VERSION 5.7 ;
  NOWIREEXTENSIONATPIN ON ;
  DIVIDERCHAR "/" ;
  BUSBITCHARS "[]" ;
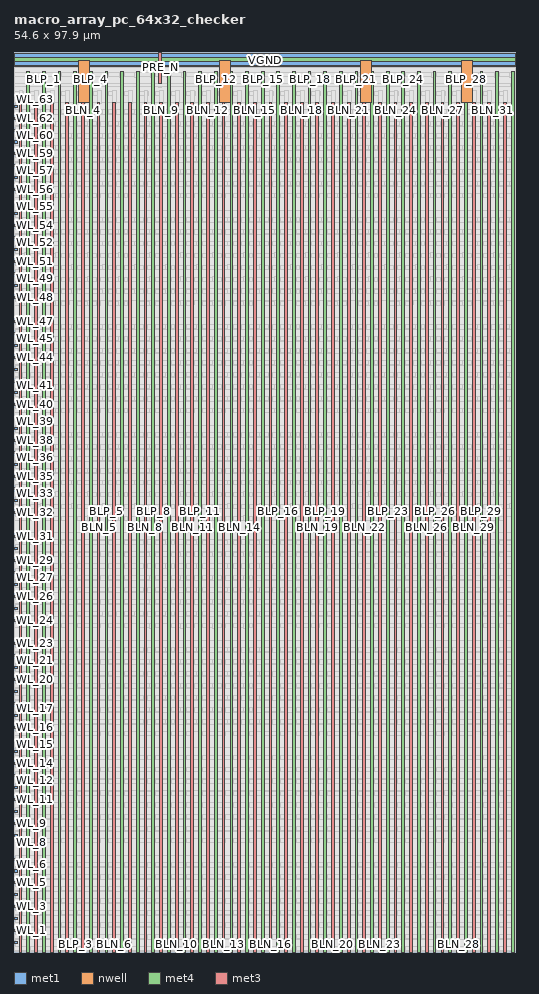
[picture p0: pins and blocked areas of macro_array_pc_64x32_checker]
MACRO macro_array_pc_64x32_checker
  CLASS BLOCK ;
  FOREIGN macro_array_pc_64x32_checker ;
  ORIGIN 0.000 0.000 ;
  SIZE 54.600 BY 97.900 ;
  PIN VPWR
    USE POWER ;
    PORT
      LAYER met1 ;
        RECT 0.000 96.450 54.500 96.850 ;
    END
    PORT
      LAYER nwell ;
        RECT 7.050 92.400 8.250 96.980 ;
    END
    PORT
      LAYER nwell ;
        RECT 22.350 92.400 23.550 96.980 ;
    END
    PORT
      LAYER nwell ;
        RECT 37.650 92.400 38.850 96.980 ;
    END
    PORT
      LAYER nwell ;
        RECT 48.700 92.400 49.900 96.980 ;
    END
    PORT
      LAYER met4 ;
        RECT 0.000 96.350 54.500 97.650 ;
    END
  END VPWR
  PIN VGND
    USE GROUND ;
    PORT
      LAYER met1 ;
        RECT 0.000 97.300 54.500 97.700 ;
    END
  END VGND
  PIN PRE_N
    ANTENNAGATEAREA 9.599999 ;
    PORT
      LAYER met3 ;
        RECT 15.685 94.435 16.095 97.900 ;
    END
  END PRE_N
  PIN BLP_0
    ANTENNADIFFAREA 4.187600 ;
    PORT
      LAYER met4 ;
        RECT 1.400 0.000 1.700 95.800 ;
    END
  END BLP_0
  PIN BLN_0
    ANTENNADIFFAREA 4.187600 ;
    PORT
      LAYER met3 ;
        RECT 0.550 0.000 0.850 92.400 ;
    END
  END BLN_0
  PIN BLP_1
    ANTENNADIFFAREA 4.187600 ;
    PORT
      LAYER met4 ;
        RECT 3.100 0.000 3.400 95.800 ;
    END
  END BLP_1
  PIN BLN_1
    ANTENNADIFFAREA 4.187600 ;
    PORT
      LAYER met3 ;
        RECT 2.250 0.000 2.550 92.400 ;
    END
  END BLN_1
  PIN BLP_2
    ANTENNADIFFAREA 4.187600 ;
    PORT
      LAYER met4 ;
        RECT 4.800 0.000 5.100 95.800 ;
    END
  END BLP_2
  PIN BLN_2
    ANTENNADIFFAREA 4.187600 ;
    PORT
      LAYER met3 ;
        RECT 3.950 0.000 4.250 92.400 ;
    END
  END BLN_2
  PIN BLP_3
    ANTENNADIFFAREA 4.187600 ;
    PORT
      LAYER met4 ;
        RECT 6.500 0.000 6.800 95.800 ;
    END
  END BLP_3
  PIN BLN_3
    ANTENNADIFFAREA 4.187600 ;
    PORT
      LAYER met3 ;
        RECT 5.650 0.000 5.950 92.400 ;
    END
  END BLN_3
  PIN BLP_4
    ANTENNADIFFAREA 4.187600 ;
    PORT
      LAYER met4 ;
        RECT 8.200 0.000 8.500 95.800 ;
    END
  END BLP_4
  PIN BLN_4
    ANTENNADIFFAREA 4.187600 ;
    PORT
      LAYER met3 ;
        RECT 7.350 0.000 7.650 92.400 ;
    END
  END BLN_4
  PIN BLP_5
    ANTENNADIFFAREA 4.187600 ;
    PORT
      LAYER met4 ;
        RECT 9.900 0.000 10.200 95.800 ;
    END
  END BLP_5
  PIN BLN_5
    ANTENNADIFFAREA 4.187600 ;
    PORT
      LAYER met3 ;
        RECT 9.050 0.000 9.350 92.400 ;
    END
  END BLN_5
  PIN BLP_6
    ANTENNADIFFAREA 4.187600 ;
    PORT
      LAYER met4 ;
        RECT 11.600 0.000 11.900 95.800 ;
    END
  END BLP_6
  PIN BLN_6
    ANTENNADIFFAREA 4.187600 ;
    PORT
      LAYER met3 ;
        RECT 10.750 0.000 11.050 92.400 ;
    END
  END BLN_6
  PIN BLP_7
    ANTENNADIFFAREA 4.187600 ;
    PORT
      LAYER met4 ;
        RECT 13.300 0.000 13.600 95.800 ;
    END
  END BLP_7
  PIN BLN_7
    ANTENNADIFFAREA 4.187600 ;
    PORT
      LAYER met3 ;
        RECT 12.450 0.000 12.750 92.400 ;
    END
  END BLN_7
  PIN BLP_8
    ANTENNADIFFAREA 4.187600 ;
    PORT
      LAYER met4 ;
        RECT 15.000 0.000 15.300 95.800 ;
    END
  END BLP_8
  PIN BLN_8
    ANTENNADIFFAREA 4.187600 ;
    PORT
      LAYER met3 ;
        RECT 14.150 0.000 14.450 92.400 ;
    END
  END BLN_8
  PIN BLP_9
    ANTENNADIFFAREA 4.187600 ;
    PORT
      LAYER met4 ;
        RECT 16.700 0.000 17.000 95.800 ;
    END
  END BLP_9
  PIN BLN_9
    ANTENNADIFFAREA 4.187600 ;
    PORT
      LAYER met3 ;
        RECT 15.850 0.000 16.150 92.400 ;
    END
  END BLN_9
  PIN BLP_10
    ANTENNADIFFAREA 4.187600 ;
    PORT
      LAYER met4 ;
        RECT 18.400 0.000 18.700 95.800 ;
    END
  END BLP_10
  PIN BLN_10
    ANTENNADIFFAREA 4.187600 ;
    PORT
      LAYER met3 ;
        RECT 17.550 0.000 17.850 92.400 ;
    END
  END BLN_10
  PIN BLP_11
    ANTENNADIFFAREA 4.187600 ;
    PORT
      LAYER met4 ;
        RECT 20.100 0.000 20.400 95.800 ;
    END
  END BLP_11
  PIN BLN_11
    ANTENNADIFFAREA 4.187600 ;
    PORT
      LAYER met3 ;
        RECT 19.250 0.000 19.550 92.400 ;
    END
  END BLN_11
  PIN BLP_12
    ANTENNADIFFAREA 4.187600 ;
    PORT
      LAYER met4 ;
        RECT 21.800 0.000 22.100 95.800 ;
    END
  END BLP_12
  PIN BLN_12
    ANTENNADIFFAREA 4.187600 ;
    PORT
      LAYER met3 ;
        RECT 20.950 0.000 21.250 92.400 ;
    END
  END BLN_12
  PIN BLP_13
    ANTENNADIFFAREA 4.187600 ;
    PORT
      LAYER met4 ;
        RECT 23.500 0.000 23.800 95.800 ;
    END
  END BLP_13
  PIN BLN_13
    ANTENNADIFFAREA 4.187600 ;
    PORT
      LAYER met3 ;
        RECT 22.650 0.000 22.950 92.400 ;
    END
  END BLN_13
  PIN BLP_14
    ANTENNADIFFAREA 4.187600 ;
    PORT
      LAYER met4 ;
        RECT 25.200 0.000 25.500 95.800 ;
    END
  END BLP_14
  PIN BLN_14
    ANTENNADIFFAREA 4.187600 ;
    PORT
      LAYER met3 ;
        RECT 24.350 0.000 24.650 92.400 ;
    END
  END BLN_14
  PIN BLP_15
    ANTENNADIFFAREA 4.187600 ;
    PORT
      LAYER met4 ;
        RECT 26.900 0.000 27.200 95.800 ;
    END
  END BLP_15
  PIN BLN_15
    ANTENNADIFFAREA 4.187600 ;
    PORT
      LAYER met3 ;
        RECT 26.050 0.000 26.350 92.400 ;
    END
  END BLN_15
  PIN BLP_16
    ANTENNADIFFAREA 4.187600 ;
    PORT
      LAYER met4 ;
        RECT 28.600 0.000 28.900 95.800 ;
    END
  END BLP_16
  PIN BLN_16
    ANTENNADIFFAREA 4.187600 ;
    PORT
      LAYER met3 ;
        RECT 27.750 0.000 28.050 92.400 ;
    END
  END BLN_16
  PIN BLP_17
    ANTENNADIFFAREA 4.187600 ;
    PORT
      LAYER met4 ;
        RECT 30.300 0.000 30.600 95.800 ;
    END
  END BLP_17
  PIN BLN_17
    ANTENNADIFFAREA 4.187600 ;
    PORT
      LAYER met3 ;
        RECT 29.450 0.000 29.750 92.400 ;
    END
  END BLN_17
  PIN BLP_18
    ANTENNADIFFAREA 4.187600 ;
    PORT
      LAYER met4 ;
        RECT 32.000 0.000 32.300 95.800 ;
    END
  END BLP_18
  PIN BLN_18
    ANTENNADIFFAREA 4.187600 ;
    PORT
      LAYER met3 ;
        RECT 31.150 0.000 31.450 92.400 ;
    END
  END BLN_18
  PIN BLP_19
    ANTENNADIFFAREA 4.187600 ;
    PORT
      LAYER met4 ;
        RECT 33.700 0.000 34.000 95.800 ;
    END
  END BLP_19
  PIN BLN_19
    ANTENNADIFFAREA 4.187600 ;
    PORT
      LAYER met3 ;
        RECT 32.850 0.000 33.150 92.400 ;
    END
  END BLN_19
  PIN BLP_20
    ANTENNADIFFAREA 4.187600 ;
    PORT
      LAYER met4 ;
        RECT 35.400 0.000 35.700 95.800 ;
    END
  END BLP_20
  PIN BLN_20
    ANTENNADIFFAREA 4.187600 ;
    PORT
      LAYER met3 ;
        RECT 34.550 0.000 34.850 92.400 ;
    END
  END BLN_20
  PIN BLP_21
    ANTENNADIFFAREA 4.187600 ;
    PORT
      LAYER met4 ;
        RECT 37.100 0.000 37.400 95.800 ;
    END
  END BLP_21
  PIN BLN_21
    ANTENNADIFFAREA 4.187600 ;
    PORT
      LAYER met3 ;
        RECT 36.250 0.000 36.550 92.400 ;
    END
  END BLN_21
  PIN BLP_22
    ANTENNADIFFAREA 4.187600 ;
    PORT
      LAYER met4 ;
        RECT 38.800 0.000 39.100 95.800 ;
    END
  END BLP_22
  PIN BLN_22
    ANTENNADIFFAREA 4.187600 ;
    PORT
      LAYER met3 ;
        RECT 37.950 0.000 38.250 92.400 ;
    END
  END BLN_22
  PIN BLP_23
    ANTENNADIFFAREA 4.187600 ;
    PORT
      LAYER met4 ;
        RECT 40.500 0.000 40.800 95.800 ;
    END
  END BLP_23
  PIN BLN_23
    ANTENNADIFFAREA 4.187600 ;
    PORT
      LAYER met3 ;
        RECT 39.650 0.000 39.950 92.400 ;
    END
  END BLN_23
  PIN BLP_24
    ANTENNADIFFAREA 4.187600 ;
    PORT
      LAYER met4 ;
        RECT 42.200 0.000 42.500 95.800 ;
    END
  END BLP_24
  PIN BLN_24
    ANTENNADIFFAREA 4.187600 ;
    PORT
      LAYER met3 ;
        RECT 41.350 0.000 41.650 92.400 ;
    END
  END BLN_24
  PIN BLP_25
    ANTENNADIFFAREA 4.187600 ;
    PORT
      LAYER met4 ;
        RECT 43.900 0.000 44.200 95.800 ;
    END
  END BLP_25
  PIN BLN_25
    ANTENNADIFFAREA 4.187600 ;
    PORT
      LAYER met3 ;
        RECT 43.050 0.000 43.350 92.400 ;
    END
  END BLN_25
  PIN BLP_26
    ANTENNADIFFAREA 4.187600 ;
    PORT
      LAYER met4 ;
        RECT 45.600 0.000 45.900 95.800 ;
    END
  END BLP_26
  PIN BLN_26
    ANTENNADIFFAREA 4.187600 ;
    PORT
      LAYER met3 ;
        RECT 44.750 0.000 45.050 92.400 ;
    END
  END BLN_26
  PIN BLP_27
    ANTENNADIFFAREA 4.187600 ;
    PORT
      LAYER met4 ;
        RECT 47.300 0.000 47.600 95.800 ;
    END
  END BLP_27
  PIN BLN_27
    ANTENNADIFFAREA 4.187600 ;
    PORT
      LAYER met3 ;
        RECT 46.450 0.000 46.750 92.400 ;
    END
  END BLN_27
  PIN BLP_28
    ANTENNADIFFAREA 4.187600 ;
    PORT
      LAYER met4 ;
        RECT 49.000 0.000 49.300 95.800 ;
    END
  END BLP_28
  PIN BLN_28
    ANTENNADIFFAREA 4.187600 ;
    PORT
      LAYER met3 ;
        RECT 48.150 0.000 48.450 92.400 ;
    END
  END BLN_28
  PIN BLP_29
    ANTENNADIFFAREA 4.187600 ;
    PORT
      LAYER met4 ;
        RECT 50.700 0.000 51.000 95.800 ;
    END
  END BLP_29
  PIN BLN_29
    ANTENNADIFFAREA 4.187600 ;
    PORT
      LAYER met3 ;
        RECT 49.850 0.000 50.150 92.400 ;
    END
  END BLN_29
  PIN BLP_30
    ANTENNADIFFAREA 4.187600 ;
    PORT
      LAYER met4 ;
        RECT 52.400 0.000 52.700 95.800 ;
    END
  END BLP_30
  PIN BLN_30
    ANTENNADIFFAREA 4.187600 ;
    PORT
      LAYER met3 ;
        RECT 51.550 0.000 51.850 92.400 ;
    END
  END BLN_30
  PIN BLP_31
    ANTENNADIFFAREA 4.187600 ;
    PORT
      LAYER met4 ;
        RECT 54.100 0.000 54.400 95.800 ;
    END
  END BLP_31
  PIN BLN_31
    ANTENNADIFFAREA 4.187600 ;
    PORT
      LAYER met3 ;
        RECT 53.250 0.000 53.550 92.400 ;
    END
  END BLN_31
  PIN WL_0
    ANTENNAGATEAREA 2.284800 ;
    PORT
      LAYER met1 ;
        RECT 0.000 0.900 0.390 1.120 ;
    END
  END WL_0
  PIN WL_1
    ANTENNAGATEAREA 2.284800 ;
    PORT
      LAYER met1 ;
        RECT 0.000 2.200 0.390 2.420 ;
    END
  END WL_1
  PIN WL_2
    ANTENNAGATEAREA 2.284800 ;
    PORT
      LAYER met1 ;
        RECT 0.000 3.500 0.390 3.720 ;
    END
  END WL_2
  PIN WL_3
    ANTENNAGATEAREA 2.284800 ;
    PORT
      LAYER met1 ;
        RECT 0.000 4.800 0.390 5.020 ;
    END
  END WL_3
  PIN WL_4
    ANTENNAGATEAREA 2.284800 ;
    PORT
      LAYER met1 ;
        RECT 0.000 6.100 0.390 6.320 ;
    END
  END WL_4
  PIN WL_5
    ANTENNAGATEAREA 2.284800 ;
    PORT
      LAYER met1 ;
        RECT 0.000 7.400 0.390 7.620 ;
    END
  END WL_5
  PIN WL_6
    ANTENNAGATEAREA 2.284800 ;
    PORT
      LAYER met1 ;
        RECT 0.000 8.700 0.390 8.920 ;
    END
  END WL_6
  PIN WL_7
    ANTENNAGATEAREA 2.284800 ;
    PORT
      LAYER met1 ;
        RECT 0.000 10.000 0.390 10.220 ;
    END
  END WL_7
  PIN WL_8
    ANTENNAGATEAREA 2.284800 ;
    PORT
      LAYER met1 ;
        RECT 0.000 12.600 0.390 12.820 ;
    END
  END WL_8
  PIN WL_9
    ANTENNAGATEAREA 2.284800 ;
    PORT
      LAYER met1 ;
        RECT 0.000 13.900 0.390 14.120 ;
    END
  END WL_9
  PIN WL_10
    ANTENNAGATEAREA 2.284800 ;
    PORT
      LAYER met1 ;
        RECT 0.000 15.200 0.390 15.420 ;
    END
  END WL_10
  PIN WL_11
    ANTENNAGATEAREA 2.284800 ;
    PORT
      LAYER met1 ;
        RECT 0.000 16.500 0.390 16.720 ;
    END
  END WL_11
  PIN WL_12
    ANTENNAGATEAREA 2.284800 ;
    PORT
      LAYER met1 ;
        RECT 0.000 17.800 0.390 18.020 ;
    END
  END WL_12
  PIN WL_13
    ANTENNAGATEAREA 2.284800 ;
    PORT
      LAYER met1 ;
        RECT 0.000 19.100 0.390 19.320 ;
    END
  END WL_13
  PIN WL_14
    ANTENNAGATEAREA 2.284800 ;
    PORT
      LAYER met1 ;
        RECT 0.000 20.400 0.390 20.620 ;
    END
  END WL_14
  PIN WL_15
    ANTENNAGATEAREA 2.284800 ;
    PORT
      LAYER met1 ;
        RECT 0.000 21.700 0.390 21.920 ;
    END
  END WL_15
  PIN WL_16
    ANTENNAGATEAREA 2.284800 ;
    PORT
      LAYER met1 ;
        RECT 0.000 24.300 0.390 24.520 ;
    END
  END WL_16
  PIN WL_17
    ANTENNAGATEAREA 2.284800 ;
    PORT
      LAYER met1 ;
        RECT 0.000 25.600 0.390 25.820 ;
    END
  END WL_17
  PIN WL_18
    ANTENNAGATEAREA 2.284800 ;
    PORT
      LAYER met1 ;
        RECT 0.000 26.900 0.390 27.120 ;
    END
  END WL_18
  PIN WL_19
    ANTENNAGATEAREA 2.284800 ;
    PORT
      LAYER met1 ;
        RECT 0.000 28.200 0.390 28.420 ;
    END
  END WL_19
  PIN WL_20
    ANTENNAGATEAREA 2.284800 ;
    PORT
      LAYER met1 ;
        RECT 0.000 29.500 0.390 29.720 ;
    END
  END WL_20
  PIN WL_21
    ANTENNAGATEAREA 2.284800 ;
    PORT
      LAYER met1 ;
        RECT 0.000 30.800 0.390 31.020 ;
    END
  END WL_21
  PIN WL_22
    ANTENNAGATEAREA 2.284800 ;
    PORT
      LAYER met1 ;
        RECT 0.000 32.100 0.390 32.320 ;
    END
  END WL_22
  PIN WL_23
    ANTENNAGATEAREA 2.284800 ;
    PORT
      LAYER met1 ;
        RECT 0.000 33.400 0.390 33.620 ;
    END
  END WL_23
  PIN WL_24
    ANTENNAGATEAREA 2.284800 ;
    PORT
      LAYER met1 ;
        RECT 0.000 36.000 0.390 36.220 ;
    END
  END WL_24
  PIN WL_25
    ANTENNAGATEAREA 2.284800 ;
    PORT
      LAYER met1 ;
        RECT 0.000 37.300 0.390 37.520 ;
    END
  END WL_25
  PIN WL_26
    ANTENNAGATEAREA 2.284800 ;
    PORT
      LAYER met1 ;
        RECT 0.000 38.600 0.390 38.820 ;
    END
  END WL_26
  PIN WL_27
    ANTENNAGATEAREA 2.284800 ;
    PORT
      LAYER met1 ;
        RECT 0.000 39.900 0.390 40.120 ;
    END
  END WL_27
  PIN WL_28
    ANTENNAGATEAREA 2.284800 ;
    PORT
      LAYER met1 ;
        RECT 0.000 41.200 0.390 41.420 ;
    END
  END WL_28
  PIN WL_29
    ANTENNAGATEAREA 2.284800 ;
    PORT
      LAYER met1 ;
        RECT 0.000 42.500 0.390 42.720 ;
    END
  END WL_29
  PIN WL_30
    ANTENNAGATEAREA 2.284800 ;
    PORT
      LAYER met1 ;
        RECT 0.000 43.800 0.390 44.020 ;
    END
  END WL_30
  PIN WL_31
    ANTENNAGATEAREA 2.284800 ;
    PORT
      LAYER met1 ;
        RECT 0.000 45.100 0.390 45.320 ;
    END
  END WL_31
  PIN WL_32
    ANTENNAGATEAREA 2.284800 ;
    PORT
      LAYER met1 ;
        RECT 0.000 47.700 0.390 47.920 ;
    END
  END WL_32
  PIN WL_33
    ANTENNAGATEAREA 2.284800 ;
    PORT
      LAYER met1 ;
        RECT 0.000 49.000 0.390 49.220 ;
    END
  END WL_33
  PIN WL_34
    ANTENNAGATEAREA 2.284800 ;
    PORT
      LAYER met1 ;
        RECT 0.000 50.300 0.390 50.520 ;
    END
  END WL_34
  PIN WL_35
    ANTENNAGATEAREA 2.284800 ;
    PORT
      LAYER met1 ;
        RECT 0.000 51.600 0.390 51.820 ;
    END
  END WL_35
  PIN WL_36
    ANTENNAGATEAREA 2.284800 ;
    PORT
      LAYER met1 ;
        RECT 0.000 52.900 0.390 53.120 ;
    END
  END WL_36
  PIN WL_37
    ANTENNAGATEAREA 2.284800 ;
    PORT
      LAYER met1 ;
        RECT 0.000 54.200 0.390 54.420 ;
    END
  END WL_37
  PIN WL_38
    ANTENNAGATEAREA 2.284800 ;
    PORT
      LAYER met1 ;
        RECT 0.000 55.500 0.390 55.720 ;
    END
  END WL_38
  PIN WL_39
    ANTENNAGATEAREA 2.284800 ;
    PORT
      LAYER met1 ;
        RECT 0.000 56.800 0.390 57.020 ;
    END
  END WL_39
  PIN WL_40
    ANTENNAGATEAREA 2.284800 ;
    PORT
      LAYER met1 ;
        RECT 0.000 59.400 0.390 59.620 ;
    END
  END WL_40
  PIN WL_41
    ANTENNAGATEAREA 2.284800 ;
    PORT
      LAYER met1 ;
        RECT 0.000 60.700 0.390 60.920 ;
    END
  END WL_41
  PIN WL_42
    ANTENNAGATEAREA 2.284800 ;
    PORT
      LAYER met1 ;
        RECT 0.000 62.000 0.390 62.220 ;
    END
  END WL_42
  PIN WL_43
    ANTENNAGATEAREA 2.284800 ;
    PORT
      LAYER met1 ;
        RECT 0.000 63.300 0.390 63.520 ;
    END
  END WL_43
  PIN WL_44
    ANTENNAGATEAREA 2.284800 ;
    PORT
      LAYER met1 ;
        RECT 0.000 64.600 0.390 64.820 ;
    END
  END WL_44
  PIN WL_45
    ANTENNAGATEAREA 2.284800 ;
    PORT
      LAYER met1 ;
        RECT 0.000 65.900 0.390 66.120 ;
    END
  END WL_45
  PIN WL_46
    ANTENNAGATEAREA 2.284800 ;
    PORT
      LAYER met1 ;
        RECT 0.000 67.200 0.390 67.420 ;
    END
  END WL_46
  PIN WL_47
    ANTENNAGATEAREA 2.284800 ;
    PORT
      LAYER met1 ;
        RECT 0.000 68.500 0.390 68.720 ;
    END
  END WL_47
  PIN WL_48
    ANTENNAGATEAREA 2.284800 ;
    PORT
      LAYER met1 ;
        RECT 0.000 71.100 0.390 71.320 ;
    END
  END WL_48
  PIN WL_49
    ANTENNAGATEAREA 2.284800 ;
    PORT
      LAYER met1 ;
        RECT 0.000 72.400 0.390 72.620 ;
    END
  END WL_49
  PIN WL_50
    ANTENNAGATEAREA 2.284800 ;
    PORT
      LAYER met1 ;
        RECT 0.000 73.700 0.390 73.920 ;
    END
  END WL_50
  PIN WL_51
    ANTENNAGATEAREA 2.284800 ;
    PORT
      LAYER met1 ;
        RECT 0.000 75.000 0.390 75.220 ;
    END
  END WL_51
  PIN WL_52
    ANTENNAGATEAREA 2.284800 ;
    PORT
      LAYER met1 ;
        RECT 0.000 76.300 0.390 76.520 ;
    END
  END WL_52
  PIN WL_53
    ANTENNAGATEAREA 2.284800 ;
    PORT
      LAYER met1 ;
        RECT 0.000 77.600 0.390 77.820 ;
    END
  END WL_53
  PIN WL_54
    ANTENNAGATEAREA 2.284800 ;
    PORT
      LAYER met1 ;
        RECT 0.000 78.900 0.390 79.120 ;
    END
  END WL_54
  PIN WL_55
    ANTENNAGATEAREA 2.284800 ;
    PORT
      LAYER met1 ;
        RECT 0.000 80.200 0.390 80.420 ;
    END
  END WL_55
  PIN WL_56
    ANTENNAGATEAREA 2.284800 ;
    PORT
      LAYER met1 ;
        RECT 0.000 82.800 0.390 83.020 ;
    END
  END WL_56
  PIN WL_57
    ANTENNAGATEAREA 2.284800 ;
    PORT
      LAYER met1 ;
        RECT 0.000 84.100 0.390 84.320 ;
    END
  END WL_57
  PIN WL_58
    ANTENNAGATEAREA 2.284800 ;
    PORT
      LAYER met1 ;
        RECT 0.000 85.400 0.390 85.620 ;
    END
  END WL_58
  PIN WL_59
    ANTENNAGATEAREA 2.284800 ;
    PORT
      LAYER met1 ;
        RECT 0.000 86.700 0.390 86.920 ;
    END
  END WL_59
  PIN WL_60
    ANTENNAGATEAREA 2.284800 ;
    PORT
      LAYER met1 ;
        RECT 0.000 88.000 0.390 88.220 ;
    END
  END WL_60
  PIN WL_61
    ANTENNAGATEAREA 2.284800 ;
    PORT
      LAYER met1 ;
        RECT 0.000 89.300 0.390 89.520 ;
    END
  END WL_61
  PIN WL_62
    ANTENNAGATEAREA 2.284800 ;
    PORT
      LAYER met1 ;
        RECT 0.000 90.600 0.390 90.820 ;
    END
  END WL_62
  PIN WL_63
    ANTENNAGATEAREA 2.284800 ;
    PORT
      LAYER met1 ;
        RECT 0.000 91.900 0.390 92.120 ;
    END
  END WL_63
  OBS
      LAYER li1 ;
        RECT 0.140 0.040 53.830 97.650 ;
      LAYER met1 ;
        RECT 0.080 92.400 54.600 96.170 ;
        RECT 0.670 91.620 54.600 92.400 ;
        RECT 0.080 91.100 54.600 91.620 ;
        RECT 0.670 90.320 54.600 91.100 ;
        RECT 0.080 89.800 54.600 90.320 ;
        RECT 0.670 89.020 54.600 89.800 ;
        RECT 0.080 88.500 54.600 89.020 ;
        RECT 0.670 87.720 54.600 88.500 ;
        RECT 0.080 87.200 54.600 87.720 ;
        RECT 0.670 86.420 54.600 87.200 ;
        RECT 0.080 85.900 54.600 86.420 ;
        RECT 0.670 85.120 54.600 85.900 ;
        RECT 0.080 84.600 54.600 85.120 ;
        RECT 0.670 83.820 54.600 84.600 ;
        RECT 0.080 83.300 54.600 83.820 ;
        RECT 0.670 82.520 54.600 83.300 ;
        RECT 0.080 80.700 54.600 82.520 ;
        RECT 0.670 79.920 54.600 80.700 ;
        RECT 0.080 79.400 54.600 79.920 ;
        RECT 0.670 78.620 54.600 79.400 ;
        RECT 0.080 78.100 54.600 78.620 ;
        RECT 0.670 77.320 54.600 78.100 ;
        RECT 0.080 76.800 54.600 77.320 ;
        RECT 0.670 76.020 54.600 76.800 ;
        RECT 0.080 75.500 54.600 76.020 ;
        RECT 0.670 74.720 54.600 75.500 ;
        RECT 0.080 74.200 54.600 74.720 ;
        RECT 0.670 73.420 54.600 74.200 ;
        RECT 0.080 72.900 54.600 73.420 ;
        RECT 0.670 72.120 54.600 72.900 ;
        RECT 0.080 71.600 54.600 72.120 ;
        RECT 0.670 70.820 54.600 71.600 ;
        RECT 0.080 69.000 54.600 70.820 ;
        RECT 0.670 68.220 54.600 69.000 ;
        RECT 0.080 67.700 54.600 68.220 ;
        RECT 0.670 66.920 54.600 67.700 ;
        RECT 0.080 66.400 54.600 66.920 ;
        RECT 0.670 65.620 54.600 66.400 ;
        RECT 0.080 65.100 54.600 65.620 ;
        RECT 0.670 64.320 54.600 65.100 ;
        RECT 0.080 63.800 54.600 64.320 ;
        RECT 0.670 63.020 54.600 63.800 ;
        RECT 0.080 62.500 54.600 63.020 ;
        RECT 0.670 61.720 54.600 62.500 ;
        RECT 0.080 61.200 54.600 61.720 ;
        RECT 0.670 60.420 54.600 61.200 ;
        RECT 0.080 59.900 54.600 60.420 ;
        RECT 0.670 59.120 54.600 59.900 ;
        RECT 0.080 57.300 54.600 59.120 ;
        RECT 0.670 56.520 54.600 57.300 ;
        RECT 0.080 56.000 54.600 56.520 ;
        RECT 0.670 55.220 54.600 56.000 ;
        RECT 0.080 54.700 54.600 55.220 ;
        RECT 0.670 53.920 54.600 54.700 ;
        RECT 0.080 53.400 54.600 53.920 ;
        RECT 0.670 52.620 54.600 53.400 ;
        RECT 0.080 52.100 54.600 52.620 ;
        RECT 0.670 51.320 54.600 52.100 ;
        RECT 0.080 50.800 54.600 51.320 ;
        RECT 0.670 50.020 54.600 50.800 ;
        RECT 0.080 49.500 54.600 50.020 ;
        RECT 0.670 48.720 54.600 49.500 ;
        RECT 0.080 48.200 54.600 48.720 ;
        RECT 0.670 47.420 54.600 48.200 ;
        RECT 0.080 45.600 54.600 47.420 ;
        RECT 0.670 44.820 54.600 45.600 ;
        RECT 0.080 44.300 54.600 44.820 ;
        RECT 0.670 43.520 54.600 44.300 ;
        RECT 0.080 43.000 54.600 43.520 ;
        RECT 0.670 42.220 54.600 43.000 ;
        RECT 0.080 41.700 54.600 42.220 ;
        RECT 0.670 40.920 54.600 41.700 ;
        RECT 0.080 40.400 54.600 40.920 ;
        RECT 0.670 39.620 54.600 40.400 ;
        RECT 0.080 39.100 54.600 39.620 ;
        RECT 0.670 38.320 54.600 39.100 ;
        RECT 0.080 37.800 54.600 38.320 ;
        RECT 0.670 37.020 54.600 37.800 ;
        RECT 0.080 36.500 54.600 37.020 ;
        RECT 0.670 35.720 54.600 36.500 ;
        RECT 0.080 33.900 54.600 35.720 ;
        RECT 0.670 33.120 54.600 33.900 ;
        RECT 0.080 32.600 54.600 33.120 ;
        RECT 0.670 31.820 54.600 32.600 ;
        RECT 0.080 31.300 54.600 31.820 ;
        RECT 0.670 30.520 54.600 31.300 ;
        RECT 0.080 30.000 54.600 30.520 ;
        RECT 0.670 29.220 54.600 30.000 ;
        RECT 0.080 28.700 54.600 29.220 ;
        RECT 0.670 27.920 54.600 28.700 ;
        RECT 0.080 27.400 54.600 27.920 ;
        RECT 0.670 26.620 54.600 27.400 ;
        RECT 0.080 26.100 54.600 26.620 ;
        RECT 0.670 25.320 54.600 26.100 ;
        RECT 0.080 24.800 54.600 25.320 ;
        RECT 0.670 24.020 54.600 24.800 ;
        RECT 0.080 22.200 54.600 24.020 ;
        RECT 0.670 21.420 54.600 22.200 ;
        RECT 0.080 20.900 54.600 21.420 ;
        RECT 0.670 20.120 54.600 20.900 ;
        RECT 0.080 19.600 54.600 20.120 ;
        RECT 0.670 18.820 54.600 19.600 ;
        RECT 0.080 18.300 54.600 18.820 ;
        RECT 0.670 17.520 54.600 18.300 ;
        RECT 0.080 17.000 54.600 17.520 ;
        RECT 0.670 16.220 54.600 17.000 ;
        RECT 0.080 15.700 54.600 16.220 ;
        RECT 0.670 14.920 54.600 15.700 ;
        RECT 0.080 14.400 54.600 14.920 ;
        RECT 0.670 13.620 54.600 14.400 ;
        RECT 0.080 13.100 54.600 13.620 ;
        RECT 0.670 12.320 54.600 13.100 ;
        RECT 0.080 10.500 54.600 12.320 ;
        RECT 0.670 9.720 54.600 10.500 ;
        RECT 0.080 9.200 54.600 9.720 ;
        RECT 0.670 8.420 54.600 9.200 ;
        RECT 0.080 7.900 54.600 8.420 ;
        RECT 0.670 7.120 54.600 7.900 ;
        RECT 0.080 6.600 54.600 7.120 ;
        RECT 0.670 5.820 54.600 6.600 ;
        RECT 0.080 5.300 54.600 5.820 ;
        RECT 0.670 4.520 54.600 5.300 ;
        RECT 0.080 4.000 54.600 4.520 ;
        RECT 0.670 3.220 54.600 4.000 ;
        RECT 0.080 2.700 54.600 3.220 ;
        RECT 0.670 1.920 54.600 2.700 ;
        RECT 0.080 1.400 54.600 1.920 ;
        RECT 0.670 0.620 54.600 1.400 ;
        RECT 0.080 0.170 54.600 0.620 ;
      LAYER met2 ;
        RECT 0.080 48.270 0.880 48.710 ;
        RECT 1.780 48.270 3.245 48.710 ;
        RECT 3.480 48.270 4.280 48.710 ;
        RECT 5.180 48.270 6.645 48.710 ;
        RECT 6.880 48.270 7.680 48.710 ;
        RECT 8.580 48.270 10.045 48.710 ;
        RECT 10.280 48.270 11.080 48.710 ;
        RECT 11.980 48.270 13.445 48.710 ;
        RECT 13.680 48.270 14.480 48.710 ;
        RECT 15.380 48.270 16.845 48.710 ;
        RECT 17.080 48.270 17.880 48.710 ;
        RECT 18.780 48.270 20.245 48.710 ;
        RECT 20.480 48.270 21.280 48.710 ;
        RECT 22.180 48.270 23.645 48.710 ;
        RECT 23.880 48.270 24.680 48.710 ;
        RECT 25.580 48.270 27.045 48.710 ;
        RECT 27.280 48.270 28.080 48.710 ;
        RECT 28.980 48.270 30.445 48.710 ;
        RECT 30.680 48.270 31.480 48.710 ;
        RECT 32.380 48.270 33.845 48.710 ;
        RECT 34.080 48.270 34.880 48.710 ;
        RECT 35.780 48.270 37.245 48.710 ;
        RECT 37.480 48.270 38.280 48.710 ;
        RECT 39.180 48.270 40.645 48.710 ;
        RECT 40.880 48.270 41.680 48.710 ;
        RECT 42.580 48.270 44.045 48.710 ;
        RECT 44.280 48.270 45.080 48.710 ;
        RECT 45.980 48.270 47.445 48.710 ;
        RECT 47.680 48.270 48.480 48.710 ;
        RECT 49.380 48.270 50.845 48.710 ;
        RECT 51.080 48.270 51.880 48.710 ;
        RECT 52.780 48.270 54.245 48.710 ;
        RECT 0.100 94.110 54.040 94.490 ;
        RECT 40.880 84.670 42.345 85.110 ;
        RECT 42.580 84.670 43.380 85.110 ;
        RECT 44.280 84.670 45.745 85.110 ;
        RECT 45.980 84.670 46.780 85.110 ;
        RECT 47.680 84.670 49.145 85.110 ;
        RECT 49.380 84.670 50.180 85.110 ;
        RECT 51.080 84.670 52.545 85.110 ;
        RECT 52.780 84.670 53.580 85.110 ;
        RECT 47.680 85.970 48.480 86.410 ;
        RECT 49.380 85.970 50.845 86.410 ;
        RECT 51.080 85.970 51.880 86.410 ;
        RECT 52.780 85.970 54.245 86.410 ;
        RECT 47.680 87.270 49.145 87.710 ;
        RECT 49.380 87.270 50.180 87.710 ;
        RECT 51.080 87.270 52.545 87.710 ;
        RECT 52.780 87.270 53.580 87.710 ;
        RECT 47.680 88.570 48.480 89.010 ;
        RECT 49.380 88.570 50.845 89.010 ;
        RECT 51.080 88.570 51.880 89.010 ;
        RECT 52.780 88.570 54.245 89.010 ;
        RECT 47.680 89.870 49.145 90.310 ;
        RECT 49.380 89.870 50.180 90.310 ;
        RECT 51.080 89.870 52.545 90.310 ;
        RECT 52.780 89.870 53.580 90.310 ;
        RECT 47.680 91.170 48.480 91.610 ;
        RECT 49.380 91.170 50.845 91.610 ;
        RECT 51.080 91.170 51.880 91.610 ;
        RECT 52.780 91.170 54.245 91.610 ;
        RECT 47.700 93.160 48.590 93.630 ;
        RECT 49.400 93.160 50.290 93.630 ;
        RECT 51.100 93.160 51.990 93.630 ;
        RECT 52.800 93.160 53.690 93.630 ;
        RECT 47.700 95.210 49.235 95.680 ;
        RECT 49.400 95.210 50.935 95.680 ;
        RECT 51.100 95.210 52.635 95.680 ;
        RECT 52.800 95.210 54.335 95.680 ;
        RECT 40.880 85.970 41.680 86.410 ;
        RECT 42.580 85.970 44.045 86.410 ;
        RECT 44.280 85.970 45.080 86.410 ;
        RECT 45.980 85.970 47.445 86.410 ;
        RECT 40.880 91.170 41.680 91.610 ;
        RECT 42.580 91.170 44.045 91.610 ;
        RECT 44.280 91.170 45.080 91.610 ;
        RECT 45.980 91.170 47.445 91.610 ;
        RECT 40.880 88.570 41.680 89.010 ;
        RECT 42.580 88.570 44.045 89.010 ;
        RECT 44.280 88.570 45.080 89.010 ;
        RECT 45.980 88.570 47.445 89.010 ;
        RECT 40.900 93.160 41.790 93.630 ;
        RECT 42.600 93.160 43.490 93.630 ;
        RECT 44.300 93.160 45.190 93.630 ;
        RECT 46.000 93.160 46.890 93.630 ;
        RECT 40.880 87.270 42.345 87.710 ;
        RECT 42.580 87.270 43.380 87.710 ;
        RECT 44.280 87.270 45.745 87.710 ;
        RECT 45.980 87.270 46.780 87.710 ;
        RECT 40.900 95.210 42.435 95.680 ;
        RECT 42.600 95.210 44.135 95.680 ;
        RECT 44.300 95.210 45.835 95.680 ;
        RECT 46.000 95.210 47.535 95.680 ;
        RECT 40.880 89.870 42.345 90.310 ;
        RECT 42.580 89.870 43.380 90.310 ;
        RECT 44.280 89.870 45.745 90.310 ;
        RECT 45.980 89.870 46.780 90.310 ;
        RECT 40.880 72.970 42.345 73.410 ;
        RECT 42.580 72.970 43.380 73.410 ;
        RECT 44.280 72.970 45.745 73.410 ;
        RECT 45.980 72.970 46.780 73.410 ;
        RECT 40.880 74.270 41.680 74.710 ;
        RECT 42.580 74.270 44.045 74.710 ;
        RECT 44.280 74.270 45.080 74.710 ;
        RECT 45.980 74.270 47.445 74.710 ;
        RECT 40.880 75.570 42.345 76.010 ;
        RECT 42.580 75.570 43.380 76.010 ;
        RECT 44.280 75.570 45.745 76.010 ;
        RECT 45.980 75.570 46.780 76.010 ;
        RECT 40.880 76.870 41.680 77.310 ;
        RECT 42.580 76.870 44.045 77.310 ;
        RECT 44.280 76.870 45.080 77.310 ;
        RECT 45.980 76.870 47.445 77.310 ;
        RECT 40.880 78.170 42.345 78.610 ;
        RECT 42.580 78.170 43.380 78.610 ;
        RECT 44.280 78.170 45.745 78.610 ;
        RECT 45.980 78.170 46.780 78.610 ;
        RECT 40.880 79.470 41.680 79.910 ;
        RECT 42.580 79.470 44.045 79.910 ;
        RECT 44.280 79.470 45.080 79.910 ;
        RECT 45.980 79.470 47.445 79.910 ;
        RECT 40.880 82.070 42.345 82.510 ;
        RECT 42.580 82.070 43.380 82.510 ;
        RECT 44.280 82.070 45.745 82.510 ;
        RECT 45.980 82.070 46.780 82.510 ;
        RECT 40.880 83.370 41.680 83.810 ;
        RECT 42.580 83.370 44.045 83.810 ;
        RECT 44.280 83.370 45.080 83.810 ;
        RECT 45.980 83.370 47.445 83.810 ;
        RECT 47.680 72.970 49.145 73.410 ;
        RECT 49.380 72.970 50.180 73.410 ;
        RECT 51.080 72.970 52.545 73.410 ;
        RECT 52.780 72.970 53.580 73.410 ;
        RECT 47.680 78.170 49.145 78.610 ;
        RECT 49.380 78.170 50.180 78.610 ;
        RECT 51.080 78.170 52.545 78.610 ;
        RECT 52.780 78.170 53.580 78.610 ;
        RECT 47.680 75.570 49.145 76.010 ;
        RECT 49.380 75.570 50.180 76.010 ;
        RECT 51.080 75.570 52.545 76.010 ;
        RECT 52.780 75.570 53.580 76.010 ;
        RECT 47.680 79.470 48.480 79.910 ;
        RECT 49.380 79.470 50.845 79.910 ;
        RECT 51.080 79.470 51.880 79.910 ;
        RECT 52.780 79.470 54.245 79.910 ;
        RECT 47.680 74.270 48.480 74.710 ;
        RECT 49.380 74.270 50.845 74.710 ;
        RECT 51.080 74.270 51.880 74.710 ;
        RECT 52.780 74.270 54.245 74.710 ;
        RECT 47.680 82.070 49.145 82.510 ;
        RECT 49.380 82.070 50.180 82.510 ;
        RECT 51.080 82.070 52.545 82.510 ;
        RECT 52.780 82.070 53.580 82.510 ;
        RECT 47.680 76.870 48.480 77.310 ;
        RECT 49.380 76.870 50.845 77.310 ;
        RECT 51.080 76.870 51.880 77.310 ;
        RECT 52.780 76.870 54.245 77.310 ;
        RECT 47.680 83.370 48.480 83.810 ;
        RECT 49.380 83.370 50.845 83.810 ;
        RECT 51.080 83.370 51.880 83.810 ;
        RECT 52.780 83.370 54.245 83.810 ;
        RECT 27.280 84.670 28.745 85.110 ;
        RECT 28.980 84.670 29.780 85.110 ;
        RECT 30.680 84.670 32.145 85.110 ;
        RECT 32.380 84.670 33.180 85.110 ;
        RECT 34.080 84.670 35.545 85.110 ;
        RECT 35.780 84.670 36.580 85.110 ;
        RECT 37.480 84.670 38.945 85.110 ;
        RECT 39.180 84.670 39.980 85.110 ;
        RECT 34.080 85.970 34.880 86.410 ;
        RECT 35.780 85.970 37.245 86.410 ;
        RECT 37.480 85.970 38.280 86.410 ;
        RECT 39.180 85.970 40.645 86.410 ;
        RECT 34.080 87.270 35.545 87.710 ;
        RECT 35.780 87.270 36.580 87.710 ;
        RECT 37.480 87.270 38.945 87.710 ;
        RECT 39.180 87.270 39.980 87.710 ;
        RECT 34.080 88.570 34.880 89.010 ;
        RECT 35.780 88.570 37.245 89.010 ;
        RECT 37.480 88.570 38.280 89.010 ;
        RECT 39.180 88.570 40.645 89.010 ;
        RECT 34.080 89.870 35.545 90.310 ;
        RECT 35.780 89.870 36.580 90.310 ;
        RECT 37.480 89.870 38.945 90.310 ;
        RECT 39.180 89.870 39.980 90.310 ;
        RECT 34.080 91.170 34.880 91.610 ;
        RECT 35.780 91.170 37.245 91.610 ;
        RECT 37.480 91.170 38.280 91.610 ;
        RECT 39.180 91.170 40.645 91.610 ;
        RECT 34.100 93.160 34.990 93.630 ;
        RECT 35.800 93.160 36.690 93.630 ;
        RECT 37.500 93.160 38.390 93.630 ;
        RECT 39.200 93.160 40.090 93.630 ;
        RECT 34.100 95.210 35.635 95.680 ;
        RECT 35.800 95.210 37.335 95.680 ;
        RECT 37.500 95.210 39.035 95.680 ;
        RECT 39.200 95.210 40.735 95.680 ;
        RECT 27.280 85.970 28.080 86.410 ;
        RECT 28.980 85.970 30.445 86.410 ;
        RECT 30.680 85.970 31.480 86.410 ;
        RECT 32.380 85.970 33.845 86.410 ;
        RECT 27.280 91.170 28.080 91.610 ;
        RECT 28.980 91.170 30.445 91.610 ;
        RECT 30.680 91.170 31.480 91.610 ;
        RECT 32.380 91.170 33.845 91.610 ;
        RECT 27.280 88.570 28.080 89.010 ;
        RECT 28.980 88.570 30.445 89.010 ;
        RECT 30.680 88.570 31.480 89.010 ;
        RECT 32.380 88.570 33.845 89.010 ;
        RECT 27.300 93.160 28.190 93.630 ;
        RECT 29.000 93.160 29.890 93.630 ;
        RECT 30.700 93.160 31.590 93.630 ;
        RECT 32.400 93.160 33.290 93.630 ;
        RECT 27.280 87.270 28.745 87.710 ;
        RECT 28.980 87.270 29.780 87.710 ;
        RECT 30.680 87.270 32.145 87.710 ;
        RECT 32.380 87.270 33.180 87.710 ;
        RECT 27.300 95.210 28.835 95.680 ;
        RECT 29.000 95.210 30.535 95.680 ;
        RECT 30.700 95.210 32.235 95.680 ;
        RECT 32.400 95.210 33.935 95.680 ;
        RECT 27.280 89.870 28.745 90.310 ;
        RECT 28.980 89.870 29.780 90.310 ;
        RECT 30.680 89.870 32.145 90.310 ;
        RECT 32.380 89.870 33.180 90.310 ;
        RECT 27.280 74.270 28.080 74.710 ;
        RECT 28.980 74.270 30.445 74.710 ;
        RECT 30.680 74.270 31.480 74.710 ;
        RECT 32.380 74.270 33.845 74.710 ;
        RECT 27.280 76.870 28.080 77.310 ;
        RECT 28.980 76.870 30.445 77.310 ;
        RECT 30.680 76.870 31.480 77.310 ;
        RECT 32.380 76.870 33.845 77.310 ;
        RECT 27.280 79.470 28.080 79.910 ;
        RECT 28.980 79.470 30.445 79.910 ;
        RECT 30.680 79.470 31.480 79.910 ;
        RECT 32.380 79.470 33.845 79.910 ;
        RECT 27.280 78.170 28.745 78.610 ;
        RECT 28.980 78.170 29.780 78.610 ;
        RECT 30.680 78.170 32.145 78.610 ;
        RECT 32.380 78.170 33.180 78.610 ;
        RECT 27.280 83.370 28.080 83.810 ;
        RECT 28.980 83.370 30.445 83.810 ;
        RECT 30.680 83.370 31.480 83.810 ;
        RECT 32.380 83.370 33.845 83.810 ;
        RECT 27.280 82.070 28.745 82.510 ;
        RECT 28.980 82.070 29.780 82.510 ;
        RECT 30.680 82.070 32.145 82.510 ;
        RECT 32.380 82.070 33.180 82.510 ;
        RECT 27.280 75.570 28.745 76.010 ;
        RECT 28.980 75.570 29.780 76.010 ;
        RECT 30.680 75.570 32.145 76.010 ;
        RECT 32.380 75.570 33.180 76.010 ;
        RECT 27.280 72.970 28.745 73.410 ;
        RECT 28.980 72.970 29.780 73.410 ;
        RECT 30.680 72.970 32.145 73.410 ;
        RECT 32.380 72.970 33.180 73.410 ;
        RECT 34.080 79.470 34.880 79.910 ;
        RECT 35.780 79.470 37.245 79.910 ;
        RECT 37.480 79.470 38.280 79.910 ;
        RECT 39.180 79.470 40.645 79.910 ;
        RECT 34.080 82.070 35.545 82.510 ;
        RECT 35.780 82.070 36.580 82.510 ;
        RECT 37.480 82.070 38.945 82.510 ;
        RECT 39.180 82.070 39.980 82.510 ;
        RECT 34.080 74.270 34.880 74.710 ;
        RECT 35.780 74.270 37.245 74.710 ;
        RECT 37.480 74.270 38.280 74.710 ;
        RECT 39.180 74.270 40.645 74.710 ;
        RECT 34.080 83.370 34.880 83.810 ;
        RECT 35.780 83.370 37.245 83.810 ;
        RECT 37.480 83.370 38.280 83.810 ;
        RECT 39.180 83.370 40.645 83.810 ;
        RECT 34.080 75.570 35.545 76.010 ;
        RECT 35.780 75.570 36.580 76.010 ;
        RECT 37.480 75.570 38.945 76.010 ;
        RECT 39.180 75.570 39.980 76.010 ;
        RECT 34.080 78.170 35.545 78.610 ;
        RECT 35.780 78.170 36.580 78.610 ;
        RECT 37.480 78.170 38.945 78.610 ;
        RECT 39.180 78.170 39.980 78.610 ;
        RECT 34.080 76.870 34.880 77.310 ;
        RECT 35.780 76.870 37.245 77.310 ;
        RECT 37.480 76.870 38.280 77.310 ;
        RECT 39.180 76.870 40.645 77.310 ;
        RECT 34.080 72.970 35.545 73.410 ;
        RECT 35.780 72.970 36.580 73.410 ;
        RECT 37.480 72.970 38.945 73.410 ;
        RECT 39.180 72.970 39.980 73.410 ;
        RECT 34.080 61.270 35.545 61.710 ;
        RECT 35.780 61.270 36.580 61.710 ;
        RECT 37.480 61.270 38.945 61.710 ;
        RECT 39.180 61.270 39.980 61.710 ;
        RECT 34.080 62.570 34.880 63.010 ;
        RECT 35.780 62.570 37.245 63.010 ;
        RECT 37.480 62.570 38.280 63.010 ;
        RECT 39.180 62.570 40.645 63.010 ;
        RECT 34.080 63.870 35.545 64.310 ;
        RECT 35.780 63.870 36.580 64.310 ;
        RECT 37.480 63.870 38.945 64.310 ;
        RECT 39.180 63.870 39.980 64.310 ;
        RECT 34.080 65.170 34.880 65.610 ;
        RECT 35.780 65.170 37.245 65.610 ;
        RECT 37.480 65.170 38.280 65.610 ;
        RECT 39.180 65.170 40.645 65.610 ;
        RECT 34.080 66.470 35.545 66.910 ;
        RECT 35.780 66.470 36.580 66.910 ;
        RECT 37.480 66.470 38.945 66.910 ;
        RECT 39.180 66.470 39.980 66.910 ;
        RECT 34.080 67.770 34.880 68.210 ;
        RECT 35.780 67.770 37.245 68.210 ;
        RECT 37.480 67.770 38.280 68.210 ;
        RECT 39.180 67.770 40.645 68.210 ;
        RECT 34.080 70.370 35.545 70.810 ;
        RECT 35.780 70.370 36.580 70.810 ;
        RECT 37.480 70.370 38.945 70.810 ;
        RECT 39.180 70.370 39.980 70.810 ;
        RECT 34.080 71.670 34.880 72.110 ;
        RECT 35.780 71.670 37.245 72.110 ;
        RECT 37.480 71.670 38.280 72.110 ;
        RECT 39.180 71.670 40.645 72.110 ;
        RECT 27.280 66.470 28.745 66.910 ;
        RECT 28.980 66.470 29.780 66.910 ;
        RECT 30.680 66.470 32.145 66.910 ;
        RECT 32.380 66.470 33.180 66.910 ;
        RECT 27.280 63.870 28.745 64.310 ;
        RECT 28.980 63.870 29.780 64.310 ;
        RECT 30.680 63.870 32.145 64.310 ;
        RECT 32.380 63.870 33.180 64.310 ;
        RECT 27.280 67.770 28.080 68.210 ;
        RECT 28.980 67.770 30.445 68.210 ;
        RECT 30.680 67.770 31.480 68.210 ;
        RECT 32.380 67.770 33.845 68.210 ;
        RECT 27.280 62.570 28.080 63.010 ;
        RECT 28.980 62.570 30.445 63.010 ;
        RECT 30.680 62.570 31.480 63.010 ;
        RECT 32.380 62.570 33.845 63.010 ;
        RECT 27.280 70.370 28.745 70.810 ;
        RECT 28.980 70.370 29.780 70.810 ;
        RECT 30.680 70.370 32.145 70.810 ;
        RECT 32.380 70.370 33.180 70.810 ;
        RECT 27.280 65.170 28.080 65.610 ;
        RECT 28.980 65.170 30.445 65.610 ;
        RECT 30.680 65.170 31.480 65.610 ;
        RECT 32.380 65.170 33.845 65.610 ;
        RECT 27.280 71.670 28.080 72.110 ;
        RECT 28.980 71.670 30.445 72.110 ;
        RECT 30.680 71.670 31.480 72.110 ;
        RECT 32.380 71.670 33.845 72.110 ;
        RECT 27.280 61.270 28.745 61.710 ;
        RECT 28.980 61.270 29.780 61.710 ;
        RECT 30.680 61.270 32.145 61.710 ;
        RECT 32.380 61.270 33.180 61.710 ;
        RECT 28.980 52.170 29.780 52.610 ;
        RECT 30.680 52.170 32.145 52.610 ;
        RECT 32.380 52.170 33.180 52.610 ;
        RECT 27.280 53.470 28.080 53.910 ;
        RECT 28.980 53.470 30.445 53.910 ;
        RECT 30.680 53.470 31.480 53.910 ;
        RECT 32.380 53.470 33.845 53.910 ;
        RECT 27.280 54.770 28.745 55.210 ;
        RECT 28.980 54.770 29.780 55.210 ;
        RECT 30.680 54.770 32.145 55.210 ;
        RECT 32.380 54.770 33.180 55.210 ;
        RECT 27.280 56.070 28.080 56.510 ;
        RECT 28.980 56.070 30.445 56.510 ;
        RECT 30.680 56.070 31.480 56.510 ;
        RECT 32.380 56.070 33.845 56.510 ;
        RECT 27.280 49.570 28.745 50.010 ;
        RECT 27.280 58.670 28.745 59.110 ;
        RECT 28.980 58.670 29.780 59.110 ;
        RECT 30.680 58.670 32.145 59.110 ;
        RECT 32.380 58.670 33.180 59.110 ;
        RECT 27.280 59.970 28.080 60.410 ;
        RECT 28.980 59.970 30.445 60.410 ;
        RECT 30.680 59.970 31.480 60.410 ;
        RECT 32.380 59.970 33.845 60.410 ;
        RECT 32.380 49.570 33.180 50.010 ;
        RECT 27.280 50.870 28.080 51.310 ;
        RECT 28.980 50.870 30.445 51.310 ;
        RECT 30.680 50.870 31.480 51.310 ;
        RECT 32.380 50.870 33.845 51.310 ;
        RECT 27.280 52.170 28.745 52.610 ;
        RECT 28.980 49.570 29.780 50.010 ;
        RECT 30.680 49.570 32.145 50.010 ;
        RECT 39.180 49.570 39.980 50.010 ;
        RECT 34.080 54.770 35.545 55.210 ;
        RECT 35.780 54.770 36.580 55.210 ;
        RECT 37.480 54.770 38.945 55.210 ;
        RECT 39.180 54.770 39.980 55.210 ;
        RECT 34.080 52.170 35.545 52.610 ;
        RECT 35.780 52.170 36.580 52.610 ;
        RECT 37.480 52.170 38.945 52.610 ;
        RECT 39.180 52.170 39.980 52.610 ;
        RECT 34.080 56.070 34.880 56.510 ;
        RECT 35.780 56.070 37.245 56.510 ;
        RECT 37.480 56.070 38.280 56.510 ;
        RECT 39.180 56.070 40.645 56.510 ;
        RECT 34.080 50.870 34.880 51.310 ;
        RECT 35.780 50.870 37.245 51.310 ;
        RECT 37.480 50.870 38.280 51.310 ;
        RECT 39.180 50.870 40.645 51.310 ;
        RECT 34.080 58.670 35.545 59.110 ;
        RECT 35.780 58.670 36.580 59.110 ;
        RECT 37.480 58.670 38.945 59.110 ;
        RECT 39.180 58.670 39.980 59.110 ;
        RECT 34.080 53.470 34.880 53.910 ;
        RECT 35.780 53.470 37.245 53.910 ;
        RECT 37.480 53.470 38.280 53.910 ;
        RECT 39.180 53.470 40.645 53.910 ;
        RECT 34.080 59.970 34.880 60.410 ;
        RECT 35.780 59.970 37.245 60.410 ;
        RECT 37.480 59.970 38.280 60.410 ;
        RECT 39.180 59.970 40.645 60.410 ;
        RECT 34.080 49.570 35.545 50.010 ;
        RECT 35.780 49.570 36.580 50.010 ;
        RECT 37.480 49.570 38.945 50.010 ;
        RECT 47.680 61.270 49.145 61.710 ;
        RECT 49.380 61.270 50.180 61.710 ;
        RECT 51.080 61.270 52.545 61.710 ;
        RECT 52.780 61.270 53.580 61.710 ;
        RECT 47.680 62.570 48.480 63.010 ;
        RECT 49.380 62.570 50.845 63.010 ;
        RECT 51.080 62.570 51.880 63.010 ;
        RECT 52.780 62.570 54.245 63.010 ;
        RECT 47.680 63.870 49.145 64.310 ;
        RECT 49.380 63.870 50.180 64.310 ;
        RECT 51.080 63.870 52.545 64.310 ;
        RECT 52.780 63.870 53.580 64.310 ;
        RECT 47.680 65.170 48.480 65.610 ;
        RECT 49.380 65.170 50.845 65.610 ;
        RECT 51.080 65.170 51.880 65.610 ;
        RECT 52.780 65.170 54.245 65.610 ;
        RECT 47.680 66.470 49.145 66.910 ;
        RECT 49.380 66.470 50.180 66.910 ;
        RECT 51.080 66.470 52.545 66.910 ;
        RECT 52.780 66.470 53.580 66.910 ;
        RECT 47.680 67.770 48.480 68.210 ;
        RECT 49.380 67.770 50.845 68.210 ;
        RECT 51.080 67.770 51.880 68.210 ;
        RECT 52.780 67.770 54.245 68.210 ;
        RECT 47.680 70.370 49.145 70.810 ;
        RECT 49.380 70.370 50.180 70.810 ;
        RECT 51.080 70.370 52.545 70.810 ;
        RECT 52.780 70.370 53.580 70.810 ;
        RECT 47.680 71.670 48.480 72.110 ;
        RECT 49.380 71.670 50.845 72.110 ;
        RECT 51.080 71.670 51.880 72.110 ;
        RECT 52.780 71.670 54.245 72.110 ;
        RECT 40.880 66.470 42.345 66.910 ;
        RECT 42.580 66.470 43.380 66.910 ;
        RECT 44.280 66.470 45.745 66.910 ;
        RECT 45.980 66.470 46.780 66.910 ;
        RECT 40.880 63.870 42.345 64.310 ;
        RECT 42.580 63.870 43.380 64.310 ;
        RECT 44.280 63.870 45.745 64.310 ;
        RECT 45.980 63.870 46.780 64.310 ;
        RECT 40.880 67.770 41.680 68.210 ;
        RECT 42.580 67.770 44.045 68.210 ;
        RECT 44.280 67.770 45.080 68.210 ;
        RECT 45.980 67.770 47.445 68.210 ;
        RECT 40.880 62.570 41.680 63.010 ;
        RECT 42.580 62.570 44.045 63.010 ;
        RECT 44.280 62.570 45.080 63.010 ;
        RECT 45.980 62.570 47.445 63.010 ;
        RECT 40.880 70.370 42.345 70.810 ;
        RECT 42.580 70.370 43.380 70.810 ;
        RECT 44.280 70.370 45.745 70.810 ;
        RECT 45.980 70.370 46.780 70.810 ;
        RECT 40.880 65.170 41.680 65.610 ;
        RECT 42.580 65.170 44.045 65.610 ;
        RECT 44.280 65.170 45.080 65.610 ;
        RECT 45.980 65.170 47.445 65.610 ;
        RECT 40.880 71.670 41.680 72.110 ;
        RECT 42.580 71.670 44.045 72.110 ;
        RECT 44.280 71.670 45.080 72.110 ;
        RECT 45.980 71.670 47.445 72.110 ;
        RECT 40.880 61.270 42.345 61.710 ;
        RECT 42.580 61.270 43.380 61.710 ;
        RECT 44.280 61.270 45.745 61.710 ;
        RECT 45.980 61.270 46.780 61.710 ;
        RECT 45.980 52.170 46.780 52.610 ;
        RECT 42.580 49.570 43.380 50.010 ;
        RECT 44.280 49.570 45.745 50.010 ;
        RECT 40.880 54.770 42.345 55.210 ;
        RECT 42.580 54.770 43.380 55.210 ;
        RECT 44.280 54.770 45.745 55.210 ;
        RECT 40.880 50.870 41.680 51.310 ;
        RECT 40.880 53.470 41.680 53.910 ;
        RECT 42.580 53.470 44.045 53.910 ;
        RECT 44.280 53.470 45.080 53.910 ;
        RECT 45.980 53.470 47.445 53.910 ;
        RECT 42.580 50.870 44.045 51.310 ;
        RECT 44.280 50.870 45.080 51.310 ;
        RECT 45.980 50.870 47.445 51.310 ;
        RECT 45.980 54.770 46.780 55.210 ;
        RECT 45.980 49.570 46.780 50.010 ;
        RECT 40.880 52.170 42.345 52.610 ;
        RECT 40.880 56.070 41.680 56.510 ;
        RECT 42.580 56.070 44.045 56.510 ;
        RECT 40.880 59.970 41.680 60.410 ;
        RECT 42.580 59.970 44.045 60.410 ;
        RECT 44.280 59.970 45.080 60.410 ;
        RECT 45.980 59.970 47.445 60.410 ;
        RECT 44.280 56.070 45.080 56.510 ;
        RECT 45.980 56.070 47.445 56.510 ;
        RECT 42.580 52.170 43.380 52.610 ;
        RECT 40.880 58.670 42.345 59.110 ;
        RECT 42.580 58.670 43.380 59.110 ;
        RECT 44.280 58.670 45.745 59.110 ;
        RECT 45.980 58.670 46.780 59.110 ;
        RECT 44.280 52.170 45.745 52.610 ;
        RECT 40.880 49.570 42.345 50.010 ;
        RECT 49.380 56.070 50.845 56.510 ;
        RECT 51.080 56.070 51.880 56.510 ;
        RECT 52.780 56.070 54.245 56.510 ;
        RECT 47.680 53.470 48.480 53.910 ;
        RECT 49.380 53.470 50.845 53.910 ;
        RECT 51.080 53.470 51.880 53.910 ;
        RECT 52.780 53.470 54.245 53.910 ;
        RECT 47.680 54.770 49.145 55.210 ;
        RECT 49.380 54.770 50.180 55.210 ;
        RECT 51.080 54.770 52.545 55.210 ;
        RECT 52.780 54.770 53.580 55.210 ;
        RECT 47.680 49.570 49.145 50.010 ;
        RECT 49.380 49.570 50.180 50.010 ;
        RECT 51.080 49.570 52.545 50.010 ;
        RECT 52.780 49.570 53.580 50.010 ;
        RECT 47.680 58.670 49.145 59.110 ;
        RECT 49.380 58.670 50.180 59.110 ;
        RECT 51.080 58.670 52.545 59.110 ;
        RECT 52.780 58.670 53.580 59.110 ;
        RECT 47.680 59.970 48.480 60.410 ;
        RECT 49.380 59.970 50.845 60.410 ;
        RECT 51.080 59.970 51.880 60.410 ;
        RECT 52.780 59.970 54.245 60.410 ;
        RECT 47.680 52.170 49.145 52.610 ;
        RECT 49.380 52.170 50.180 52.610 ;
        RECT 51.080 52.170 52.545 52.610 ;
        RECT 52.780 52.170 53.580 52.610 ;
        RECT 47.680 50.870 48.480 51.310 ;
        RECT 49.380 50.870 50.845 51.310 ;
        RECT 51.080 50.870 51.880 51.310 ;
        RECT 52.780 50.870 54.245 51.310 ;
        RECT 47.680 56.070 48.480 56.510 ;
        RECT 13.680 84.670 15.145 85.110 ;
        RECT 15.380 84.670 16.180 85.110 ;
        RECT 17.080 84.670 18.545 85.110 ;
        RECT 18.780 84.670 19.580 85.110 ;
        RECT 20.480 84.670 21.945 85.110 ;
        RECT 22.180 84.670 22.980 85.110 ;
        RECT 23.880 84.670 25.345 85.110 ;
        RECT 25.580 84.670 26.380 85.110 ;
        RECT 20.480 85.970 21.280 86.410 ;
        RECT 22.180 85.970 23.645 86.410 ;
        RECT 23.880 85.970 24.680 86.410 ;
        RECT 25.580 85.970 27.045 86.410 ;
        RECT 20.480 87.270 21.945 87.710 ;
        RECT 22.180 87.270 22.980 87.710 ;
        RECT 23.880 87.270 25.345 87.710 ;
        RECT 25.580 87.270 26.380 87.710 ;
        RECT 20.480 88.570 21.280 89.010 ;
        RECT 22.180 88.570 23.645 89.010 ;
        RECT 23.880 88.570 24.680 89.010 ;
        RECT 25.580 88.570 27.045 89.010 ;
        RECT 20.480 89.870 21.945 90.310 ;
        RECT 22.180 89.870 22.980 90.310 ;
        RECT 23.880 89.870 25.345 90.310 ;
        RECT 25.580 89.870 26.380 90.310 ;
        RECT 20.480 91.170 21.280 91.610 ;
        RECT 22.180 91.170 23.645 91.610 ;
        RECT 23.880 91.170 24.680 91.610 ;
        RECT 25.580 91.170 27.045 91.610 ;
        RECT 20.500 93.160 21.390 93.630 ;
        RECT 22.200 93.160 23.090 93.630 ;
        RECT 23.900 93.160 24.790 93.630 ;
        RECT 25.600 93.160 26.490 93.630 ;
        RECT 20.500 95.210 22.035 95.680 ;
        RECT 22.200 95.210 23.735 95.680 ;
        RECT 23.900 95.210 25.435 95.680 ;
        RECT 25.600 95.210 27.135 95.680 ;
        RECT 13.680 85.970 14.480 86.410 ;
        RECT 15.380 85.970 16.845 86.410 ;
        RECT 17.080 85.970 17.880 86.410 ;
        RECT 18.780 85.970 20.245 86.410 ;
        RECT 13.680 91.170 14.480 91.610 ;
        RECT 15.380 91.170 16.845 91.610 ;
        RECT 17.080 91.170 17.880 91.610 ;
        RECT 18.780 91.170 20.245 91.610 ;
        RECT 13.680 88.570 14.480 89.010 ;
        RECT 15.380 88.570 16.845 89.010 ;
        RECT 17.080 88.570 17.880 89.010 ;
        RECT 18.780 88.570 20.245 89.010 ;
        RECT 13.700 93.160 14.590 93.630 ;
        RECT 15.400 93.160 16.290 93.630 ;
        RECT 17.100 93.160 17.990 93.630 ;
        RECT 18.800 93.160 19.690 93.630 ;
        RECT 13.680 87.270 15.145 87.710 ;
        RECT 15.380 87.270 16.180 87.710 ;
        RECT 17.080 87.270 18.545 87.710 ;
        RECT 18.780 87.270 19.580 87.710 ;
        RECT 13.700 95.210 15.235 95.680 ;
        RECT 15.400 95.210 16.935 95.680 ;
        RECT 17.100 95.210 18.635 95.680 ;
        RECT 18.800 95.210 20.335 95.680 ;
        RECT 13.680 89.870 15.145 90.310 ;
        RECT 15.380 89.870 16.180 90.310 ;
        RECT 17.080 89.870 18.545 90.310 ;
        RECT 18.780 89.870 19.580 90.310 ;
        RECT 13.680 72.970 15.145 73.410 ;
        RECT 15.380 72.970 16.180 73.410 ;
        RECT 17.080 72.970 18.545 73.410 ;
        RECT 18.780 72.970 19.580 73.410 ;
        RECT 13.680 74.270 14.480 74.710 ;
        RECT 15.380 74.270 16.845 74.710 ;
        RECT 17.080 74.270 17.880 74.710 ;
        RECT 18.780 74.270 20.245 74.710 ;
        RECT 13.680 75.570 15.145 76.010 ;
        RECT 15.380 75.570 16.180 76.010 ;
        RECT 17.080 75.570 18.545 76.010 ;
        RECT 18.780 75.570 19.580 76.010 ;
        RECT 13.680 76.870 14.480 77.310 ;
        RECT 15.380 76.870 16.845 77.310 ;
        RECT 17.080 76.870 17.880 77.310 ;
        RECT 18.780 76.870 20.245 77.310 ;
        RECT 13.680 78.170 15.145 78.610 ;
        RECT 15.380 78.170 16.180 78.610 ;
        RECT 17.080 78.170 18.545 78.610 ;
        RECT 18.780 78.170 19.580 78.610 ;
        RECT 13.680 79.470 14.480 79.910 ;
        RECT 15.380 79.470 16.845 79.910 ;
        RECT 17.080 79.470 17.880 79.910 ;
        RECT 18.780 79.470 20.245 79.910 ;
        RECT 13.680 82.070 15.145 82.510 ;
        RECT 15.380 82.070 16.180 82.510 ;
        RECT 17.080 82.070 18.545 82.510 ;
        RECT 18.780 82.070 19.580 82.510 ;
        RECT 13.680 83.370 14.480 83.810 ;
        RECT 15.380 83.370 16.845 83.810 ;
        RECT 17.080 83.370 17.880 83.810 ;
        RECT 18.780 83.370 20.245 83.810 ;
        RECT 20.480 72.970 21.945 73.410 ;
        RECT 22.180 72.970 22.980 73.410 ;
        RECT 23.880 72.970 25.345 73.410 ;
        RECT 25.580 72.970 26.380 73.410 ;
        RECT 20.480 78.170 21.945 78.610 ;
        RECT 22.180 78.170 22.980 78.610 ;
        RECT 23.880 78.170 25.345 78.610 ;
        RECT 25.580 78.170 26.380 78.610 ;
        RECT 20.480 75.570 21.945 76.010 ;
        RECT 22.180 75.570 22.980 76.010 ;
        RECT 23.880 75.570 25.345 76.010 ;
        RECT 25.580 75.570 26.380 76.010 ;
        RECT 20.480 79.470 21.280 79.910 ;
        RECT 22.180 79.470 23.645 79.910 ;
        RECT 23.880 79.470 24.680 79.910 ;
        RECT 25.580 79.470 27.045 79.910 ;
        RECT 20.480 74.270 21.280 74.710 ;
        RECT 22.180 74.270 23.645 74.710 ;
        RECT 23.880 74.270 24.680 74.710 ;
        RECT 25.580 74.270 27.045 74.710 ;
        RECT 20.480 82.070 21.945 82.510 ;
        RECT 22.180 82.070 22.980 82.510 ;
        RECT 23.880 82.070 25.345 82.510 ;
        RECT 25.580 82.070 26.380 82.510 ;
        RECT 20.480 76.870 21.280 77.310 ;
        RECT 22.180 76.870 23.645 77.310 ;
        RECT 23.880 76.870 24.680 77.310 ;
        RECT 25.580 76.870 27.045 77.310 ;
        RECT 20.480 83.370 21.280 83.810 ;
        RECT 22.180 83.370 23.645 83.810 ;
        RECT 23.880 83.370 24.680 83.810 ;
        RECT 25.580 83.370 27.045 83.810 ;
        RECT 1.780 84.670 2.580 85.110 ;
        RECT 3.480 84.670 4.945 85.110 ;
        RECT 5.180 84.670 5.980 85.110 ;
        RECT 6.880 84.670 8.345 85.110 ;
        RECT 8.580 84.670 9.380 85.110 ;
        RECT 10.280 84.670 11.745 85.110 ;
        RECT 11.980 84.670 12.780 85.110 ;
        RECT 0.080 84.670 1.545 85.110 ;
        RECT 8.580 85.970 10.045 86.410 ;
        RECT 10.280 85.970 11.080 86.410 ;
        RECT 11.980 85.970 13.445 86.410 ;
        RECT 6.880 87.270 8.345 87.710 ;
        RECT 8.580 87.270 9.380 87.710 ;
        RECT 10.280 87.270 11.745 87.710 ;
        RECT 11.980 87.270 12.780 87.710 ;
        RECT 6.880 88.570 7.680 89.010 ;
        RECT 8.580 88.570 10.045 89.010 ;
        RECT 10.280 88.570 11.080 89.010 ;
        RECT 11.980 88.570 13.445 89.010 ;
        RECT 6.880 89.870 8.345 90.310 ;
        RECT 8.580 89.870 9.380 90.310 ;
        RECT 10.280 89.870 11.745 90.310 ;
        RECT 11.980 89.870 12.780 90.310 ;
        RECT 6.880 91.170 7.680 91.610 ;
        RECT 8.580 91.170 10.045 91.610 ;
        RECT 10.280 91.170 11.080 91.610 ;
        RECT 11.980 91.170 13.445 91.610 ;
        RECT 6.900 93.160 7.790 93.630 ;
        RECT 8.600 93.160 9.490 93.630 ;
        RECT 10.300 93.160 11.190 93.630 ;
        RECT 12.000 93.160 12.890 93.630 ;
        RECT 6.900 95.210 8.435 95.680 ;
        RECT 8.600 95.210 10.135 95.680 ;
        RECT 10.300 95.210 11.835 95.680 ;
        RECT 12.000 95.210 13.535 95.680 ;
        RECT 6.880 85.970 7.680 86.410 ;
        RECT 7.940 96.390 8.460 96.910 ;
        RECT 3.480 85.970 4.280 86.410 ;
        RECT 5.180 85.970 6.645 86.410 ;
        RECT 0.080 91.170 0.880 91.610 ;
        RECT 1.780 91.170 3.245 91.610 ;
        RECT 3.480 91.170 4.280 91.610 ;
        RECT 5.180 91.170 6.645 91.610 ;
        RECT 0.080 88.570 0.880 89.010 ;
        RECT 1.780 88.570 3.245 89.010 ;
        RECT 3.480 88.570 4.280 89.010 ;
        RECT 5.180 88.570 6.645 89.010 ;
        RECT 0.100 93.160 0.990 93.630 ;
        RECT 1.800 93.160 2.690 93.630 ;
        RECT 3.500 93.160 4.390 93.630 ;
        RECT 5.200 93.160 6.090 93.630 ;
        RECT 0.080 87.270 1.545 87.710 ;
        RECT 1.780 87.270 2.580 87.710 ;
        RECT 3.480 87.270 4.945 87.710 ;
        RECT 5.180 87.270 5.980 87.710 ;
        RECT 0.100 95.210 1.635 95.680 ;
        RECT 1.800 95.210 3.335 95.680 ;
        RECT 3.500 95.210 5.035 95.680 ;
        RECT 5.200 95.210 6.735 95.680 ;
        RECT 0.080 89.870 1.545 90.310 ;
        RECT 1.780 89.870 2.580 90.310 ;
        RECT 3.480 89.870 4.945 90.310 ;
        RECT 5.180 89.870 5.980 90.310 ;
        RECT 0.080 85.970 0.880 86.410 ;
        RECT 1.780 85.970 3.245 86.410 ;
        RECT 0.080 76.870 0.880 77.310 ;
        RECT 0.080 82.070 1.545 82.510 ;
        RECT 3.480 76.870 4.280 77.310 ;
        RECT 5.180 76.870 6.645 77.310 ;
        RECT 5.180 72.970 5.980 73.410 ;
        RECT 0.080 83.370 0.880 83.810 ;
        RECT 1.780 79.470 3.245 79.910 ;
        RECT 3.480 79.470 4.280 79.910 ;
        RECT 5.180 79.470 6.645 79.910 ;
        RECT 3.480 74.270 4.280 74.710 ;
        RECT 1.780 78.170 2.580 78.610 ;
        RECT 3.480 78.170 4.945 78.610 ;
        RECT 5.180 78.170 5.980 78.610 ;
        RECT 1.780 75.570 2.580 76.010 ;
        RECT 1.780 83.370 3.245 83.810 ;
        RECT 3.480 83.370 4.280 83.810 ;
        RECT 5.180 83.370 6.645 83.810 ;
        RECT 1.780 82.070 2.580 82.510 ;
        RECT 3.480 82.070 4.945 82.510 ;
        RECT 5.180 82.070 5.980 82.510 ;
        RECT 1.780 76.870 3.245 77.310 ;
        RECT 3.480 75.570 4.945 76.010 ;
        RECT 5.180 75.570 5.980 76.010 ;
        RECT 1.780 74.270 3.245 74.710 ;
        RECT 0.080 79.470 0.880 79.910 ;
        RECT 1.780 72.970 2.580 73.410 ;
        RECT 0.080 74.270 0.880 74.710 ;
        RECT 0.080 75.570 1.545 76.010 ;
        RECT 0.080 78.170 1.545 78.610 ;
        RECT 5.180 74.270 6.645 74.710 ;
        RECT 0.080 72.970 1.545 73.410 ;
        RECT 3.480 72.970 4.945 73.410 ;
        RECT 8.580 74.270 10.045 74.710 ;
        RECT 6.880 82.070 8.345 82.510 ;
        RECT 8.580 82.070 9.380 82.510 ;
        RECT 10.280 82.070 11.745 82.510 ;
        RECT 11.980 82.070 12.780 82.510 ;
        RECT 10.280 74.270 11.080 74.710 ;
        RECT 11.980 74.270 13.445 74.710 ;
        RECT 10.280 79.470 11.080 79.910 ;
        RECT 11.980 79.470 13.445 79.910 ;
        RECT 6.880 83.370 7.680 83.810 ;
        RECT 8.580 83.370 10.045 83.810 ;
        RECT 10.280 83.370 11.080 83.810 ;
        RECT 11.980 83.370 13.445 83.810 ;
        RECT 6.880 72.970 8.345 73.410 ;
        RECT 8.580 75.570 9.380 76.010 ;
        RECT 10.280 75.570 11.745 76.010 ;
        RECT 11.980 75.570 12.780 76.010 ;
        RECT 11.980 78.170 12.780 78.610 ;
        RECT 6.880 78.170 8.345 78.610 ;
        RECT 8.580 78.170 9.380 78.610 ;
        RECT 10.280 78.170 11.745 78.610 ;
        RECT 6.880 76.870 7.680 77.310 ;
        RECT 8.580 72.970 9.380 73.410 ;
        RECT 10.280 72.970 11.745 73.410 ;
        RECT 11.980 72.970 12.780 73.410 ;
        RECT 8.580 76.870 10.045 77.310 ;
        RECT 10.280 76.870 11.080 77.310 ;
        RECT 11.980 76.870 13.445 77.310 ;
        RECT 6.880 75.570 8.345 76.010 ;
        RECT 6.880 79.470 7.680 79.910 ;
        RECT 8.580 79.470 10.045 79.910 ;
        RECT 6.880 74.270 7.680 74.710 ;
        RECT 6.880 67.770 7.680 68.210 ;
        RECT 8.580 67.770 10.045 68.210 ;
        RECT 10.280 67.770 11.080 68.210 ;
        RECT 11.980 67.770 13.445 68.210 ;
        RECT 6.880 70.370 8.345 70.810 ;
        RECT 8.580 70.370 9.380 70.810 ;
        RECT 10.280 70.370 11.745 70.810 ;
        RECT 11.980 70.370 12.780 70.810 ;
        RECT 6.880 66.470 8.345 66.910 ;
        RECT 8.580 66.470 9.380 66.910 ;
        RECT 10.280 66.470 11.745 66.910 ;
        RECT 11.980 66.470 12.780 66.910 ;
        RECT 6.880 62.570 7.680 63.010 ;
        RECT 8.580 62.570 10.045 63.010 ;
        RECT 10.280 62.570 11.080 63.010 ;
        RECT 11.980 62.570 13.445 63.010 ;
        RECT 6.880 61.270 8.345 61.710 ;
        RECT 8.580 61.270 9.380 61.710 ;
        RECT 10.280 61.270 11.745 61.710 ;
        RECT 11.980 61.270 12.780 61.710 ;
        RECT 6.880 71.670 7.680 72.110 ;
        RECT 8.580 71.670 10.045 72.110 ;
        RECT 10.280 71.670 11.080 72.110 ;
        RECT 11.980 71.670 13.445 72.110 ;
        RECT 6.880 65.170 7.680 65.610 ;
        RECT 8.580 65.170 10.045 65.610 ;
        RECT 10.280 65.170 11.080 65.610 ;
        RECT 11.980 65.170 13.445 65.610 ;
        RECT 6.880 63.870 8.345 64.310 ;
        RECT 8.580 63.870 9.380 64.310 ;
        RECT 10.280 63.870 11.745 64.310 ;
        RECT 11.980 63.870 12.780 64.310 ;
        RECT 3.480 61.270 4.945 61.710 ;
        RECT 5.180 61.270 5.980 61.710 ;
        RECT 3.480 66.470 4.945 66.910 ;
        RECT 5.180 66.470 5.980 66.910 ;
        RECT 3.480 70.370 4.945 70.810 ;
        RECT 5.180 70.370 5.980 70.810 ;
        RECT 0.080 71.670 0.880 72.110 ;
        RECT 1.780 71.670 3.245 72.110 ;
        RECT 3.480 71.670 4.280 72.110 ;
        RECT 5.180 71.670 6.645 72.110 ;
        RECT 3.480 67.770 4.280 68.210 ;
        RECT 5.180 67.770 6.645 68.210 ;
        RECT 0.080 62.570 0.880 63.010 ;
        RECT 1.780 62.570 3.245 63.010 ;
        RECT 0.080 65.170 0.880 65.610 ;
        RECT 1.780 65.170 3.245 65.610 ;
        RECT 3.480 65.170 4.280 65.610 ;
        RECT 5.180 65.170 6.645 65.610 ;
        RECT 3.480 62.570 4.280 63.010 ;
        RECT 5.180 62.570 6.645 63.010 ;
        RECT 0.080 70.370 1.545 70.810 ;
        RECT 1.780 70.370 2.580 70.810 ;
        RECT 0.080 63.870 1.545 64.310 ;
        RECT 1.780 63.870 2.580 64.310 ;
        RECT 3.480 63.870 4.945 64.310 ;
        RECT 5.180 63.870 5.980 64.310 ;
        RECT 0.080 66.470 1.545 66.910 ;
        RECT 1.780 66.470 2.580 66.910 ;
        RECT 0.080 61.270 1.545 61.710 ;
        RECT 1.780 61.270 2.580 61.710 ;
        RECT 0.080 67.770 0.880 68.210 ;
        RECT 1.780 67.770 3.245 68.210 ;
        RECT 3.480 58.670 4.945 59.110 ;
        RECT 5.180 58.670 5.980 59.110 ;
        RECT 0.080 52.170 1.545 52.610 ;
        RECT 1.780 52.170 2.580 52.610 ;
        RECT 3.480 52.170 4.945 52.610 ;
        RECT 5.180 52.170 5.980 52.610 ;
        RECT 0.080 56.070 0.880 56.510 ;
        RECT 1.780 56.070 3.245 56.510 ;
        RECT 3.480 56.070 4.280 56.510 ;
        RECT 5.180 56.070 6.645 56.510 ;
        RECT 0.080 49.570 1.545 50.010 ;
        RECT 0.080 54.770 1.545 55.210 ;
        RECT 1.780 54.770 2.580 55.210 ;
        RECT 3.480 54.770 4.945 55.210 ;
        RECT 5.180 54.770 5.980 55.210 ;
        RECT 0.080 59.970 0.880 60.410 ;
        RECT 1.780 59.970 3.245 60.410 ;
        RECT 3.480 59.970 4.280 60.410 ;
        RECT 5.180 59.970 6.645 60.410 ;
        RECT 0.080 50.870 0.880 51.310 ;
        RECT 1.780 50.870 3.245 51.310 ;
        RECT 3.480 50.870 4.280 51.310 ;
        RECT 5.180 50.870 6.645 51.310 ;
        RECT 0.080 53.470 0.880 53.910 ;
        RECT 1.780 53.470 3.245 53.910 ;
        RECT 3.480 53.470 4.280 53.910 ;
        RECT 5.180 53.470 6.645 53.910 ;
        RECT 1.780 49.570 2.580 50.010 ;
        RECT 3.480 49.570 4.945 50.010 ;
        RECT 5.180 49.570 5.980 50.010 ;
        RECT 0.080 58.670 1.545 59.110 ;
        RECT 1.780 58.670 2.580 59.110 ;
        RECT 10.280 53.470 11.080 53.910 ;
        RECT 11.980 53.470 13.445 53.910 ;
        RECT 6.880 50.870 7.680 51.310 ;
        RECT 8.580 50.870 10.045 51.310 ;
        RECT 10.280 50.870 11.080 51.310 ;
        RECT 11.980 50.870 13.445 51.310 ;
        RECT 6.880 59.970 7.680 60.410 ;
        RECT 8.580 59.970 10.045 60.410 ;
        RECT 10.280 59.970 11.080 60.410 ;
        RECT 11.980 59.970 13.445 60.410 ;
        RECT 6.880 52.170 8.345 52.610 ;
        RECT 8.580 52.170 9.380 52.610 ;
        RECT 10.280 52.170 11.745 52.610 ;
        RECT 11.980 52.170 12.780 52.610 ;
        RECT 6.880 54.770 8.345 55.210 ;
        RECT 8.580 54.770 9.380 55.210 ;
        RECT 10.280 54.770 11.745 55.210 ;
        RECT 11.980 54.770 12.780 55.210 ;
        RECT 6.880 56.070 7.680 56.510 ;
        RECT 8.580 56.070 10.045 56.510 ;
        RECT 10.280 56.070 11.080 56.510 ;
        RECT 11.980 56.070 13.445 56.510 ;
        RECT 6.880 58.670 8.345 59.110 ;
        RECT 8.580 58.670 9.380 59.110 ;
        RECT 10.280 58.670 11.745 59.110 ;
        RECT 11.980 58.670 12.780 59.110 ;
        RECT 6.880 49.570 8.345 50.010 ;
        RECT 8.580 49.570 9.380 50.010 ;
        RECT 10.280 49.570 11.745 50.010 ;
        RECT 11.980 49.570 12.780 50.010 ;
        RECT 6.880 53.470 7.680 53.910 ;
        RECT 8.580 53.470 10.045 53.910 ;
        RECT 20.480 65.170 21.280 65.610 ;
        RECT 22.180 65.170 23.645 65.610 ;
        RECT 23.880 65.170 24.680 65.610 ;
        RECT 25.580 65.170 27.045 65.610 ;
        RECT 20.480 61.270 21.945 61.710 ;
        RECT 22.180 61.270 22.980 61.710 ;
        RECT 23.880 61.270 25.345 61.710 ;
        RECT 25.580 61.270 26.380 61.710 ;
        RECT 20.480 70.370 21.945 70.810 ;
        RECT 22.180 70.370 22.980 70.810 ;
        RECT 23.880 70.370 25.345 70.810 ;
        RECT 25.580 70.370 26.380 70.810 ;
        RECT 20.480 62.570 21.280 63.010 ;
        RECT 22.180 62.570 23.645 63.010 ;
        RECT 23.880 62.570 24.680 63.010 ;
        RECT 25.580 62.570 27.045 63.010 ;
        RECT 20.480 67.770 21.280 68.210 ;
        RECT 22.180 67.770 23.645 68.210 ;
        RECT 23.880 67.770 24.680 68.210 ;
        RECT 25.580 67.770 27.045 68.210 ;
        RECT 20.480 63.870 21.945 64.310 ;
        RECT 22.180 63.870 22.980 64.310 ;
        RECT 23.880 63.870 25.345 64.310 ;
        RECT 25.580 63.870 26.380 64.310 ;
        RECT 20.480 71.670 21.280 72.110 ;
        RECT 22.180 71.670 23.645 72.110 ;
        RECT 23.880 71.670 24.680 72.110 ;
        RECT 25.580 71.670 27.045 72.110 ;
        RECT 20.480 66.470 21.945 66.910 ;
        RECT 22.180 66.470 22.980 66.910 ;
        RECT 23.880 66.470 25.345 66.910 ;
        RECT 25.580 66.470 26.380 66.910 ;
        RECT 17.080 67.770 17.880 68.210 ;
        RECT 18.780 67.770 20.245 68.210 ;
        RECT 17.080 70.370 18.545 70.810 ;
        RECT 18.780 70.370 19.580 70.810 ;
        RECT 17.080 61.270 18.545 61.710 ;
        RECT 18.780 61.270 19.580 61.710 ;
        RECT 13.680 63.870 15.145 64.310 ;
        RECT 15.380 63.870 16.180 64.310 ;
        RECT 17.080 63.870 18.545 64.310 ;
        RECT 18.780 63.870 19.580 64.310 ;
        RECT 17.080 65.170 17.880 65.610 ;
        RECT 18.780 65.170 20.245 65.610 ;
        RECT 13.680 62.570 14.480 63.010 ;
        RECT 15.380 62.570 16.845 63.010 ;
        RECT 13.680 71.670 14.480 72.110 ;
        RECT 15.380 71.670 16.845 72.110 ;
        RECT 17.080 71.670 17.880 72.110 ;
        RECT 18.780 71.670 20.245 72.110 ;
        RECT 17.080 62.570 17.880 63.010 ;
        RECT 18.780 62.570 20.245 63.010 ;
        RECT 13.680 61.270 15.145 61.710 ;
        RECT 15.380 61.270 16.180 61.710 ;
        RECT 13.680 66.470 15.145 66.910 ;
        RECT 15.380 66.470 16.180 66.910 ;
        RECT 17.080 66.470 18.545 66.910 ;
        RECT 18.780 66.470 19.580 66.910 ;
        RECT 13.680 70.370 15.145 70.810 ;
        RECT 15.380 70.370 16.180 70.810 ;
        RECT 13.680 67.770 14.480 68.210 ;
        RECT 15.380 67.770 16.845 68.210 ;
        RECT 13.680 65.170 14.480 65.610 ;
        RECT 15.380 65.170 16.845 65.610 ;
        RECT 17.080 54.770 18.545 55.210 ;
        RECT 18.780 54.770 19.580 55.210 ;
        RECT 13.680 58.670 15.145 59.110 ;
        RECT 15.380 58.670 16.180 59.110 ;
        RECT 17.080 58.670 18.545 59.110 ;
        RECT 18.780 58.670 19.580 59.110 ;
        RECT 13.680 56.070 14.480 56.510 ;
        RECT 15.380 56.070 16.845 56.510 ;
        RECT 17.080 56.070 17.880 56.510 ;
        RECT 18.780 56.070 20.245 56.510 ;
        RECT 13.680 52.170 15.145 52.610 ;
        RECT 15.380 52.170 16.180 52.610 ;
        RECT 17.080 52.170 18.545 52.610 ;
        RECT 18.780 52.170 19.580 52.610 ;
        RECT 13.680 50.870 14.480 51.310 ;
        RECT 15.380 50.870 16.845 51.310 ;
        RECT 17.080 50.870 17.880 51.310 ;
        RECT 18.780 50.870 20.245 51.310 ;
        RECT 13.680 59.970 14.480 60.410 ;
        RECT 15.380 59.970 16.845 60.410 ;
        RECT 17.080 59.970 17.880 60.410 ;
        RECT 18.780 59.970 20.245 60.410 ;
        RECT 13.680 53.470 14.480 53.910 ;
        RECT 15.380 53.470 16.845 53.910 ;
        RECT 17.080 53.470 17.880 53.910 ;
        RECT 18.780 53.470 20.245 53.910 ;
        RECT 13.680 49.570 15.145 50.010 ;
        RECT 15.380 49.570 16.180 50.010 ;
        RECT 17.080 49.570 18.545 50.010 ;
        RECT 18.780 49.570 19.580 50.010 ;
        RECT 13.680 54.770 15.145 55.210 ;
        RECT 15.380 54.770 16.180 55.210 ;
        RECT 23.880 54.770 25.345 55.210 ;
        RECT 25.580 54.770 26.380 55.210 ;
        RECT 20.480 52.170 21.945 52.610 ;
        RECT 22.180 52.170 22.980 52.610 ;
        RECT 23.880 52.170 25.345 52.610 ;
        RECT 25.580 52.170 26.380 52.610 ;
        RECT 20.480 59.970 21.280 60.410 ;
        RECT 22.180 59.970 23.645 60.410 ;
        RECT 23.880 59.970 24.680 60.410 ;
        RECT 25.580 59.970 27.045 60.410 ;
        RECT 20.480 56.070 21.280 56.510 ;
        RECT 22.180 56.070 23.645 56.510 ;
        RECT 23.880 56.070 24.680 56.510 ;
        RECT 25.580 56.070 27.045 56.510 ;
        RECT 20.480 58.670 21.945 59.110 ;
        RECT 22.180 58.670 22.980 59.110 ;
        RECT 23.880 58.670 25.345 59.110 ;
        RECT 25.580 58.670 26.380 59.110 ;
        RECT 20.480 53.470 21.280 53.910 ;
        RECT 22.180 53.470 23.645 53.910 ;
        RECT 23.880 53.470 24.680 53.910 ;
        RECT 25.580 53.470 27.045 53.910 ;
        RECT 20.480 50.870 21.280 51.310 ;
        RECT 22.180 50.870 23.645 51.310 ;
        RECT 23.880 50.870 24.680 51.310 ;
        RECT 25.580 50.870 27.045 51.310 ;
        RECT 20.480 49.570 21.945 50.010 ;
        RECT 22.180 49.570 22.980 50.010 ;
        RECT 23.880 49.570 25.345 50.010 ;
        RECT 25.580 49.570 26.380 50.010 ;
        RECT 20.480 54.770 21.945 55.210 ;
        RECT 22.180 54.770 22.980 55.210 ;
        RECT 20.480 36.570 21.280 37.010 ;
        RECT 22.180 36.570 23.645 37.010 ;
        RECT 23.880 36.570 24.680 37.010 ;
        RECT 25.580 36.570 27.045 37.010 ;
        RECT 20.480 37.870 21.945 38.310 ;
        RECT 22.180 37.870 22.980 38.310 ;
        RECT 23.880 37.870 25.345 38.310 ;
        RECT 25.580 37.870 26.380 38.310 ;
        RECT 20.480 39.170 21.280 39.610 ;
        RECT 22.180 39.170 23.645 39.610 ;
        RECT 23.880 39.170 24.680 39.610 ;
        RECT 25.580 39.170 27.045 39.610 ;
        RECT 20.480 40.470 21.945 40.910 ;
        RECT 22.180 40.470 22.980 40.910 ;
        RECT 23.880 40.470 25.345 40.910 ;
        RECT 25.580 40.470 26.380 40.910 ;
        RECT 20.480 41.770 21.280 42.210 ;
        RECT 22.180 41.770 23.645 42.210 ;
        RECT 23.880 41.770 24.680 42.210 ;
        RECT 25.580 41.770 27.045 42.210 ;
        RECT 20.480 43.070 21.945 43.510 ;
        RECT 22.180 43.070 22.980 43.510 ;
        RECT 23.880 43.070 25.345 43.510 ;
        RECT 25.580 43.070 26.380 43.510 ;
        RECT 20.480 44.370 21.280 44.810 ;
        RECT 22.180 44.370 23.645 44.810 ;
        RECT 23.880 44.370 24.680 44.810 ;
        RECT 25.580 44.370 27.045 44.810 ;
        RECT 20.480 46.970 21.945 47.410 ;
        RECT 22.180 46.970 22.980 47.410 ;
        RECT 23.880 46.970 25.345 47.410 ;
        RECT 25.580 46.970 26.380 47.410 ;
        RECT 13.680 41.770 14.480 42.210 ;
        RECT 15.380 41.770 16.845 42.210 ;
        RECT 17.080 41.770 17.880 42.210 ;
        RECT 18.780 41.770 20.245 42.210 ;
        RECT 13.680 39.170 14.480 39.610 ;
        RECT 15.380 39.170 16.845 39.610 ;
        RECT 17.080 39.170 17.880 39.610 ;
        RECT 18.780 39.170 20.245 39.610 ;
        RECT 13.680 43.070 15.145 43.510 ;
        RECT 15.380 43.070 16.180 43.510 ;
        RECT 17.080 43.070 18.545 43.510 ;
        RECT 18.780 43.070 19.580 43.510 ;
        RECT 13.680 37.870 15.145 38.310 ;
        RECT 15.380 37.870 16.180 38.310 ;
        RECT 17.080 37.870 18.545 38.310 ;
        RECT 18.780 37.870 19.580 38.310 ;
        RECT 13.680 44.370 14.480 44.810 ;
        RECT 15.380 44.370 16.845 44.810 ;
        RECT 17.080 44.370 17.880 44.810 ;
        RECT 18.780 44.370 20.245 44.810 ;
        RECT 13.680 40.470 15.145 40.910 ;
        RECT 15.380 40.470 16.180 40.910 ;
        RECT 17.080 40.470 18.545 40.910 ;
        RECT 18.780 40.470 19.580 40.910 ;
        RECT 13.680 46.970 15.145 47.410 ;
        RECT 15.380 46.970 16.180 47.410 ;
        RECT 17.080 46.970 18.545 47.410 ;
        RECT 18.780 46.970 19.580 47.410 ;
        RECT 13.680 36.570 14.480 37.010 ;
        RECT 15.380 36.570 16.845 37.010 ;
        RECT 17.080 36.570 17.880 37.010 ;
        RECT 18.780 36.570 20.245 37.010 ;
        RECT 13.680 24.870 14.480 25.310 ;
        RECT 15.380 24.870 16.845 25.310 ;
        RECT 17.080 24.870 17.880 25.310 ;
        RECT 18.780 24.870 20.245 25.310 ;
        RECT 13.680 26.170 15.145 26.610 ;
        RECT 15.380 26.170 16.180 26.610 ;
        RECT 17.080 26.170 18.545 26.610 ;
        RECT 18.780 26.170 19.580 26.610 ;
        RECT 13.680 27.470 14.480 27.910 ;
        RECT 15.380 27.470 16.845 27.910 ;
        RECT 17.080 27.470 17.880 27.910 ;
        RECT 18.780 27.470 20.245 27.910 ;
        RECT 13.680 28.770 15.145 29.210 ;
        RECT 15.380 28.770 16.180 29.210 ;
        RECT 17.080 28.770 18.545 29.210 ;
        RECT 18.780 28.770 19.580 29.210 ;
        RECT 13.680 30.070 14.480 30.510 ;
        RECT 15.380 30.070 16.845 30.510 ;
        RECT 17.080 30.070 17.880 30.510 ;
        RECT 18.780 30.070 20.245 30.510 ;
        RECT 13.680 31.370 15.145 31.810 ;
        RECT 15.380 31.370 16.180 31.810 ;
        RECT 17.080 31.370 18.545 31.810 ;
        RECT 18.780 31.370 19.580 31.810 ;
        RECT 13.680 32.670 14.480 33.110 ;
        RECT 15.380 32.670 16.845 33.110 ;
        RECT 17.080 32.670 17.880 33.110 ;
        RECT 18.780 32.670 20.245 33.110 ;
        RECT 13.680 35.270 15.145 35.710 ;
        RECT 15.380 35.270 16.180 35.710 ;
        RECT 17.080 35.270 18.545 35.710 ;
        RECT 18.780 35.270 19.580 35.710 ;
        RECT 20.480 24.870 21.280 25.310 ;
        RECT 22.180 24.870 23.645 25.310 ;
        RECT 23.880 24.870 24.680 25.310 ;
        RECT 25.580 24.870 27.045 25.310 ;
        RECT 20.480 30.070 21.280 30.510 ;
        RECT 22.180 30.070 23.645 30.510 ;
        RECT 23.880 30.070 24.680 30.510 ;
        RECT 25.580 30.070 27.045 30.510 ;
        RECT 20.480 27.470 21.280 27.910 ;
        RECT 22.180 27.470 23.645 27.910 ;
        RECT 23.880 27.470 24.680 27.910 ;
        RECT 25.580 27.470 27.045 27.910 ;
        RECT 20.480 31.370 21.945 31.810 ;
        RECT 22.180 31.370 22.980 31.810 ;
        RECT 23.880 31.370 25.345 31.810 ;
        RECT 25.580 31.370 26.380 31.810 ;
        RECT 20.480 26.170 21.945 26.610 ;
        RECT 22.180 26.170 22.980 26.610 ;
        RECT 23.880 26.170 25.345 26.610 ;
        RECT 25.580 26.170 26.380 26.610 ;
        RECT 20.480 32.670 21.280 33.110 ;
        RECT 22.180 32.670 23.645 33.110 ;
        RECT 23.880 32.670 24.680 33.110 ;
        RECT 25.580 32.670 27.045 33.110 ;
        RECT 20.480 28.770 21.945 29.210 ;
        RECT 22.180 28.770 22.980 29.210 ;
        RECT 23.880 28.770 25.345 29.210 ;
        RECT 25.580 28.770 26.380 29.210 ;
        RECT 20.480 35.270 21.945 35.710 ;
        RECT 22.180 35.270 22.980 35.710 ;
        RECT 23.880 35.270 25.345 35.710 ;
        RECT 25.580 35.270 26.380 35.710 ;
        RECT 6.880 36.570 7.680 37.010 ;
        RECT 8.580 36.570 10.045 37.010 ;
        RECT 10.280 36.570 11.080 37.010 ;
        RECT 11.980 36.570 13.445 37.010 ;
        RECT 6.880 37.870 8.345 38.310 ;
        RECT 8.580 37.870 9.380 38.310 ;
        RECT 10.280 37.870 11.745 38.310 ;
        RECT 11.980 37.870 12.780 38.310 ;
        RECT 6.880 39.170 7.680 39.610 ;
        RECT 8.580 39.170 10.045 39.610 ;
        RECT 10.280 39.170 11.080 39.610 ;
        RECT 11.980 39.170 13.445 39.610 ;
        RECT 6.880 40.470 8.345 40.910 ;
        RECT 8.580 40.470 9.380 40.910 ;
        RECT 10.280 40.470 11.745 40.910 ;
        RECT 11.980 40.470 12.780 40.910 ;
        RECT 6.880 41.770 7.680 42.210 ;
        RECT 8.580 41.770 10.045 42.210 ;
        RECT 10.280 41.770 11.080 42.210 ;
        RECT 11.980 41.770 13.445 42.210 ;
        RECT 6.880 43.070 8.345 43.510 ;
        RECT 8.580 43.070 9.380 43.510 ;
        RECT 10.280 43.070 11.745 43.510 ;
        RECT 11.980 43.070 12.780 43.510 ;
        RECT 6.880 44.370 7.680 44.810 ;
        RECT 8.580 44.370 10.045 44.810 ;
        RECT 10.280 44.370 11.080 44.810 ;
        RECT 11.980 44.370 13.445 44.810 ;
        RECT 6.880 46.970 8.345 47.410 ;
        RECT 8.580 46.970 9.380 47.410 ;
        RECT 10.280 46.970 11.745 47.410 ;
        RECT 11.980 46.970 12.780 47.410 ;
        RECT 0.080 41.770 0.880 42.210 ;
        RECT 1.780 41.770 3.245 42.210 ;
        RECT 3.480 41.770 4.280 42.210 ;
        RECT 5.180 41.770 6.645 42.210 ;
        RECT 0.080 39.170 0.880 39.610 ;
        RECT 1.780 39.170 3.245 39.610 ;
        RECT 3.480 39.170 4.280 39.610 ;
        RECT 5.180 39.170 6.645 39.610 ;
        RECT 0.080 43.070 1.545 43.510 ;
        RECT 1.780 43.070 2.580 43.510 ;
        RECT 3.480 43.070 4.945 43.510 ;
        RECT 5.180 43.070 5.980 43.510 ;
        RECT 0.080 37.870 1.545 38.310 ;
        RECT 1.780 37.870 2.580 38.310 ;
        RECT 3.480 37.870 4.945 38.310 ;
        RECT 5.180 37.870 5.980 38.310 ;
        RECT 0.080 44.370 0.880 44.810 ;
        RECT 1.780 44.370 3.245 44.810 ;
        RECT 3.480 44.370 4.280 44.810 ;
        RECT 5.180 44.370 6.645 44.810 ;
        RECT 0.080 40.470 1.545 40.910 ;
        RECT 1.780 40.470 2.580 40.910 ;
        RECT 3.480 40.470 4.945 40.910 ;
        RECT 5.180 40.470 5.980 40.910 ;
        RECT 0.080 46.970 1.545 47.410 ;
        RECT 1.780 46.970 2.580 47.410 ;
        RECT 3.480 46.970 4.945 47.410 ;
        RECT 5.180 46.970 5.980 47.410 ;
        RECT 0.080 36.570 0.880 37.010 ;
        RECT 1.780 36.570 3.245 37.010 ;
        RECT 3.480 36.570 4.280 37.010 ;
        RECT 5.180 36.570 6.645 37.010 ;
        RECT 0.080 26.170 1.545 26.610 ;
        RECT 1.780 26.170 2.580 26.610 ;
        RECT 3.480 26.170 4.945 26.610 ;
        RECT 5.180 26.170 5.980 26.610 ;
        RECT 0.080 28.770 1.545 29.210 ;
        RECT 1.780 28.770 2.580 29.210 ;
        RECT 3.480 28.770 4.945 29.210 ;
        RECT 5.180 28.770 5.980 29.210 ;
        RECT 0.080 31.370 1.545 31.810 ;
        RECT 1.780 31.370 2.580 31.810 ;
        RECT 3.480 31.370 4.945 31.810 ;
        RECT 5.180 31.370 5.980 31.810 ;
        RECT 0.080 30.070 0.880 30.510 ;
        RECT 1.780 30.070 3.245 30.510 ;
        RECT 3.480 30.070 4.280 30.510 ;
        RECT 5.180 30.070 6.645 30.510 ;
        RECT 0.080 35.270 1.545 35.710 ;
        RECT 1.780 35.270 2.580 35.710 ;
        RECT 3.480 35.270 4.945 35.710 ;
        RECT 5.180 35.270 5.980 35.710 ;
        RECT 0.080 32.670 0.880 33.110 ;
        RECT 1.780 32.670 3.245 33.110 ;
        RECT 3.480 32.670 4.280 33.110 ;
        RECT 5.180 32.670 6.645 33.110 ;
        RECT 0.080 27.470 0.880 27.910 ;
        RECT 1.780 27.470 3.245 27.910 ;
        RECT 3.480 27.470 4.280 27.910 ;
        RECT 5.180 27.470 6.645 27.910 ;
        RECT 0.080 24.870 0.880 25.310 ;
        RECT 1.780 24.870 3.245 25.310 ;
        RECT 3.480 24.870 4.280 25.310 ;
        RECT 5.180 24.870 6.645 25.310 ;
        RECT 6.880 31.370 8.345 31.810 ;
        RECT 8.580 31.370 9.380 31.810 ;
        RECT 10.280 31.370 11.745 31.810 ;
        RECT 11.980 31.370 12.780 31.810 ;
        RECT 6.880 32.670 7.680 33.110 ;
        RECT 8.580 32.670 10.045 33.110 ;
        RECT 10.280 32.670 11.080 33.110 ;
        RECT 11.980 32.670 13.445 33.110 ;
        RECT 6.880 26.170 8.345 26.610 ;
        RECT 8.580 26.170 9.380 26.610 ;
        RECT 10.280 26.170 11.745 26.610 ;
        RECT 11.980 26.170 12.780 26.610 ;
        RECT 6.880 35.270 8.345 35.710 ;
        RECT 8.580 35.270 9.380 35.710 ;
        RECT 10.280 35.270 11.745 35.710 ;
        RECT 11.980 35.270 12.780 35.710 ;
        RECT 6.880 27.470 7.680 27.910 ;
        RECT 8.580 27.470 10.045 27.910 ;
        RECT 10.280 27.470 11.080 27.910 ;
        RECT 11.980 27.470 13.445 27.910 ;
        RECT 6.880 30.070 7.680 30.510 ;
        RECT 8.580 30.070 10.045 30.510 ;
        RECT 10.280 30.070 11.080 30.510 ;
        RECT 11.980 30.070 13.445 30.510 ;
        RECT 6.880 28.770 8.345 29.210 ;
        RECT 8.580 28.770 9.380 29.210 ;
        RECT 10.280 28.770 11.745 29.210 ;
        RECT 11.980 28.770 12.780 29.210 ;
        RECT 6.880 24.870 7.680 25.310 ;
        RECT 8.580 24.870 10.045 25.310 ;
        RECT 10.280 24.870 11.080 25.310 ;
        RECT 11.980 24.870 13.445 25.310 ;
        RECT 0.080 11.870 1.545 12.310 ;
        RECT 1.780 11.870 2.580 12.310 ;
        RECT 3.480 11.870 4.945 12.310 ;
        RECT 5.180 11.870 5.980 12.310 ;
        RECT 6.880 11.870 8.345 12.310 ;
        RECT 8.580 11.870 9.380 12.310 ;
        RECT 10.280 11.870 11.745 12.310 ;
        RECT 11.980 11.870 12.780 12.310 ;
        RECT 6.880 20.970 7.680 21.410 ;
        RECT 8.580 20.970 10.045 21.410 ;
        RECT 10.280 20.970 11.080 21.410 ;
        RECT 11.980 20.970 13.445 21.410 ;
        RECT 6.880 23.570 8.345 24.010 ;
        RECT 8.580 23.570 9.380 24.010 ;
        RECT 10.280 23.570 11.745 24.010 ;
        RECT 11.980 23.570 12.780 24.010 ;
        RECT 6.880 13.170 7.680 13.610 ;
        RECT 8.580 13.170 10.045 13.610 ;
        RECT 10.280 13.170 11.080 13.610 ;
        RECT 11.980 13.170 13.445 13.610 ;
        RECT 6.880 14.470 8.345 14.910 ;
        RECT 8.580 14.470 9.380 14.910 ;
        RECT 10.280 14.470 11.745 14.910 ;
        RECT 11.980 14.470 12.780 14.910 ;
        RECT 6.880 15.770 7.680 16.210 ;
        RECT 8.580 15.770 10.045 16.210 ;
        RECT 10.280 15.770 11.080 16.210 ;
        RECT 11.980 15.770 13.445 16.210 ;
        RECT 6.880 17.070 8.345 17.510 ;
        RECT 8.580 17.070 9.380 17.510 ;
        RECT 10.280 17.070 11.745 17.510 ;
        RECT 11.980 17.070 12.780 17.510 ;
        RECT 6.880 18.370 7.680 18.810 ;
        RECT 8.580 18.370 10.045 18.810 ;
        RECT 10.280 18.370 11.080 18.810 ;
        RECT 11.980 18.370 13.445 18.810 ;
        RECT 6.880 19.670 8.345 20.110 ;
        RECT 8.580 19.670 9.380 20.110 ;
        RECT 10.280 19.670 11.745 20.110 ;
        RECT 11.980 19.670 12.780 20.110 ;
        RECT 0.080 23.570 1.545 24.010 ;
        RECT 1.780 23.570 2.580 24.010 ;
        RECT 3.480 23.570 4.945 24.010 ;
        RECT 5.180 23.570 5.980 24.010 ;
        RECT 0.080 17.070 1.545 17.510 ;
        RECT 1.780 17.070 2.580 17.510 ;
        RECT 3.480 17.070 4.945 17.510 ;
        RECT 5.180 17.070 5.980 17.510 ;
        RECT 0.080 14.470 1.545 14.910 ;
        RECT 1.780 14.470 2.580 14.910 ;
        RECT 3.480 14.470 4.945 14.910 ;
        RECT 5.180 14.470 5.980 14.910 ;
        RECT 0.080 18.370 0.880 18.810 ;
        RECT 1.780 18.370 3.245 18.810 ;
        RECT 3.480 18.370 4.280 18.810 ;
        RECT 5.180 18.370 6.645 18.810 ;
        RECT 0.080 13.170 0.880 13.610 ;
        RECT 1.780 13.170 3.245 13.610 ;
        RECT 3.480 13.170 4.280 13.610 ;
        RECT 5.180 13.170 6.645 13.610 ;
        RECT 0.080 19.670 1.545 20.110 ;
        RECT 1.780 19.670 2.580 20.110 ;
        RECT 3.480 19.670 4.945 20.110 ;
        RECT 5.180 19.670 5.980 20.110 ;
        RECT 0.080 15.770 0.880 16.210 ;
        RECT 1.780 15.770 3.245 16.210 ;
        RECT 3.480 15.770 4.280 16.210 ;
        RECT 5.180 15.770 6.645 16.210 ;
        RECT 0.080 20.970 0.880 21.410 ;
        RECT 1.780 20.970 3.245 21.410 ;
        RECT 3.480 20.970 4.280 21.410 ;
        RECT 5.180 20.970 6.645 21.410 ;
        RECT 3.480 0.170 4.945 0.610 ;
        RECT 5.180 0.170 5.980 0.610 ;
        RECT 0.080 1.470 0.880 1.910 ;
        RECT 1.780 1.470 3.245 1.910 ;
        RECT 3.480 1.470 4.280 1.910 ;
        RECT 5.180 1.470 6.645 1.910 ;
        RECT 0.080 2.770 1.545 3.210 ;
        RECT 1.780 2.770 2.580 3.210 ;
        RECT 3.480 2.770 4.945 3.210 ;
        RECT 5.180 2.770 5.980 3.210 ;
        RECT 0.080 4.070 0.880 4.510 ;
        RECT 1.780 4.070 3.245 4.510 ;
        RECT 3.480 4.070 4.280 4.510 ;
        RECT 5.180 4.070 6.645 4.510 ;
        RECT 0.080 5.370 1.545 5.810 ;
        RECT 1.780 5.370 2.580 5.810 ;
        RECT 3.480 5.370 4.945 5.810 ;
        RECT 5.180 5.370 5.980 5.810 ;
        RECT 0.080 6.670 0.880 7.110 ;
        RECT 1.780 6.670 3.245 7.110 ;
        RECT 3.480 6.670 4.280 7.110 ;
        RECT 5.180 6.670 6.645 7.110 ;
        RECT 0.080 7.970 1.545 8.410 ;
        RECT 1.780 7.970 2.580 8.410 ;
        RECT 3.480 7.970 4.945 8.410 ;
        RECT 5.180 7.970 5.980 8.410 ;
        RECT 0.080 9.270 0.880 9.710 ;
        RECT 1.780 9.270 3.245 9.710 ;
        RECT 3.480 9.270 4.280 9.710 ;
        RECT 5.180 9.270 6.645 9.710 ;
        RECT 0.080 0.170 1.545 0.610 ;
        RECT 1.780 0.170 2.580 0.610 ;
        RECT 10.280 9.270 11.080 9.710 ;
        RECT 11.980 9.270 13.445 9.710 ;
        RECT 6.880 0.170 8.345 0.610 ;
        RECT 8.580 0.170 9.380 0.610 ;
        RECT 10.280 0.170 11.745 0.610 ;
        RECT 11.980 0.170 12.780 0.610 ;
        RECT 6.880 5.370 8.345 5.810 ;
        RECT 8.580 5.370 9.380 5.810 ;
        RECT 10.280 5.370 11.745 5.810 ;
        RECT 11.980 5.370 12.780 5.810 ;
        RECT 6.880 2.770 8.345 3.210 ;
        RECT 8.580 2.770 9.380 3.210 ;
        RECT 10.280 2.770 11.745 3.210 ;
        RECT 11.980 2.770 12.780 3.210 ;
        RECT 6.880 6.670 7.680 7.110 ;
        RECT 8.580 6.670 10.045 7.110 ;
        RECT 10.280 6.670 11.080 7.110 ;
        RECT 11.980 6.670 13.445 7.110 ;
        RECT 6.880 1.470 7.680 1.910 ;
        RECT 8.580 1.470 10.045 1.910 ;
        RECT 10.280 1.470 11.080 1.910 ;
        RECT 11.980 1.470 13.445 1.910 ;
        RECT 6.880 7.970 8.345 8.410 ;
        RECT 8.580 7.970 9.380 8.410 ;
        RECT 10.280 7.970 11.745 8.410 ;
        RECT 11.980 7.970 12.780 8.410 ;
        RECT 6.880 4.070 7.680 4.510 ;
        RECT 8.580 4.070 10.045 4.510 ;
        RECT 10.280 4.070 11.080 4.510 ;
        RECT 11.980 4.070 13.445 4.510 ;
        RECT 6.880 9.270 7.680 9.710 ;
        RECT 8.580 9.270 10.045 9.710 ;
        RECT 13.680 11.870 15.145 12.310 ;
        RECT 15.380 11.870 16.180 12.310 ;
        RECT 17.080 11.870 18.545 12.310 ;
        RECT 18.780 11.870 19.580 12.310 ;
        RECT 20.480 11.870 21.945 12.310 ;
        RECT 22.180 11.870 22.980 12.310 ;
        RECT 23.880 11.870 25.345 12.310 ;
        RECT 25.580 11.870 26.380 12.310 ;
        RECT 20.480 23.570 21.945 24.010 ;
        RECT 22.180 23.570 22.980 24.010 ;
        RECT 23.880 23.570 25.345 24.010 ;
        RECT 25.580 23.570 26.380 24.010 ;
        RECT 20.480 13.170 21.280 13.610 ;
        RECT 22.180 13.170 23.645 13.610 ;
        RECT 23.880 13.170 24.680 13.610 ;
        RECT 25.580 13.170 27.045 13.610 ;
        RECT 20.480 14.470 21.945 14.910 ;
        RECT 22.180 14.470 22.980 14.910 ;
        RECT 23.880 14.470 25.345 14.910 ;
        RECT 25.580 14.470 26.380 14.910 ;
        RECT 20.480 15.770 21.280 16.210 ;
        RECT 22.180 15.770 23.645 16.210 ;
        RECT 23.880 15.770 24.680 16.210 ;
        RECT 25.580 15.770 27.045 16.210 ;
        RECT 20.480 17.070 21.945 17.510 ;
        RECT 22.180 17.070 22.980 17.510 ;
        RECT 23.880 17.070 25.345 17.510 ;
        RECT 25.580 17.070 26.380 17.510 ;
        RECT 20.480 18.370 21.280 18.810 ;
        RECT 22.180 18.370 23.645 18.810 ;
        RECT 23.880 18.370 24.680 18.810 ;
        RECT 25.580 18.370 27.045 18.810 ;
        RECT 20.480 19.670 21.945 20.110 ;
        RECT 22.180 19.670 22.980 20.110 ;
        RECT 23.880 19.670 25.345 20.110 ;
        RECT 25.580 19.670 26.380 20.110 ;
        RECT 20.480 20.970 21.280 21.410 ;
        RECT 22.180 20.970 23.645 21.410 ;
        RECT 23.880 20.970 24.680 21.410 ;
        RECT 25.580 20.970 27.045 21.410 ;
        RECT 13.680 17.070 15.145 17.510 ;
        RECT 15.380 17.070 16.180 17.510 ;
        RECT 17.080 17.070 18.545 17.510 ;
        RECT 18.780 17.070 19.580 17.510 ;
        RECT 13.680 14.470 15.145 14.910 ;
        RECT 15.380 14.470 16.180 14.910 ;
        RECT 17.080 14.470 18.545 14.910 ;
        RECT 18.780 14.470 19.580 14.910 ;
        RECT 13.680 18.370 14.480 18.810 ;
        RECT 15.380 18.370 16.845 18.810 ;
        RECT 17.080 18.370 17.880 18.810 ;
        RECT 18.780 18.370 20.245 18.810 ;
        RECT 13.680 13.170 14.480 13.610 ;
        RECT 15.380 13.170 16.845 13.610 ;
        RECT 17.080 13.170 17.880 13.610 ;
        RECT 18.780 13.170 20.245 13.610 ;
        RECT 13.680 19.670 15.145 20.110 ;
        RECT 15.380 19.670 16.180 20.110 ;
        RECT 17.080 19.670 18.545 20.110 ;
        RECT 18.780 19.670 19.580 20.110 ;
        RECT 13.680 15.770 14.480 16.210 ;
        RECT 15.380 15.770 16.845 16.210 ;
        RECT 17.080 15.770 17.880 16.210 ;
        RECT 18.780 15.770 20.245 16.210 ;
        RECT 13.680 20.970 14.480 21.410 ;
        RECT 15.380 20.970 16.845 21.410 ;
        RECT 17.080 20.970 17.880 21.410 ;
        RECT 18.780 20.970 20.245 21.410 ;
        RECT 13.680 23.570 15.145 24.010 ;
        RECT 15.380 23.570 16.180 24.010 ;
        RECT 17.080 23.570 18.545 24.010 ;
        RECT 18.780 23.570 19.580 24.010 ;
        RECT 17.080 5.370 18.545 5.810 ;
        RECT 18.780 5.370 19.580 5.810 ;
        RECT 17.080 0.170 18.545 0.610 ;
        RECT 18.780 0.170 19.580 0.610 ;
        RECT 13.680 1.470 14.480 1.910 ;
        RECT 15.380 1.470 16.845 1.910 ;
        RECT 13.680 4.070 14.480 4.510 ;
        RECT 15.380 4.070 16.845 4.510 ;
        RECT 17.080 4.070 17.880 4.510 ;
        RECT 18.780 4.070 20.245 4.510 ;
        RECT 17.080 1.470 17.880 1.910 ;
        RECT 18.780 1.470 20.245 1.910 ;
        RECT 13.680 2.770 15.145 3.210 ;
        RECT 15.380 2.770 16.180 3.210 ;
        RECT 13.680 6.670 14.480 7.110 ;
        RECT 15.380 6.670 16.845 7.110 ;
        RECT 17.080 6.670 17.880 7.110 ;
        RECT 18.780 6.670 20.245 7.110 ;
        RECT 13.680 9.270 14.480 9.710 ;
        RECT 15.380 9.270 16.845 9.710 ;
        RECT 17.080 9.270 17.880 9.710 ;
        RECT 18.780 9.270 20.245 9.710 ;
        RECT 17.080 2.770 18.545 3.210 ;
        RECT 18.780 2.770 19.580 3.210 ;
        RECT 13.680 7.970 15.145 8.410 ;
        RECT 15.380 7.970 16.180 8.410 ;
        RECT 17.080 7.970 18.545 8.410 ;
        RECT 18.780 7.970 19.580 8.410 ;
        RECT 13.680 5.370 15.145 5.810 ;
        RECT 15.380 5.370 16.180 5.810 ;
        RECT 13.680 0.170 15.145 0.610 ;
        RECT 15.380 0.170 16.180 0.610 ;
        RECT 23.880 6.670 24.680 7.110 ;
        RECT 25.580 6.670 27.045 7.110 ;
        RECT 20.480 4.070 21.280 4.510 ;
        RECT 22.180 4.070 23.645 4.510 ;
        RECT 23.880 4.070 24.680 4.510 ;
        RECT 25.580 4.070 27.045 4.510 ;
        RECT 20.480 5.370 21.945 5.810 ;
        RECT 22.180 5.370 22.980 5.810 ;
        RECT 23.880 5.370 25.345 5.810 ;
        RECT 25.580 5.370 26.380 5.810 ;
        RECT 20.480 0.170 21.945 0.610 ;
        RECT 22.180 0.170 22.980 0.610 ;
        RECT 23.880 0.170 25.345 0.610 ;
        RECT 25.580 0.170 26.380 0.610 ;
        RECT 20.480 7.970 21.945 8.410 ;
        RECT 22.180 7.970 22.980 8.410 ;
        RECT 23.880 7.970 25.345 8.410 ;
        RECT 25.580 7.970 26.380 8.410 ;
        RECT 20.480 9.270 21.280 9.710 ;
        RECT 22.180 9.270 23.645 9.710 ;
        RECT 23.880 9.270 24.680 9.710 ;
        RECT 25.580 9.270 27.045 9.710 ;
        RECT 20.480 2.770 21.945 3.210 ;
        RECT 22.180 2.770 22.980 3.210 ;
        RECT 23.880 2.770 25.345 3.210 ;
        RECT 25.580 2.770 26.380 3.210 ;
        RECT 20.480 1.470 21.280 1.910 ;
        RECT 22.180 1.470 23.645 1.910 ;
        RECT 23.880 1.470 24.680 1.910 ;
        RECT 25.580 1.470 27.045 1.910 ;
        RECT 20.480 6.670 21.280 7.110 ;
        RECT 22.180 6.670 23.645 7.110 ;
        RECT 47.680 36.570 48.480 37.010 ;
        RECT 49.380 36.570 50.845 37.010 ;
        RECT 51.080 36.570 51.880 37.010 ;
        RECT 52.780 36.570 54.245 37.010 ;
        RECT 47.680 37.870 49.145 38.310 ;
        RECT 49.380 37.870 50.180 38.310 ;
        RECT 51.080 37.870 52.545 38.310 ;
        RECT 52.780 37.870 53.580 38.310 ;
        RECT 47.680 39.170 48.480 39.610 ;
        RECT 49.380 39.170 50.845 39.610 ;
        RECT 51.080 39.170 51.880 39.610 ;
        RECT 52.780 39.170 54.245 39.610 ;
        RECT 47.680 40.470 49.145 40.910 ;
        RECT 49.380 40.470 50.180 40.910 ;
        RECT 51.080 40.470 52.545 40.910 ;
        RECT 52.780 40.470 53.580 40.910 ;
        RECT 47.680 41.770 48.480 42.210 ;
        RECT 49.380 41.770 50.845 42.210 ;
        RECT 51.080 41.770 51.880 42.210 ;
        RECT 52.780 41.770 54.245 42.210 ;
        RECT 47.680 43.070 49.145 43.510 ;
        RECT 49.380 43.070 50.180 43.510 ;
        RECT 51.080 43.070 52.545 43.510 ;
        RECT 52.780 43.070 53.580 43.510 ;
        RECT 47.680 44.370 48.480 44.810 ;
        RECT 49.380 44.370 50.845 44.810 ;
        RECT 51.080 44.370 51.880 44.810 ;
        RECT 52.780 44.370 54.245 44.810 ;
        RECT 47.680 46.970 49.145 47.410 ;
        RECT 49.380 46.970 50.180 47.410 ;
        RECT 51.080 46.970 52.545 47.410 ;
        RECT 52.780 46.970 53.580 47.410 ;
        RECT 40.880 41.770 41.680 42.210 ;
        RECT 42.580 41.770 44.045 42.210 ;
        RECT 44.280 41.770 45.080 42.210 ;
        RECT 45.980 41.770 47.445 42.210 ;
        RECT 40.880 39.170 41.680 39.610 ;
        RECT 42.580 39.170 44.045 39.610 ;
        RECT 44.280 39.170 45.080 39.610 ;
        RECT 45.980 39.170 47.445 39.610 ;
        RECT 40.880 43.070 42.345 43.510 ;
        RECT 42.580 43.070 43.380 43.510 ;
        RECT 44.280 43.070 45.745 43.510 ;
        RECT 45.980 43.070 46.780 43.510 ;
        RECT 40.880 37.870 42.345 38.310 ;
        RECT 42.580 37.870 43.380 38.310 ;
        RECT 44.280 37.870 45.745 38.310 ;
        RECT 45.980 37.870 46.780 38.310 ;
        RECT 40.880 44.370 41.680 44.810 ;
        RECT 42.580 44.370 44.045 44.810 ;
        RECT 44.280 44.370 45.080 44.810 ;
        RECT 45.980 44.370 47.445 44.810 ;
        RECT 40.880 40.470 42.345 40.910 ;
        RECT 42.580 40.470 43.380 40.910 ;
        RECT 44.280 40.470 45.745 40.910 ;
        RECT 45.980 40.470 46.780 40.910 ;
        RECT 40.880 46.970 42.345 47.410 ;
        RECT 42.580 46.970 43.380 47.410 ;
        RECT 44.280 46.970 45.745 47.410 ;
        RECT 45.980 46.970 46.780 47.410 ;
        RECT 40.880 36.570 41.680 37.010 ;
        RECT 42.580 36.570 44.045 37.010 ;
        RECT 44.280 36.570 45.080 37.010 ;
        RECT 45.980 36.570 47.445 37.010 ;
        RECT 40.880 24.870 41.680 25.310 ;
        RECT 42.580 24.870 44.045 25.310 ;
        RECT 44.280 24.870 45.080 25.310 ;
        RECT 45.980 24.870 47.445 25.310 ;
        RECT 40.880 26.170 42.345 26.610 ;
        RECT 42.580 26.170 43.380 26.610 ;
        RECT 44.280 26.170 45.745 26.610 ;
        RECT 45.980 26.170 46.780 26.610 ;
        RECT 40.880 27.470 41.680 27.910 ;
        RECT 42.580 27.470 44.045 27.910 ;
        RECT 44.280 27.470 45.080 27.910 ;
        RECT 45.980 27.470 47.445 27.910 ;
        RECT 40.880 28.770 42.345 29.210 ;
        RECT 42.580 28.770 43.380 29.210 ;
        RECT 44.280 28.770 45.745 29.210 ;
        RECT 45.980 28.770 46.780 29.210 ;
        RECT 40.880 30.070 41.680 30.510 ;
        RECT 42.580 30.070 44.045 30.510 ;
        RECT 44.280 30.070 45.080 30.510 ;
        RECT 45.980 30.070 47.445 30.510 ;
        RECT 40.880 31.370 42.345 31.810 ;
        RECT 42.580 31.370 43.380 31.810 ;
        RECT 44.280 31.370 45.745 31.810 ;
        RECT 45.980 31.370 46.780 31.810 ;
        RECT 40.880 32.670 41.680 33.110 ;
        RECT 42.580 32.670 44.045 33.110 ;
        RECT 44.280 32.670 45.080 33.110 ;
        RECT 45.980 32.670 47.445 33.110 ;
        RECT 40.880 35.270 42.345 35.710 ;
        RECT 42.580 35.270 43.380 35.710 ;
        RECT 44.280 35.270 45.745 35.710 ;
        RECT 45.980 35.270 46.780 35.710 ;
        RECT 47.680 24.870 48.480 25.310 ;
        RECT 49.380 24.870 50.845 25.310 ;
        RECT 51.080 24.870 51.880 25.310 ;
        RECT 52.780 24.870 54.245 25.310 ;
        RECT 47.680 30.070 48.480 30.510 ;
        RECT 49.380 30.070 50.845 30.510 ;
        RECT 51.080 30.070 51.880 30.510 ;
        RECT 52.780 30.070 54.245 30.510 ;
        RECT 47.680 27.470 48.480 27.910 ;
        RECT 49.380 27.470 50.845 27.910 ;
        RECT 51.080 27.470 51.880 27.910 ;
        RECT 52.780 27.470 54.245 27.910 ;
        RECT 47.680 31.370 49.145 31.810 ;
        RECT 49.380 31.370 50.180 31.810 ;
        RECT 51.080 31.370 52.545 31.810 ;
        RECT 52.780 31.370 53.580 31.810 ;
        RECT 47.680 26.170 49.145 26.610 ;
        RECT 49.380 26.170 50.180 26.610 ;
        RECT 51.080 26.170 52.545 26.610 ;
        RECT 52.780 26.170 53.580 26.610 ;
        RECT 47.680 32.670 48.480 33.110 ;
        RECT 49.380 32.670 50.845 33.110 ;
        RECT 51.080 32.670 51.880 33.110 ;
        RECT 52.780 32.670 54.245 33.110 ;
        RECT 47.680 28.770 49.145 29.210 ;
        RECT 49.380 28.770 50.180 29.210 ;
        RECT 51.080 28.770 52.545 29.210 ;
        RECT 52.780 28.770 53.580 29.210 ;
        RECT 47.680 35.270 49.145 35.710 ;
        RECT 49.380 35.270 50.180 35.710 ;
        RECT 51.080 35.270 52.545 35.710 ;
        RECT 52.780 35.270 53.580 35.710 ;
        RECT 34.080 36.570 34.880 37.010 ;
        RECT 35.780 36.570 37.245 37.010 ;
        RECT 37.480 36.570 38.280 37.010 ;
        RECT 39.180 36.570 40.645 37.010 ;
        RECT 34.080 37.870 35.545 38.310 ;
        RECT 35.780 37.870 36.580 38.310 ;
        RECT 37.480 37.870 38.945 38.310 ;
        RECT 39.180 37.870 39.980 38.310 ;
        RECT 34.080 39.170 34.880 39.610 ;
        RECT 35.780 39.170 37.245 39.610 ;
        RECT 37.480 39.170 38.280 39.610 ;
        RECT 39.180 39.170 40.645 39.610 ;
        RECT 34.080 40.470 35.545 40.910 ;
        RECT 35.780 40.470 36.580 40.910 ;
        RECT 37.480 40.470 38.945 40.910 ;
        RECT 39.180 40.470 39.980 40.910 ;
        RECT 34.080 41.770 34.880 42.210 ;
        RECT 35.780 41.770 37.245 42.210 ;
        RECT 37.480 41.770 38.280 42.210 ;
        RECT 39.180 41.770 40.645 42.210 ;
        RECT 34.080 43.070 35.545 43.510 ;
        RECT 35.780 43.070 36.580 43.510 ;
        RECT 37.480 43.070 38.945 43.510 ;
        RECT 39.180 43.070 39.980 43.510 ;
        RECT 34.080 44.370 34.880 44.810 ;
        RECT 35.780 44.370 37.245 44.810 ;
        RECT 37.480 44.370 38.280 44.810 ;
        RECT 39.180 44.370 40.645 44.810 ;
        RECT 34.080 46.970 35.545 47.410 ;
        RECT 35.780 46.970 36.580 47.410 ;
        RECT 37.480 46.970 38.945 47.410 ;
        RECT 39.180 46.970 39.980 47.410 ;
        RECT 27.280 41.770 28.080 42.210 ;
        RECT 28.980 41.770 30.445 42.210 ;
        RECT 30.680 41.770 31.480 42.210 ;
        RECT 32.380 41.770 33.845 42.210 ;
        RECT 27.280 39.170 28.080 39.610 ;
        RECT 28.980 39.170 30.445 39.610 ;
        RECT 30.680 39.170 31.480 39.610 ;
        RECT 32.380 39.170 33.845 39.610 ;
        RECT 27.280 43.070 28.745 43.510 ;
        RECT 28.980 43.070 29.780 43.510 ;
        RECT 30.680 43.070 32.145 43.510 ;
        RECT 32.380 43.070 33.180 43.510 ;
        RECT 27.280 37.870 28.745 38.310 ;
        RECT 28.980 37.870 29.780 38.310 ;
        RECT 30.680 37.870 32.145 38.310 ;
        RECT 32.380 37.870 33.180 38.310 ;
        RECT 27.280 44.370 28.080 44.810 ;
        RECT 28.980 44.370 30.445 44.810 ;
        RECT 30.680 44.370 31.480 44.810 ;
        RECT 32.380 44.370 33.845 44.810 ;
        RECT 27.280 40.470 28.745 40.910 ;
        RECT 28.980 40.470 29.780 40.910 ;
        RECT 30.680 40.470 32.145 40.910 ;
        RECT 32.380 40.470 33.180 40.910 ;
        RECT 27.280 46.970 28.745 47.410 ;
        RECT 28.980 46.970 29.780 47.410 ;
        RECT 30.680 46.970 32.145 47.410 ;
        RECT 32.380 46.970 33.180 47.410 ;
        RECT 27.280 36.570 28.080 37.010 ;
        RECT 28.980 36.570 30.445 37.010 ;
        RECT 30.680 36.570 31.480 37.010 ;
        RECT 32.380 36.570 33.845 37.010 ;
        RECT 27.280 26.170 28.745 26.610 ;
        RECT 28.980 26.170 29.780 26.610 ;
        RECT 30.680 26.170 32.145 26.610 ;
        RECT 32.380 26.170 33.180 26.610 ;
        RECT 27.280 28.770 28.745 29.210 ;
        RECT 28.980 28.770 29.780 29.210 ;
        RECT 30.680 28.770 32.145 29.210 ;
        RECT 32.380 28.770 33.180 29.210 ;
        RECT 27.280 31.370 28.745 31.810 ;
        RECT 28.980 31.370 29.780 31.810 ;
        RECT 30.680 31.370 32.145 31.810 ;
        RECT 32.380 31.370 33.180 31.810 ;
        RECT 27.280 30.070 28.080 30.510 ;
        RECT 28.980 30.070 30.445 30.510 ;
        RECT 30.680 30.070 31.480 30.510 ;
        RECT 32.380 30.070 33.845 30.510 ;
        RECT 27.280 35.270 28.745 35.710 ;
        RECT 28.980 35.270 29.780 35.710 ;
        RECT 30.680 35.270 32.145 35.710 ;
        RECT 32.380 35.270 33.180 35.710 ;
        RECT 27.280 32.670 28.080 33.110 ;
        RECT 28.980 32.670 30.445 33.110 ;
        RECT 30.680 32.670 31.480 33.110 ;
        RECT 32.380 32.670 33.845 33.110 ;
        RECT 27.280 27.470 28.080 27.910 ;
        RECT 28.980 27.470 30.445 27.910 ;
        RECT 30.680 27.470 31.480 27.910 ;
        RECT 32.380 27.470 33.845 27.910 ;
        RECT 27.280 24.870 28.080 25.310 ;
        RECT 28.980 24.870 30.445 25.310 ;
        RECT 30.680 24.870 31.480 25.310 ;
        RECT 32.380 24.870 33.845 25.310 ;
        RECT 34.080 31.370 35.545 31.810 ;
        RECT 35.780 31.370 36.580 31.810 ;
        RECT 37.480 31.370 38.945 31.810 ;
        RECT 39.180 31.370 39.980 31.810 ;
        RECT 34.080 32.670 34.880 33.110 ;
        RECT 35.780 32.670 37.245 33.110 ;
        RECT 37.480 32.670 38.280 33.110 ;
        RECT 39.180 32.670 40.645 33.110 ;
        RECT 34.080 26.170 35.545 26.610 ;
        RECT 35.780 26.170 36.580 26.610 ;
        RECT 37.480 26.170 38.945 26.610 ;
        RECT 39.180 26.170 39.980 26.610 ;
        RECT 34.080 35.270 35.545 35.710 ;
        RECT 35.780 35.270 36.580 35.710 ;
        RECT 37.480 35.270 38.945 35.710 ;
        RECT 39.180 35.270 39.980 35.710 ;
        RECT 34.080 27.470 34.880 27.910 ;
        RECT 35.780 27.470 37.245 27.910 ;
        RECT 37.480 27.470 38.280 27.910 ;
        RECT 39.180 27.470 40.645 27.910 ;
        RECT 34.080 30.070 34.880 30.510 ;
        RECT 35.780 30.070 37.245 30.510 ;
        RECT 37.480 30.070 38.280 30.510 ;
        RECT 39.180 30.070 40.645 30.510 ;
        RECT 34.080 28.770 35.545 29.210 ;
        RECT 35.780 28.770 36.580 29.210 ;
        RECT 37.480 28.770 38.945 29.210 ;
        RECT 39.180 28.770 39.980 29.210 ;
        RECT 34.080 24.870 34.880 25.310 ;
        RECT 35.780 24.870 37.245 25.310 ;
        RECT 37.480 24.870 38.280 25.310 ;
        RECT 39.180 24.870 40.645 25.310 ;
        RECT 27.280 11.870 28.745 12.310 ;
        RECT 28.980 11.870 29.780 12.310 ;
        RECT 30.680 11.870 32.145 12.310 ;
        RECT 32.380 11.870 33.180 12.310 ;
        RECT 34.080 11.870 35.545 12.310 ;
        RECT 35.780 11.870 36.580 12.310 ;
        RECT 37.480 11.870 38.945 12.310 ;
        RECT 39.180 11.870 39.980 12.310 ;
        RECT 34.080 14.470 35.545 14.910 ;
        RECT 35.780 14.470 36.580 14.910 ;
        RECT 37.480 14.470 38.945 14.910 ;
        RECT 39.180 14.470 39.980 14.910 ;
        RECT 34.080 19.670 35.545 20.110 ;
        RECT 35.780 19.670 36.580 20.110 ;
        RECT 37.480 19.670 38.945 20.110 ;
        RECT 39.180 19.670 39.980 20.110 ;
        RECT 34.080 23.570 35.545 24.010 ;
        RECT 35.780 23.570 36.580 24.010 ;
        RECT 34.080 17.070 35.545 17.510 ;
        RECT 35.780 17.070 36.580 17.510 ;
        RECT 37.480 17.070 38.945 17.510 ;
        RECT 39.180 17.070 39.980 17.510 ;
        RECT 37.480 23.570 38.945 24.010 ;
        RECT 39.180 23.570 39.980 24.010 ;
        RECT 34.080 20.970 34.880 21.410 ;
        RECT 35.780 20.970 37.245 21.410 ;
        RECT 37.480 20.970 38.280 21.410 ;
        RECT 39.180 20.970 40.645 21.410 ;
        RECT 34.080 15.770 34.880 16.210 ;
        RECT 35.780 15.770 37.245 16.210 ;
        RECT 37.480 15.770 38.280 16.210 ;
        RECT 39.180 15.770 40.645 16.210 ;
        RECT 34.080 13.170 34.880 13.610 ;
        RECT 35.780 13.170 37.245 13.610 ;
        RECT 34.080 18.370 34.880 18.810 ;
        RECT 35.780 18.370 37.245 18.810 ;
        RECT 37.480 18.370 38.280 18.810 ;
        RECT 39.180 18.370 40.645 18.810 ;
        RECT 37.480 13.170 38.280 13.610 ;
        RECT 39.180 13.170 40.645 13.610 ;
        RECT 30.680 20.970 31.480 21.410 ;
        RECT 32.380 20.970 33.845 21.410 ;
        RECT 27.280 19.670 28.745 20.110 ;
        RECT 28.980 19.670 29.780 20.110 ;
        RECT 27.280 17.070 28.745 17.510 ;
        RECT 28.980 17.070 29.780 17.510 ;
        RECT 27.280 13.170 28.080 13.610 ;
        RECT 28.980 13.170 30.445 13.610 ;
        RECT 30.680 13.170 31.480 13.610 ;
        RECT 32.380 13.170 33.845 13.610 ;
        RECT 27.280 15.770 28.080 16.210 ;
        RECT 28.980 15.770 30.445 16.210 ;
        RECT 30.680 15.770 31.480 16.210 ;
        RECT 32.380 15.770 33.845 16.210 ;
        RECT 30.680 17.070 32.145 17.510 ;
        RECT 32.380 17.070 33.180 17.510 ;
        RECT 30.680 19.670 32.145 20.110 ;
        RECT 32.380 19.670 33.180 20.110 ;
        RECT 27.280 14.470 28.745 14.910 ;
        RECT 28.980 14.470 29.780 14.910 ;
        RECT 27.280 18.370 28.080 18.810 ;
        RECT 28.980 18.370 30.445 18.810 ;
        RECT 30.680 18.370 31.480 18.810 ;
        RECT 32.380 18.370 33.845 18.810 ;
        RECT 30.680 14.470 32.145 14.910 ;
        RECT 32.380 14.470 33.180 14.910 ;
        RECT 30.680 23.570 32.145 24.010 ;
        RECT 32.380 23.570 33.180 24.010 ;
        RECT 27.280 20.970 28.080 21.410 ;
        RECT 28.980 20.970 30.445 21.410 ;
        RECT 27.280 23.570 28.745 24.010 ;
        RECT 28.980 23.570 29.780 24.010 ;
        RECT 27.280 5.370 28.745 5.810 ;
        RECT 28.980 5.370 29.780 5.810 ;
        RECT 27.280 4.070 28.080 4.510 ;
        RECT 28.980 4.070 30.445 4.510 ;
        RECT 30.680 6.670 31.480 7.110 ;
        RECT 32.380 6.670 33.845 7.110 ;
        RECT 27.280 9.270 28.080 9.710 ;
        RECT 28.980 9.270 30.445 9.710 ;
        RECT 30.680 9.270 31.480 9.710 ;
        RECT 32.380 9.270 33.845 9.710 ;
        RECT 27.280 0.170 28.745 0.610 ;
        RECT 28.980 0.170 29.780 0.610 ;
        RECT 30.680 0.170 32.145 0.610 ;
        RECT 32.380 0.170 33.180 0.610 ;
        RECT 30.680 2.770 32.145 3.210 ;
        RECT 32.380 2.770 33.180 3.210 ;
        RECT 30.680 4.070 31.480 4.510 ;
        RECT 32.380 4.070 33.845 4.510 ;
        RECT 27.280 2.770 28.745 3.210 ;
        RECT 28.980 2.770 29.780 3.210 ;
        RECT 27.280 7.970 28.745 8.410 ;
        RECT 28.980 7.970 29.780 8.410 ;
        RECT 27.280 6.670 28.080 7.110 ;
        RECT 28.980 6.670 30.445 7.110 ;
        RECT 30.680 1.470 31.480 1.910 ;
        RECT 32.380 1.470 33.845 1.910 ;
        RECT 30.680 5.370 32.145 5.810 ;
        RECT 32.380 5.370 33.180 5.810 ;
        RECT 27.280 1.470 28.080 1.910 ;
        RECT 28.980 1.470 30.445 1.910 ;
        RECT 30.680 7.970 32.145 8.410 ;
        RECT 32.380 7.970 33.180 8.410 ;
        RECT 34.080 2.770 35.545 3.210 ;
        RECT 35.780 2.770 36.580 3.210 ;
        RECT 37.480 2.770 38.945 3.210 ;
        RECT 39.180 2.770 39.980 3.210 ;
        RECT 37.480 4.070 38.280 4.510 ;
        RECT 39.180 4.070 40.645 4.510 ;
        RECT 34.080 5.370 35.545 5.810 ;
        RECT 35.780 5.370 36.580 5.810 ;
        RECT 34.080 1.470 34.880 1.910 ;
        RECT 35.780 1.470 37.245 1.910 ;
        RECT 34.080 0.170 35.545 0.610 ;
        RECT 35.780 0.170 36.580 0.610 ;
        RECT 37.480 0.170 38.945 0.610 ;
        RECT 39.180 0.170 39.980 0.610 ;
        RECT 37.480 1.470 38.280 1.910 ;
        RECT 39.180 1.470 40.645 1.910 ;
        RECT 37.480 5.370 38.945 5.810 ;
        RECT 39.180 5.370 39.980 5.810 ;
        RECT 34.080 9.270 34.880 9.710 ;
        RECT 35.780 9.270 37.245 9.710 ;
        RECT 37.480 9.270 38.280 9.710 ;
        RECT 39.180 9.270 40.645 9.710 ;
        RECT 34.080 6.670 34.880 7.110 ;
        RECT 35.780 6.670 37.245 7.110 ;
        RECT 34.080 7.970 35.545 8.410 ;
        RECT 35.780 7.970 36.580 8.410 ;
        RECT 37.480 7.970 38.945 8.410 ;
        RECT 39.180 7.970 39.980 8.410 ;
        RECT 37.480 6.670 38.280 7.110 ;
        RECT 39.180 6.670 40.645 7.110 ;
        RECT 34.080 4.070 34.880 4.510 ;
        RECT 35.780 4.070 37.245 4.510 ;
        RECT 40.880 11.870 42.345 12.310 ;
        RECT 42.580 11.870 43.380 12.310 ;
        RECT 44.280 11.870 45.745 12.310 ;
        RECT 45.980 11.870 46.780 12.310 ;
        RECT 47.680 11.870 49.145 12.310 ;
        RECT 49.380 11.870 50.180 12.310 ;
        RECT 51.080 11.870 52.545 12.310 ;
        RECT 52.780 11.870 53.580 12.310 ;
        RECT 47.680 19.670 49.145 20.110 ;
        RECT 49.380 19.670 50.180 20.110 ;
        RECT 51.080 19.670 52.545 20.110 ;
        RECT 52.780 19.670 53.580 20.110 ;
        RECT 47.680 13.170 48.480 13.610 ;
        RECT 49.380 13.170 50.845 13.610 ;
        RECT 51.080 13.170 51.880 13.610 ;
        RECT 52.780 13.170 54.245 13.610 ;
        RECT 47.680 18.370 48.480 18.810 ;
        RECT 49.380 18.370 50.845 18.810 ;
        RECT 51.080 18.370 51.880 18.810 ;
        RECT 52.780 18.370 54.245 18.810 ;
        RECT 47.680 20.970 48.480 21.410 ;
        RECT 49.380 20.970 50.845 21.410 ;
        RECT 51.080 20.970 51.880 21.410 ;
        RECT 52.780 20.970 54.245 21.410 ;
        RECT 47.680 14.470 49.145 14.910 ;
        RECT 49.380 14.470 50.180 14.910 ;
        RECT 51.080 14.470 52.545 14.910 ;
        RECT 52.780 14.470 53.580 14.910 ;
        RECT 47.680 15.770 48.480 16.210 ;
        RECT 49.380 15.770 50.845 16.210 ;
        RECT 51.080 15.770 51.880 16.210 ;
        RECT 52.780 15.770 54.245 16.210 ;
        RECT 47.680 23.570 49.145 24.010 ;
        RECT 49.380 23.570 50.180 24.010 ;
        RECT 51.080 23.570 52.545 24.010 ;
        RECT 52.780 23.570 53.580 24.010 ;
        RECT 47.680 17.070 49.145 17.510 ;
        RECT 49.380 17.070 50.180 17.510 ;
        RECT 51.080 17.070 52.545 17.510 ;
        RECT 52.780 17.070 53.580 17.510 ;
        RECT 44.280 20.970 45.080 21.410 ;
        RECT 45.980 20.970 47.445 21.410 ;
        RECT 44.280 14.470 45.745 14.910 ;
        RECT 45.980 14.470 46.780 14.910 ;
        RECT 40.880 13.170 41.680 13.610 ;
        RECT 42.580 13.170 44.045 13.610 ;
        RECT 44.280 13.170 45.080 13.610 ;
        RECT 45.980 13.170 47.445 13.610 ;
        RECT 40.880 15.770 41.680 16.210 ;
        RECT 42.580 15.770 44.045 16.210 ;
        RECT 40.880 19.670 42.345 20.110 ;
        RECT 42.580 19.670 43.380 20.110 ;
        RECT 40.880 18.370 41.680 18.810 ;
        RECT 42.580 18.370 44.045 18.810 ;
        RECT 40.880 23.570 42.345 24.010 ;
        RECT 42.580 23.570 43.380 24.010 ;
        RECT 44.280 23.570 45.745 24.010 ;
        RECT 45.980 23.570 46.780 24.010 ;
        RECT 44.280 18.370 45.080 18.810 ;
        RECT 45.980 18.370 47.445 18.810 ;
        RECT 44.280 19.670 45.745 20.110 ;
        RECT 45.980 19.670 46.780 20.110 ;
        RECT 40.880 17.070 42.345 17.510 ;
        RECT 42.580 17.070 43.380 17.510 ;
        RECT 44.280 17.070 45.745 17.510 ;
        RECT 45.980 17.070 46.780 17.510 ;
        RECT 44.280 15.770 45.080 16.210 ;
        RECT 45.980 15.770 47.445 16.210 ;
        RECT 40.880 20.970 41.680 21.410 ;
        RECT 42.580 20.970 44.045 21.410 ;
        RECT 40.880 14.470 42.345 14.910 ;
        RECT 42.580 14.470 43.380 14.910 ;
        RECT 44.280 1.470 45.080 1.910 ;
        RECT 45.980 1.470 47.445 1.910 ;
        RECT 40.880 2.770 42.345 3.210 ;
        RECT 42.580 2.770 43.380 3.210 ;
        RECT 44.280 2.770 45.745 3.210 ;
        RECT 45.980 2.770 46.780 3.210 ;
        RECT 40.880 9.270 41.680 9.710 ;
        RECT 42.580 9.270 44.045 9.710 ;
        RECT 44.280 9.270 45.080 9.710 ;
        RECT 45.980 9.270 47.445 9.710 ;
        RECT 40.880 5.370 42.345 5.810 ;
        RECT 42.580 5.370 43.380 5.810 ;
        RECT 44.280 5.370 45.745 5.810 ;
        RECT 45.980 5.370 46.780 5.810 ;
        RECT 40.880 0.170 42.345 0.610 ;
        RECT 42.580 0.170 43.380 0.610 ;
        RECT 44.280 0.170 45.745 0.610 ;
        RECT 45.980 0.170 46.780 0.610 ;
        RECT 40.880 4.070 41.680 4.510 ;
        RECT 42.580 4.070 44.045 4.510 ;
        RECT 44.280 4.070 45.080 4.510 ;
        RECT 45.980 4.070 47.445 4.510 ;
        RECT 40.880 7.970 42.345 8.410 ;
        RECT 42.580 7.970 43.380 8.410 ;
        RECT 44.280 7.970 45.745 8.410 ;
        RECT 45.980 7.970 46.780 8.410 ;
        RECT 40.880 6.670 41.680 7.110 ;
        RECT 42.580 6.670 44.045 7.110 ;
        RECT 44.280 6.670 45.080 7.110 ;
        RECT 45.980 6.670 47.445 7.110 ;
        RECT 40.880 1.470 41.680 1.910 ;
        RECT 42.580 1.470 44.045 1.910 ;
        RECT 51.080 2.770 52.545 3.210 ;
        RECT 52.780 2.770 53.580 3.210 ;
        RECT 47.680 7.970 49.145 8.410 ;
        RECT 49.380 7.970 50.180 8.410 ;
        RECT 51.080 7.970 52.545 8.410 ;
        RECT 52.780 7.970 53.580 8.410 ;
        RECT 47.680 1.470 48.480 1.910 ;
        RECT 49.380 1.470 50.845 1.910 ;
        RECT 51.080 1.470 51.880 1.910 ;
        RECT 52.780 1.470 54.245 1.910 ;
        RECT 47.680 0.170 49.145 0.610 ;
        RECT 49.380 0.170 50.180 0.610 ;
        RECT 51.080 0.170 52.545 0.610 ;
        RECT 52.780 0.170 53.580 0.610 ;
        RECT 47.680 6.670 48.480 7.110 ;
        RECT 49.380 6.670 50.845 7.110 ;
        RECT 51.080 6.670 51.880 7.110 ;
        RECT 52.780 6.670 54.245 7.110 ;
        RECT 47.680 4.070 48.480 4.510 ;
        RECT 49.380 4.070 50.845 4.510 ;
        RECT 51.080 4.070 51.880 4.510 ;
        RECT 52.780 4.070 54.245 4.510 ;
        RECT 47.680 9.270 48.480 9.710 ;
        RECT 49.380 9.270 50.845 9.710 ;
        RECT 51.080 9.270 51.880 9.710 ;
        RECT 52.780 9.270 54.245 9.710 ;
        RECT 47.680 5.370 49.145 5.810 ;
        RECT 49.380 5.370 50.180 5.810 ;
        RECT 51.080 5.370 52.545 5.810 ;
        RECT 52.780 5.370 53.580 5.810 ;
        RECT 47.680 2.770 49.145 3.210 ;
        RECT 49.380 2.770 50.180 3.210 ;
      LAYER met3 ;
        RECT 0.495 48.285 0.550 48.695 ;
        RECT 0.850 48.285 0.905 48.695 ;
        RECT 3.895 48.285 3.950 48.695 ;
        RECT 4.250 48.285 4.305 48.695 ;
        RECT 7.295 48.285 7.350 48.695 ;
        RECT 7.650 48.285 7.705 48.695 ;
        RECT 10.695 48.285 10.750 48.695 ;
        RECT 11.050 48.285 11.105 48.695 ;
        RECT 14.095 48.285 14.150 48.695 ;
        RECT 14.450 48.285 14.505 48.695 ;
        RECT 17.495 48.285 17.550 48.695 ;
        RECT 17.850 48.285 17.905 48.695 ;
        RECT 20.895 48.285 20.950 48.695 ;
        RECT 21.250 48.285 21.305 48.695 ;
        RECT 24.295 48.285 24.350 48.695 ;
        RECT 24.650 48.285 24.705 48.695 ;
        RECT 27.695 48.285 27.750 48.695 ;
        RECT 28.050 48.285 28.105 48.695 ;
        RECT 31.095 48.285 31.150 48.695 ;
        RECT 31.450 48.285 31.505 48.695 ;
        RECT 34.495 48.285 34.550 48.695 ;
        RECT 34.850 48.285 34.905 48.695 ;
        RECT 37.895 48.285 37.950 48.695 ;
        RECT 38.250 48.285 38.305 48.695 ;
        RECT 41.295 48.285 41.350 48.695 ;
        RECT 41.650 48.285 41.705 48.695 ;
        RECT 44.695 48.285 44.750 48.695 ;
        RECT 45.050 48.285 45.105 48.695 ;
        RECT 48.095 48.285 48.150 48.695 ;
        RECT 48.450 48.285 48.505 48.695 ;
        RECT 51.495 48.285 51.550 48.695 ;
        RECT 51.850 48.285 51.905 48.695 ;
        RECT 2.860 48.240 3.400 48.740 ;
        RECT 6.260 48.240 6.800 48.740 ;
        RECT 9.660 48.240 10.200 48.740 ;
        RECT 13.060 48.240 13.600 48.740 ;
        RECT 16.460 48.240 17.000 48.740 ;
        RECT 19.860 48.240 20.400 48.740 ;
        RECT 23.260 48.240 23.800 48.740 ;
        RECT 26.660 48.240 27.200 48.740 ;
        RECT 30.060 48.240 30.600 48.740 ;
        RECT 33.460 48.240 34.000 48.740 ;
        RECT 36.860 48.240 37.400 48.740 ;
        RECT 40.260 48.240 40.800 48.740 ;
        RECT 43.660 48.240 44.200 48.740 ;
        RECT 47.060 48.240 47.600 48.740 ;
        RECT 50.460 48.240 51.000 48.740 ;
        RECT 53.860 48.240 54.400 48.740 ;
        RECT 42.995 84.685 43.050 85.095 ;
        RECT 43.350 84.685 43.405 85.095 ;
        RECT 46.395 84.685 46.450 85.095 ;
        RECT 46.750 84.685 46.805 85.095 ;
        RECT 49.795 84.685 49.850 85.095 ;
        RECT 50.150 84.685 50.205 85.095 ;
        RECT 53.195 84.685 53.250 85.095 ;
        RECT 53.550 84.685 53.605 85.095 ;
        RECT 41.960 84.640 42.500 85.140 ;
        RECT 45.360 84.640 45.900 85.140 ;
        RECT 48.760 84.640 49.300 85.140 ;
        RECT 52.160 84.640 52.700 85.140 ;
        RECT 48.095 85.985 48.150 86.395 ;
        RECT 48.450 85.985 48.505 86.395 ;
        RECT 51.495 85.985 51.550 86.395 ;
        RECT 51.850 85.985 51.905 86.395 ;
        RECT 50.460 85.940 51.000 86.440 ;
        RECT 53.860 85.940 54.400 86.440 ;
        RECT 49.795 87.285 49.850 87.695 ;
        RECT 50.150 87.285 50.205 87.695 ;
        RECT 53.195 87.285 53.250 87.695 ;
        RECT 53.550 87.285 53.605 87.695 ;
        RECT 48.760 87.240 49.300 87.740 ;
        RECT 52.160 87.240 52.700 87.740 ;
        RECT 48.095 88.585 48.150 88.995 ;
        RECT 48.450 88.585 48.505 88.995 ;
        RECT 51.495 88.585 51.550 88.995 ;
        RECT 51.850 88.585 51.905 88.995 ;
        RECT 50.460 88.540 51.000 89.040 ;
        RECT 53.860 88.540 54.400 89.040 ;
        RECT 49.795 89.885 49.850 90.295 ;
        RECT 50.150 89.885 50.205 90.295 ;
        RECT 53.195 89.885 53.250 90.295 ;
        RECT 53.550 89.885 53.605 90.295 ;
        RECT 48.760 89.840 49.300 90.340 ;
        RECT 52.160 89.840 52.700 90.340 ;
        RECT 48.095 91.185 48.150 91.595 ;
        RECT 48.450 91.185 48.505 91.595 ;
        RECT 51.495 91.185 51.550 91.595 ;
        RECT 51.850 91.185 51.905 91.595 ;
        RECT 50.460 91.140 51.000 91.640 ;
        RECT 53.860 91.140 54.400 91.640 ;
        RECT 48.150 92.300 48.570 93.700 ;
        RECT 49.850 92.300 50.270 93.700 ;
        RECT 51.550 92.300 51.970 93.700 ;
        RECT 53.250 92.300 53.670 93.700 ;
        RECT 48.840 95.130 49.285 95.690 ;
        RECT 50.540 95.130 50.985 95.690 ;
        RECT 52.240 95.130 52.685 95.690 ;
        RECT 53.940 95.130 54.385 95.690 ;
        RECT 46.395 89.885 46.450 90.295 ;
        RECT 46.750 89.885 46.805 90.295 ;
        RECT 43.660 85.940 44.200 86.440 ;
        RECT 47.060 85.940 47.600 86.440 ;
        RECT 41.960 87.240 42.500 87.740 ;
        RECT 45.360 87.240 45.900 87.740 ;
        RECT 41.960 89.840 42.500 90.340 ;
        RECT 45.360 89.840 45.900 90.340 ;
        RECT 41.295 85.985 41.350 86.395 ;
        RECT 41.650 85.985 41.705 86.395 ;
        RECT 41.295 91.185 41.350 91.595 ;
        RECT 41.650 91.185 41.705 91.595 ;
        RECT 44.695 91.185 44.750 91.595 ;
        RECT 45.050 91.185 45.105 91.595 ;
        RECT 41.295 88.585 41.350 88.995 ;
        RECT 41.650 88.585 41.705 88.995 ;
        RECT 44.695 88.585 44.750 88.995 ;
        RECT 45.050 88.585 45.105 88.995 ;
        RECT 43.660 91.140 44.200 91.640 ;
        RECT 47.060 91.140 47.600 91.640 ;
        RECT 42.995 87.285 43.050 87.695 ;
        RECT 43.350 87.285 43.405 87.695 ;
        RECT 41.350 92.300 41.770 93.700 ;
        RECT 43.050 92.300 43.470 93.700 ;
        RECT 44.750 92.300 45.170 93.700 ;
        RECT 46.450 92.300 46.870 93.700 ;
        RECT 46.395 87.285 46.450 87.695 ;
        RECT 46.750 87.285 46.805 87.695 ;
        RECT 43.660 88.540 44.200 89.040 ;
        RECT 47.060 88.540 47.600 89.040 ;
        RECT 42.040 95.130 42.485 95.690 ;
        RECT 43.740 95.130 44.185 95.690 ;
        RECT 45.440 95.130 45.885 95.690 ;
        RECT 47.140 95.130 47.585 95.690 ;
        RECT 44.695 85.985 44.750 86.395 ;
        RECT 45.050 85.985 45.105 86.395 ;
        RECT 42.995 89.885 43.050 90.295 ;
        RECT 43.350 89.885 43.405 90.295 ;
        RECT 41.960 82.040 42.500 82.540 ;
        RECT 45.360 82.040 45.900 82.540 ;
        RECT 41.295 83.385 41.350 83.795 ;
        RECT 41.650 83.385 41.705 83.795 ;
        RECT 44.695 83.385 44.750 83.795 ;
        RECT 45.050 83.385 45.105 83.795 ;
        RECT 43.660 83.340 44.200 83.840 ;
        RECT 47.060 83.340 47.600 83.840 ;
        RECT 42.995 72.985 43.050 73.395 ;
        RECT 43.350 72.985 43.405 73.395 ;
        RECT 46.395 72.985 46.450 73.395 ;
        RECT 46.750 72.985 46.805 73.395 ;
        RECT 41.960 72.940 42.500 73.440 ;
        RECT 45.360 72.940 45.900 73.440 ;
        RECT 41.295 74.285 41.350 74.695 ;
        RECT 41.650 74.285 41.705 74.695 ;
        RECT 44.695 74.285 44.750 74.695 ;
        RECT 45.050 74.285 45.105 74.695 ;
        RECT 43.660 74.240 44.200 74.740 ;
        RECT 47.060 74.240 47.600 74.740 ;
        RECT 42.995 75.585 43.050 75.995 ;
        RECT 43.350 75.585 43.405 75.995 ;
        RECT 46.395 75.585 46.450 75.995 ;
        RECT 46.750 75.585 46.805 75.995 ;
        RECT 41.960 75.540 42.500 76.040 ;
        RECT 45.360 75.540 45.900 76.040 ;
        RECT 41.295 76.885 41.350 77.295 ;
        RECT 41.650 76.885 41.705 77.295 ;
        RECT 44.695 76.885 44.750 77.295 ;
        RECT 45.050 76.885 45.105 77.295 ;
        RECT 43.660 76.840 44.200 77.340 ;
        RECT 47.060 76.840 47.600 77.340 ;
        RECT 42.995 78.185 43.050 78.595 ;
        RECT 43.350 78.185 43.405 78.595 ;
        RECT 46.395 78.185 46.450 78.595 ;
        RECT 46.750 78.185 46.805 78.595 ;
        RECT 41.960 78.140 42.500 78.640 ;
        RECT 45.360 78.140 45.900 78.640 ;
        RECT 41.295 79.485 41.350 79.895 ;
        RECT 41.650 79.485 41.705 79.895 ;
        RECT 44.695 79.485 44.750 79.895 ;
        RECT 45.050 79.485 45.105 79.895 ;
        RECT 43.660 79.440 44.200 79.940 ;
        RECT 47.060 79.440 47.600 79.940 ;
        RECT 42.995 82.085 43.050 82.495 ;
        RECT 43.350 82.085 43.405 82.495 ;
        RECT 46.395 82.085 46.450 82.495 ;
        RECT 46.750 82.085 46.805 82.495 ;
        RECT 48.095 83.385 48.150 83.795 ;
        RECT 48.450 83.385 48.505 83.795 ;
        RECT 51.495 83.385 51.550 83.795 ;
        RECT 51.850 83.385 51.905 83.795 ;
        RECT 50.460 76.840 51.000 77.340 ;
        RECT 53.860 76.840 54.400 77.340 ;
        RECT 50.460 83.340 51.000 83.840 ;
        RECT 53.860 83.340 54.400 83.840 ;
        RECT 53.195 72.985 53.250 73.395 ;
        RECT 53.550 72.985 53.605 73.395 ;
        RECT 49.795 72.985 49.850 73.395 ;
        RECT 50.150 72.985 50.205 73.395 ;
        RECT 49.795 78.185 49.850 78.595 ;
        RECT 50.150 78.185 50.205 78.595 ;
        RECT 53.195 78.185 53.250 78.595 ;
        RECT 53.550 78.185 53.605 78.595 ;
        RECT 49.795 75.585 49.850 75.995 ;
        RECT 50.150 75.585 50.205 75.995 ;
        RECT 48.760 78.140 49.300 78.640 ;
        RECT 52.160 78.140 52.700 78.640 ;
        RECT 53.195 75.585 53.250 75.995 ;
        RECT 53.550 75.585 53.605 75.995 ;
        RECT 48.095 74.285 48.150 74.695 ;
        RECT 48.450 74.285 48.505 74.695 ;
        RECT 48.095 79.485 48.150 79.895 ;
        RECT 48.450 79.485 48.505 79.895 ;
        RECT 51.495 79.485 51.550 79.895 ;
        RECT 51.850 79.485 51.905 79.895 ;
        RECT 48.760 75.540 49.300 76.040 ;
        RECT 52.160 75.540 52.700 76.040 ;
        RECT 50.460 79.440 51.000 79.940 ;
        RECT 53.860 79.440 54.400 79.940 ;
        RECT 51.495 74.285 51.550 74.695 ;
        RECT 51.850 74.285 51.905 74.695 ;
        RECT 48.760 72.940 49.300 73.440 ;
        RECT 52.160 72.940 52.700 73.440 ;
        RECT 49.795 82.085 49.850 82.495 ;
        RECT 50.150 82.085 50.205 82.495 ;
        RECT 53.195 82.085 53.250 82.495 ;
        RECT 53.550 82.085 53.605 82.495 ;
        RECT 48.095 76.885 48.150 77.295 ;
        RECT 48.450 76.885 48.505 77.295 ;
        RECT 48.760 82.040 49.300 82.540 ;
        RECT 52.160 82.040 52.700 82.540 ;
        RECT 51.495 76.885 51.550 77.295 ;
        RECT 51.850 76.885 51.905 77.295 ;
        RECT 50.460 74.240 51.000 74.740 ;
        RECT 53.860 74.240 54.400 74.740 ;
        RECT 29.395 84.685 29.450 85.095 ;
        RECT 29.750 84.685 29.805 85.095 ;
        RECT 32.795 84.685 32.850 85.095 ;
        RECT 33.150 84.685 33.205 85.095 ;
        RECT 36.195 84.685 36.250 85.095 ;
        RECT 36.550 84.685 36.605 85.095 ;
        RECT 39.595 84.685 39.650 85.095 ;
        RECT 39.950 84.685 40.005 85.095 ;
        RECT 28.360 84.640 28.900 85.140 ;
        RECT 31.760 84.640 32.300 85.140 ;
        RECT 35.160 84.640 35.700 85.140 ;
        RECT 38.560 84.640 39.100 85.140 ;
        RECT 34.495 85.985 34.550 86.395 ;
        RECT 34.850 85.985 34.905 86.395 ;
        RECT 37.895 85.985 37.950 86.395 ;
        RECT 38.250 85.985 38.305 86.395 ;
        RECT 36.860 85.940 37.400 86.440 ;
        RECT 40.260 85.940 40.800 86.440 ;
        RECT 36.195 87.285 36.250 87.695 ;
        RECT 36.550 87.285 36.605 87.695 ;
        RECT 39.595 87.285 39.650 87.695 ;
        RECT 39.950 87.285 40.005 87.695 ;
        RECT 35.160 87.240 35.700 87.740 ;
        RECT 38.560 87.240 39.100 87.740 ;
        RECT 34.495 88.585 34.550 88.995 ;
        RECT 34.850 88.585 34.905 88.995 ;
        RECT 37.895 88.585 37.950 88.995 ;
        RECT 38.250 88.585 38.305 88.995 ;
        RECT 36.860 88.540 37.400 89.040 ;
        RECT 40.260 88.540 40.800 89.040 ;
        RECT 36.195 89.885 36.250 90.295 ;
        RECT 36.550 89.885 36.605 90.295 ;
        RECT 39.595 89.885 39.650 90.295 ;
        RECT 39.950 89.885 40.005 90.295 ;
        RECT 35.160 89.840 35.700 90.340 ;
        RECT 38.560 89.840 39.100 90.340 ;
        RECT 34.495 91.185 34.550 91.595 ;
        RECT 34.850 91.185 34.905 91.595 ;
        RECT 37.895 91.185 37.950 91.595 ;
        RECT 38.250 91.185 38.305 91.595 ;
        RECT 36.860 91.140 37.400 91.640 ;
        RECT 40.260 91.140 40.800 91.640 ;
        RECT 34.550 92.300 34.970 93.700 ;
        RECT 36.250 92.300 36.670 93.700 ;
        RECT 37.950 92.300 38.370 93.700 ;
        RECT 39.650 92.300 40.070 93.700 ;
        RECT 35.240 95.130 35.685 95.690 ;
        RECT 36.940 95.130 37.385 95.690 ;
        RECT 38.640 95.130 39.085 95.690 ;
        RECT 40.340 95.130 40.785 95.690 ;
        RECT 32.795 89.885 32.850 90.295 ;
        RECT 33.150 89.885 33.205 90.295 ;
        RECT 30.060 85.940 30.600 86.440 ;
        RECT 33.460 85.940 34.000 86.440 ;
        RECT 28.360 87.240 28.900 87.740 ;
        RECT 31.760 87.240 32.300 87.740 ;
        RECT 28.360 89.840 28.900 90.340 ;
        RECT 31.760 89.840 32.300 90.340 ;
        RECT 27.695 85.985 27.750 86.395 ;
        RECT 28.050 85.985 28.105 86.395 ;
        RECT 27.695 91.185 27.750 91.595 ;
        RECT 28.050 91.185 28.105 91.595 ;
        RECT 31.095 91.185 31.150 91.595 ;
        RECT 31.450 91.185 31.505 91.595 ;
        RECT 27.695 88.585 27.750 88.995 ;
        RECT 28.050 88.585 28.105 88.995 ;
        RECT 31.095 88.585 31.150 88.995 ;
        RECT 31.450 88.585 31.505 88.995 ;
        RECT 30.060 91.140 30.600 91.640 ;
        RECT 33.460 91.140 34.000 91.640 ;
        RECT 29.395 87.285 29.450 87.695 ;
        RECT 29.750 87.285 29.805 87.695 ;
        RECT 27.750 92.300 28.170 93.700 ;
        RECT 29.450 92.300 29.870 93.700 ;
        RECT 31.150 92.300 31.570 93.700 ;
        RECT 32.850 92.300 33.270 93.700 ;
        RECT 32.795 87.285 32.850 87.695 ;
        RECT 33.150 87.285 33.205 87.695 ;
        RECT 30.060 88.540 30.600 89.040 ;
        RECT 33.460 88.540 34.000 89.040 ;
        RECT 28.440 95.130 28.885 95.690 ;
        RECT 30.140 95.130 30.585 95.690 ;
        RECT 31.840 95.130 32.285 95.690 ;
        RECT 33.540 95.130 33.985 95.690 ;
        RECT 31.095 85.985 31.150 86.395 ;
        RECT 31.450 85.985 31.505 86.395 ;
        RECT 29.395 89.885 29.450 90.295 ;
        RECT 29.750 89.885 29.805 90.295 ;
        RECT 29.395 72.985 29.450 73.395 ;
        RECT 29.750 72.985 29.805 73.395 ;
        RECT 28.360 78.140 28.900 78.640 ;
        RECT 31.760 78.140 32.300 78.640 ;
        RECT 27.695 76.885 27.750 77.295 ;
        RECT 28.050 76.885 28.105 77.295 ;
        RECT 31.095 76.885 31.150 77.295 ;
        RECT 31.450 76.885 31.505 77.295 ;
        RECT 32.795 72.985 32.850 73.395 ;
        RECT 33.150 72.985 33.205 73.395 ;
        RECT 29.395 75.585 29.450 75.995 ;
        RECT 29.750 75.585 29.805 75.995 ;
        RECT 27.695 74.285 27.750 74.695 ;
        RECT 28.050 74.285 28.105 74.695 ;
        RECT 31.095 74.285 31.150 74.695 ;
        RECT 31.450 74.285 31.505 74.695 ;
        RECT 28.360 82.040 28.900 82.540 ;
        RECT 31.760 82.040 32.300 82.540 ;
        RECT 28.360 75.540 28.900 76.040 ;
        RECT 31.760 75.540 32.300 76.040 ;
        RECT 30.060 79.440 30.600 79.940 ;
        RECT 33.460 79.440 34.000 79.940 ;
        RECT 28.360 72.940 28.900 73.440 ;
        RECT 31.760 72.940 32.300 73.440 ;
        RECT 32.795 75.585 32.850 75.995 ;
        RECT 33.150 75.585 33.205 75.995 ;
        RECT 30.060 83.340 30.600 83.840 ;
        RECT 33.460 83.340 34.000 83.840 ;
        RECT 29.395 78.185 29.450 78.595 ;
        RECT 29.750 78.185 29.805 78.595 ;
        RECT 32.795 78.185 32.850 78.595 ;
        RECT 33.150 78.185 33.205 78.595 ;
        RECT 27.695 83.385 27.750 83.795 ;
        RECT 28.050 83.385 28.105 83.795 ;
        RECT 31.095 83.385 31.150 83.795 ;
        RECT 31.450 83.385 31.505 83.795 ;
        RECT 27.695 79.485 27.750 79.895 ;
        RECT 28.050 79.485 28.105 79.895 ;
        RECT 31.095 79.485 31.150 79.895 ;
        RECT 31.450 79.485 31.505 79.895 ;
        RECT 29.395 82.085 29.450 82.495 ;
        RECT 29.750 82.085 29.805 82.495 ;
        RECT 32.795 82.085 32.850 82.495 ;
        RECT 33.150 82.085 33.205 82.495 ;
        RECT 30.060 74.240 30.600 74.740 ;
        RECT 33.460 74.240 34.000 74.740 ;
        RECT 30.060 76.840 30.600 77.340 ;
        RECT 33.460 76.840 34.000 77.340 ;
        RECT 34.495 76.885 34.550 77.295 ;
        RECT 34.850 76.885 34.905 77.295 ;
        RECT 37.895 76.885 37.950 77.295 ;
        RECT 38.250 76.885 38.305 77.295 ;
        RECT 34.495 74.285 34.550 74.695 ;
        RECT 34.850 74.285 34.905 74.695 ;
        RECT 35.160 82.040 35.700 82.540 ;
        RECT 38.560 82.040 39.100 82.540 ;
        RECT 37.895 74.285 37.950 74.695 ;
        RECT 38.250 74.285 38.305 74.695 ;
        RECT 36.860 83.340 37.400 83.840 ;
        RECT 40.260 83.340 40.800 83.840 ;
        RECT 36.195 78.185 36.250 78.595 ;
        RECT 36.550 78.185 36.605 78.595 ;
        RECT 35.160 72.940 35.700 73.440 ;
        RECT 38.560 72.940 39.100 73.440 ;
        RECT 36.195 75.585 36.250 75.995 ;
        RECT 36.550 75.585 36.605 75.995 ;
        RECT 39.595 75.585 39.650 75.995 ;
        RECT 39.950 75.585 40.005 75.995 ;
        RECT 36.195 82.085 36.250 82.495 ;
        RECT 36.550 82.085 36.605 82.495 ;
        RECT 39.595 82.085 39.650 82.495 ;
        RECT 39.950 82.085 40.005 82.495 ;
        RECT 34.495 79.485 34.550 79.895 ;
        RECT 34.850 79.485 34.905 79.895 ;
        RECT 35.160 75.540 35.700 76.040 ;
        RECT 38.560 75.540 39.100 76.040 ;
        RECT 34.495 83.385 34.550 83.795 ;
        RECT 34.850 83.385 34.905 83.795 ;
        RECT 37.895 83.385 37.950 83.795 ;
        RECT 38.250 83.385 38.305 83.795 ;
        RECT 37.895 79.485 37.950 79.895 ;
        RECT 38.250 79.485 38.305 79.895 ;
        RECT 36.860 79.440 37.400 79.940 ;
        RECT 40.260 79.440 40.800 79.940 ;
        RECT 39.595 78.185 39.650 78.595 ;
        RECT 39.950 78.185 40.005 78.595 ;
        RECT 35.160 78.140 35.700 78.640 ;
        RECT 38.560 78.140 39.100 78.640 ;
        RECT 36.195 72.985 36.250 73.395 ;
        RECT 36.550 72.985 36.605 73.395 ;
        RECT 36.860 74.240 37.400 74.740 ;
        RECT 40.260 74.240 40.800 74.740 ;
        RECT 39.595 72.985 39.650 73.395 ;
        RECT 39.950 72.985 40.005 73.395 ;
        RECT 36.860 76.840 37.400 77.340 ;
        RECT 40.260 76.840 40.800 77.340 ;
        RECT 35.160 70.340 35.700 70.840 ;
        RECT 38.560 70.340 39.100 70.840 ;
        RECT 34.495 71.685 34.550 72.095 ;
        RECT 34.850 71.685 34.905 72.095 ;
        RECT 37.895 71.685 37.950 72.095 ;
        RECT 38.250 71.685 38.305 72.095 ;
        RECT 36.860 71.640 37.400 72.140 ;
        RECT 40.260 71.640 40.800 72.140 ;
        RECT 36.195 61.285 36.250 61.695 ;
        RECT 36.550 61.285 36.605 61.695 ;
        RECT 39.595 61.285 39.650 61.695 ;
        RECT 39.950 61.285 40.005 61.695 ;
        RECT 35.160 61.240 35.700 61.740 ;
        RECT 38.560 61.240 39.100 61.740 ;
        RECT 34.495 62.585 34.550 62.995 ;
        RECT 34.850 62.585 34.905 62.995 ;
        RECT 37.895 62.585 37.950 62.995 ;
        RECT 38.250 62.585 38.305 62.995 ;
        RECT 36.860 62.540 37.400 63.040 ;
        RECT 40.260 62.540 40.800 63.040 ;
        RECT 36.195 63.885 36.250 64.295 ;
        RECT 36.550 63.885 36.605 64.295 ;
        RECT 39.595 63.885 39.650 64.295 ;
        RECT 39.950 63.885 40.005 64.295 ;
        RECT 35.160 63.840 35.700 64.340 ;
        RECT 38.560 63.840 39.100 64.340 ;
        RECT 34.495 65.185 34.550 65.595 ;
        RECT 34.850 65.185 34.905 65.595 ;
        RECT 37.895 65.185 37.950 65.595 ;
        RECT 38.250 65.185 38.305 65.595 ;
        RECT 36.860 65.140 37.400 65.640 ;
        RECT 40.260 65.140 40.800 65.640 ;
        RECT 36.195 66.485 36.250 66.895 ;
        RECT 36.550 66.485 36.605 66.895 ;
        RECT 39.595 66.485 39.650 66.895 ;
        RECT 39.950 66.485 40.005 66.895 ;
        RECT 35.160 66.440 35.700 66.940 ;
        RECT 38.560 66.440 39.100 66.940 ;
        RECT 34.495 67.785 34.550 68.195 ;
        RECT 34.850 67.785 34.905 68.195 ;
        RECT 37.895 67.785 37.950 68.195 ;
        RECT 38.250 67.785 38.305 68.195 ;
        RECT 36.860 67.740 37.400 68.240 ;
        RECT 40.260 67.740 40.800 68.240 ;
        RECT 36.195 70.385 36.250 70.795 ;
        RECT 36.550 70.385 36.605 70.795 ;
        RECT 39.595 70.385 39.650 70.795 ;
        RECT 39.950 70.385 40.005 70.795 ;
        RECT 28.360 63.840 28.900 64.340 ;
        RECT 31.760 63.840 32.300 64.340 ;
        RECT 28.360 61.240 28.900 61.740 ;
        RECT 31.760 61.240 32.300 61.740 ;
        RECT 27.695 65.185 27.750 65.595 ;
        RECT 28.050 65.185 28.105 65.595 ;
        RECT 31.095 65.185 31.150 65.595 ;
        RECT 31.450 65.185 31.505 65.595 ;
        RECT 30.060 71.640 30.600 72.140 ;
        RECT 33.460 71.640 34.000 72.140 ;
        RECT 27.695 62.585 27.750 62.995 ;
        RECT 28.050 62.585 28.105 62.995 ;
        RECT 30.060 65.140 30.600 65.640 ;
        RECT 33.460 65.140 34.000 65.640 ;
        RECT 31.095 62.585 31.150 62.995 ;
        RECT 31.450 62.585 31.505 62.995 ;
        RECT 29.395 66.485 29.450 66.895 ;
        RECT 29.750 66.485 29.805 66.895 ;
        RECT 32.795 66.485 32.850 66.895 ;
        RECT 33.150 66.485 33.205 66.895 ;
        RECT 31.095 71.685 31.150 72.095 ;
        RECT 31.450 71.685 31.505 72.095 ;
        RECT 29.395 61.285 29.450 61.695 ;
        RECT 29.750 61.285 29.805 61.695 ;
        RECT 28.360 66.440 28.900 66.940 ;
        RECT 31.760 66.440 32.300 66.940 ;
        RECT 30.060 62.540 30.600 63.040 ;
        RECT 33.460 62.540 34.000 63.040 ;
        RECT 27.695 67.785 27.750 68.195 ;
        RECT 28.050 67.785 28.105 68.195 ;
        RECT 31.095 67.785 31.150 68.195 ;
        RECT 31.450 67.785 31.505 68.195 ;
        RECT 32.795 61.285 32.850 61.695 ;
        RECT 33.150 61.285 33.205 61.695 ;
        RECT 29.395 63.885 29.450 64.295 ;
        RECT 29.750 63.885 29.805 64.295 ;
        RECT 30.060 67.740 30.600 68.240 ;
        RECT 33.460 67.740 34.000 68.240 ;
        RECT 32.795 63.885 32.850 64.295 ;
        RECT 33.150 63.885 33.205 64.295 ;
        RECT 29.395 70.385 29.450 70.795 ;
        RECT 29.750 70.385 29.805 70.795 ;
        RECT 32.795 70.385 32.850 70.795 ;
        RECT 33.150 70.385 33.205 70.795 ;
        RECT 28.360 70.340 28.900 70.840 ;
        RECT 31.760 70.340 32.300 70.840 ;
        RECT 27.695 71.685 27.750 72.095 ;
        RECT 28.050 71.685 28.105 72.095 ;
        RECT 31.095 56.085 31.150 56.495 ;
        RECT 31.450 56.085 31.505 56.495 ;
        RECT 30.060 56.040 30.600 56.540 ;
        RECT 33.460 56.040 34.000 56.540 ;
        RECT 29.395 58.685 29.450 59.095 ;
        RECT 29.750 58.685 29.805 59.095 ;
        RECT 32.795 58.685 32.850 59.095 ;
        RECT 33.150 58.685 33.205 59.095 ;
        RECT 28.360 58.640 28.900 59.140 ;
        RECT 31.760 58.640 32.300 59.140 ;
        RECT 27.695 59.985 27.750 60.395 ;
        RECT 28.050 59.985 28.105 60.395 ;
        RECT 31.095 59.985 31.150 60.395 ;
        RECT 31.450 59.985 31.505 60.395 ;
        RECT 30.060 59.940 30.600 60.440 ;
        RECT 33.460 59.940 34.000 60.440 ;
        RECT 29.395 49.585 29.450 49.995 ;
        RECT 29.750 49.585 29.805 49.995 ;
        RECT 32.795 49.585 32.850 49.995 ;
        RECT 33.150 49.585 33.205 49.995 ;
        RECT 28.360 49.540 28.900 50.040 ;
        RECT 31.760 49.540 32.300 50.040 ;
        RECT 27.695 50.885 27.750 51.295 ;
        RECT 28.050 50.885 28.105 51.295 ;
        RECT 31.095 50.885 31.150 51.295 ;
        RECT 31.450 50.885 31.505 51.295 ;
        RECT 30.060 50.840 30.600 51.340 ;
        RECT 33.460 50.840 34.000 51.340 ;
        RECT 29.395 52.185 29.450 52.595 ;
        RECT 29.750 52.185 29.805 52.595 ;
        RECT 32.795 52.185 32.850 52.595 ;
        RECT 33.150 52.185 33.205 52.595 ;
        RECT 28.360 52.140 28.900 52.640 ;
        RECT 31.760 52.140 32.300 52.640 ;
        RECT 27.695 53.485 27.750 53.895 ;
        RECT 28.050 53.485 28.105 53.895 ;
        RECT 31.095 53.485 31.150 53.895 ;
        RECT 31.450 53.485 31.505 53.895 ;
        RECT 30.060 53.440 30.600 53.940 ;
        RECT 33.460 53.440 34.000 53.940 ;
        RECT 29.395 54.785 29.450 55.195 ;
        RECT 29.750 54.785 29.805 55.195 ;
        RECT 32.795 54.785 32.850 55.195 ;
        RECT 33.150 54.785 33.205 55.195 ;
        RECT 28.360 54.740 28.900 55.240 ;
        RECT 31.760 54.740 32.300 55.240 ;
        RECT 27.695 56.085 27.750 56.495 ;
        RECT 28.050 56.085 28.105 56.495 ;
        RECT 34.495 53.485 34.550 53.895 ;
        RECT 34.850 53.485 34.905 53.895 ;
        RECT 35.160 58.640 35.700 59.140 ;
        RECT 38.560 58.640 39.100 59.140 ;
        RECT 37.895 53.485 37.950 53.895 ;
        RECT 38.250 53.485 38.305 53.895 ;
        RECT 36.860 50.840 37.400 51.340 ;
        RECT 40.260 50.840 40.800 51.340 ;
        RECT 34.495 59.985 34.550 60.395 ;
        RECT 34.850 59.985 34.905 60.395 ;
        RECT 37.895 59.985 37.950 60.395 ;
        RECT 38.250 59.985 38.305 60.395 ;
        RECT 36.860 53.440 37.400 53.940 ;
        RECT 40.260 53.440 40.800 53.940 ;
        RECT 36.860 59.940 37.400 60.440 ;
        RECT 40.260 59.940 40.800 60.440 ;
        RECT 39.595 49.585 39.650 49.995 ;
        RECT 39.950 49.585 40.005 49.995 ;
        RECT 36.195 49.585 36.250 49.995 ;
        RECT 36.550 49.585 36.605 49.995 ;
        RECT 36.195 54.785 36.250 55.195 ;
        RECT 36.550 54.785 36.605 55.195 ;
        RECT 39.595 54.785 39.650 55.195 ;
        RECT 39.950 54.785 40.005 55.195 ;
        RECT 36.195 52.185 36.250 52.595 ;
        RECT 36.550 52.185 36.605 52.595 ;
        RECT 35.160 54.740 35.700 55.240 ;
        RECT 38.560 54.740 39.100 55.240 ;
        RECT 39.595 52.185 39.650 52.595 ;
        RECT 39.950 52.185 40.005 52.595 ;
        RECT 34.495 50.885 34.550 51.295 ;
        RECT 34.850 50.885 34.905 51.295 ;
        RECT 34.495 56.085 34.550 56.495 ;
        RECT 34.850 56.085 34.905 56.495 ;
        RECT 37.895 56.085 37.950 56.495 ;
        RECT 38.250 56.085 38.305 56.495 ;
        RECT 35.160 52.140 35.700 52.640 ;
        RECT 38.560 52.140 39.100 52.640 ;
        RECT 36.860 56.040 37.400 56.540 ;
        RECT 40.260 56.040 40.800 56.540 ;
        RECT 37.895 50.885 37.950 51.295 ;
        RECT 38.250 50.885 38.305 51.295 ;
        RECT 35.160 49.540 35.700 50.040 ;
        RECT 38.560 49.540 39.100 50.040 ;
        RECT 36.195 58.685 36.250 59.095 ;
        RECT 36.550 58.685 36.605 59.095 ;
        RECT 39.595 58.685 39.650 59.095 ;
        RECT 39.950 58.685 40.005 59.095 ;
        RECT 48.095 71.685 48.150 72.095 ;
        RECT 48.450 71.685 48.505 72.095 ;
        RECT 51.495 71.685 51.550 72.095 ;
        RECT 51.850 71.685 51.905 72.095 ;
        RECT 50.460 71.640 51.000 72.140 ;
        RECT 53.860 71.640 54.400 72.140 ;
        RECT 49.795 61.285 49.850 61.695 ;
        RECT 50.150 61.285 50.205 61.695 ;
        RECT 53.195 61.285 53.250 61.695 ;
        RECT 53.550 61.285 53.605 61.695 ;
        RECT 48.760 61.240 49.300 61.740 ;
        RECT 52.160 61.240 52.700 61.740 ;
        RECT 48.095 62.585 48.150 62.995 ;
        RECT 48.450 62.585 48.505 62.995 ;
        RECT 51.495 62.585 51.550 62.995 ;
        RECT 51.850 62.585 51.905 62.995 ;
        RECT 50.460 62.540 51.000 63.040 ;
        RECT 53.860 62.540 54.400 63.040 ;
        RECT 49.795 63.885 49.850 64.295 ;
        RECT 50.150 63.885 50.205 64.295 ;
        RECT 53.195 63.885 53.250 64.295 ;
        RECT 53.550 63.885 53.605 64.295 ;
        RECT 48.760 63.840 49.300 64.340 ;
        RECT 52.160 63.840 52.700 64.340 ;
        RECT 48.095 65.185 48.150 65.595 ;
        RECT 48.450 65.185 48.505 65.595 ;
        RECT 51.495 65.185 51.550 65.595 ;
        RECT 51.850 65.185 51.905 65.595 ;
        RECT 50.460 65.140 51.000 65.640 ;
        RECT 53.860 65.140 54.400 65.640 ;
        RECT 49.795 66.485 49.850 66.895 ;
        RECT 50.150 66.485 50.205 66.895 ;
        RECT 53.195 66.485 53.250 66.895 ;
        RECT 53.550 66.485 53.605 66.895 ;
        RECT 48.760 66.440 49.300 66.940 ;
        RECT 52.160 66.440 52.700 66.940 ;
        RECT 48.095 67.785 48.150 68.195 ;
        RECT 48.450 67.785 48.505 68.195 ;
        RECT 51.495 67.785 51.550 68.195 ;
        RECT 51.850 67.785 51.905 68.195 ;
        RECT 50.460 67.740 51.000 68.240 ;
        RECT 53.860 67.740 54.400 68.240 ;
        RECT 49.795 70.385 49.850 70.795 ;
        RECT 50.150 70.385 50.205 70.795 ;
        RECT 53.195 70.385 53.250 70.795 ;
        RECT 53.550 70.385 53.605 70.795 ;
        RECT 48.760 70.340 49.300 70.840 ;
        RECT 52.160 70.340 52.700 70.840 ;
        RECT 41.295 65.185 41.350 65.595 ;
        RECT 41.650 65.185 41.705 65.595 ;
        RECT 44.695 65.185 44.750 65.595 ;
        RECT 45.050 65.185 45.105 65.595 ;
        RECT 41.295 62.585 41.350 62.995 ;
        RECT 41.650 62.585 41.705 62.995 ;
        RECT 44.695 62.585 44.750 62.995 ;
        RECT 45.050 62.585 45.105 62.995 ;
        RECT 43.660 65.140 44.200 65.640 ;
        RECT 47.060 65.140 47.600 65.640 ;
        RECT 42.995 61.285 43.050 61.695 ;
        RECT 43.350 61.285 43.405 61.695 ;
        RECT 42.995 66.485 43.050 66.895 ;
        RECT 43.350 66.485 43.405 66.895 ;
        RECT 46.395 66.485 46.450 66.895 ;
        RECT 46.750 66.485 46.805 66.895 ;
        RECT 46.395 61.285 46.450 61.695 ;
        RECT 46.750 61.285 46.805 61.695 ;
        RECT 43.660 62.540 44.200 63.040 ;
        RECT 47.060 62.540 47.600 63.040 ;
        RECT 41.960 66.440 42.500 66.940 ;
        RECT 45.360 66.440 45.900 66.940 ;
        RECT 44.695 71.685 44.750 72.095 ;
        RECT 45.050 71.685 45.105 72.095 ;
        RECT 41.295 67.785 41.350 68.195 ;
        RECT 41.650 67.785 41.705 68.195 ;
        RECT 44.695 67.785 44.750 68.195 ;
        RECT 45.050 67.785 45.105 68.195 ;
        RECT 42.995 63.885 43.050 64.295 ;
        RECT 43.350 63.885 43.405 64.295 ;
        RECT 46.395 63.885 46.450 64.295 ;
        RECT 46.750 63.885 46.805 64.295 ;
        RECT 43.660 67.740 44.200 68.240 ;
        RECT 47.060 67.740 47.600 68.240 ;
        RECT 43.660 71.640 44.200 72.140 ;
        RECT 47.060 71.640 47.600 72.140 ;
        RECT 42.995 70.385 43.050 70.795 ;
        RECT 43.350 70.385 43.405 70.795 ;
        RECT 46.395 70.385 46.450 70.795 ;
        RECT 46.750 70.385 46.805 70.795 ;
        RECT 41.960 61.240 42.500 61.740 ;
        RECT 45.360 61.240 45.900 61.740 ;
        RECT 41.960 63.840 42.500 64.340 ;
        RECT 45.360 63.840 45.900 64.340 ;
        RECT 41.960 70.340 42.500 70.840 ;
        RECT 45.360 70.340 45.900 70.840 ;
        RECT 41.295 71.685 41.350 72.095 ;
        RECT 41.650 71.685 41.705 72.095 ;
        RECT 44.695 56.085 44.750 56.495 ;
        RECT 45.050 56.085 45.105 56.495 ;
        RECT 42.995 58.685 43.050 59.095 ;
        RECT 43.350 58.685 43.405 59.095 ;
        RECT 46.395 58.685 46.450 59.095 ;
        RECT 46.750 58.685 46.805 59.095 ;
        RECT 42.995 49.585 43.050 49.995 ;
        RECT 43.350 49.585 43.405 49.995 ;
        RECT 41.960 54.740 42.500 55.240 ;
        RECT 45.360 54.740 45.900 55.240 ;
        RECT 41.295 53.485 41.350 53.895 ;
        RECT 41.650 53.485 41.705 53.895 ;
        RECT 44.695 53.485 44.750 53.895 ;
        RECT 45.050 53.485 45.105 53.895 ;
        RECT 41.960 52.140 42.500 52.640 ;
        RECT 45.360 52.140 45.900 52.640 ;
        RECT 46.395 49.585 46.450 49.995 ;
        RECT 46.750 49.585 46.805 49.995 ;
        RECT 42.995 52.185 43.050 52.595 ;
        RECT 43.350 52.185 43.405 52.595 ;
        RECT 41.295 50.885 41.350 51.295 ;
        RECT 41.650 50.885 41.705 51.295 ;
        RECT 41.960 58.640 42.500 59.140 ;
        RECT 45.360 58.640 45.900 59.140 ;
        RECT 44.695 50.885 44.750 51.295 ;
        RECT 45.050 50.885 45.105 51.295 ;
        RECT 43.660 56.040 44.200 56.540 ;
        RECT 47.060 56.040 47.600 56.540 ;
        RECT 43.660 50.840 44.200 51.340 ;
        RECT 47.060 50.840 47.600 51.340 ;
        RECT 46.395 52.185 46.450 52.595 ;
        RECT 46.750 52.185 46.805 52.595 ;
        RECT 43.660 59.940 44.200 60.440 ;
        RECT 47.060 59.940 47.600 60.440 ;
        RECT 41.960 49.540 42.500 50.040 ;
        RECT 45.360 49.540 45.900 50.040 ;
        RECT 42.995 54.785 43.050 55.195 ;
        RECT 43.350 54.785 43.405 55.195 ;
        RECT 41.295 59.985 41.350 60.395 ;
        RECT 41.650 59.985 41.705 60.395 ;
        RECT 44.695 59.985 44.750 60.395 ;
        RECT 45.050 59.985 45.105 60.395 ;
        RECT 46.395 54.785 46.450 55.195 ;
        RECT 46.750 54.785 46.805 55.195 ;
        RECT 41.295 56.085 41.350 56.495 ;
        RECT 41.650 56.085 41.705 56.495 ;
        RECT 43.660 53.440 44.200 53.940 ;
        RECT 47.060 53.440 47.600 53.940 ;
        RECT 49.795 49.585 49.850 49.995 ;
        RECT 50.150 49.585 50.205 49.995 ;
        RECT 48.095 50.885 48.150 51.295 ;
        RECT 48.450 50.885 48.505 51.295 ;
        RECT 51.495 50.885 51.550 51.295 ;
        RECT 51.850 50.885 51.905 51.295 ;
        RECT 48.095 56.085 48.150 56.495 ;
        RECT 48.450 56.085 48.505 56.495 ;
        RECT 48.760 49.540 49.300 50.040 ;
        RECT 52.160 49.540 52.700 50.040 ;
        RECT 48.760 58.640 49.300 59.140 ;
        RECT 52.160 58.640 52.700 59.140 ;
        RECT 51.495 56.085 51.550 56.495 ;
        RECT 51.850 56.085 51.905 56.495 ;
        RECT 53.195 49.585 53.250 49.995 ;
        RECT 53.550 49.585 53.605 49.995 ;
        RECT 48.095 53.485 48.150 53.895 ;
        RECT 48.450 53.485 48.505 53.895 ;
        RECT 51.495 53.485 51.550 53.895 ;
        RECT 51.850 53.485 51.905 53.895 ;
        RECT 48.760 52.140 49.300 52.640 ;
        RECT 52.160 52.140 52.700 52.640 ;
        RECT 50.460 50.840 51.000 51.340 ;
        RECT 53.860 50.840 54.400 51.340 ;
        RECT 48.760 54.740 49.300 55.240 ;
        RECT 52.160 54.740 52.700 55.240 ;
        RECT 50.460 59.940 51.000 60.440 ;
        RECT 53.860 59.940 54.400 60.440 ;
        RECT 49.795 54.785 49.850 55.195 ;
        RECT 50.150 54.785 50.205 55.195 ;
        RECT 49.795 52.185 49.850 52.595 ;
        RECT 50.150 52.185 50.205 52.595 ;
        RECT 53.195 52.185 53.250 52.595 ;
        RECT 53.550 52.185 53.605 52.595 ;
        RECT 49.795 58.685 49.850 59.095 ;
        RECT 50.150 58.685 50.205 59.095 ;
        RECT 53.195 58.685 53.250 59.095 ;
        RECT 53.550 58.685 53.605 59.095 ;
        RECT 50.460 56.040 51.000 56.540 ;
        RECT 53.860 56.040 54.400 56.540 ;
        RECT 48.095 59.985 48.150 60.395 ;
        RECT 48.450 59.985 48.505 60.395 ;
        RECT 51.495 59.985 51.550 60.395 ;
        RECT 51.850 59.985 51.905 60.395 ;
        RECT 53.195 54.785 53.250 55.195 ;
        RECT 53.550 54.785 53.605 55.195 ;
        RECT 50.460 53.440 51.000 53.940 ;
        RECT 53.860 53.440 54.400 53.940 ;
        RECT 15.795 84.685 15.850 85.095 ;
        RECT 16.150 84.685 16.205 85.095 ;
        RECT 19.195 84.685 19.250 85.095 ;
        RECT 19.550 84.685 19.605 85.095 ;
        RECT 22.595 84.685 22.650 85.095 ;
        RECT 22.950 84.685 23.005 85.095 ;
        RECT 25.995 84.685 26.050 85.095 ;
        RECT 26.350 84.685 26.405 85.095 ;
        RECT 14.760 84.640 15.300 85.140 ;
        RECT 18.160 84.640 18.700 85.140 ;
        RECT 21.560 84.640 22.100 85.140 ;
        RECT 24.960 84.640 25.500 85.140 ;
        RECT 20.895 85.985 20.950 86.395 ;
        RECT 21.250 85.985 21.305 86.395 ;
        RECT 24.295 85.985 24.350 86.395 ;
        RECT 24.650 85.985 24.705 86.395 ;
        RECT 23.260 85.940 23.800 86.440 ;
        RECT 26.660 85.940 27.200 86.440 ;
        RECT 22.595 87.285 22.650 87.695 ;
        RECT 22.950 87.285 23.005 87.695 ;
        RECT 25.995 87.285 26.050 87.695 ;
        RECT 26.350 87.285 26.405 87.695 ;
        RECT 21.560 87.240 22.100 87.740 ;
        RECT 24.960 87.240 25.500 87.740 ;
        RECT 20.895 88.585 20.950 88.995 ;
        RECT 21.250 88.585 21.305 88.995 ;
        RECT 24.295 88.585 24.350 88.995 ;
        RECT 24.650 88.585 24.705 88.995 ;
        RECT 23.260 88.540 23.800 89.040 ;
        RECT 26.660 88.540 27.200 89.040 ;
        RECT 22.595 89.885 22.650 90.295 ;
        RECT 22.950 89.885 23.005 90.295 ;
        RECT 25.995 89.885 26.050 90.295 ;
        RECT 26.350 89.885 26.405 90.295 ;
        RECT 21.560 89.840 22.100 90.340 ;
        RECT 24.960 89.840 25.500 90.340 ;
        RECT 20.895 91.185 20.950 91.595 ;
        RECT 21.250 91.185 21.305 91.595 ;
        RECT 24.295 91.185 24.350 91.595 ;
        RECT 24.650 91.185 24.705 91.595 ;
        RECT 23.260 91.140 23.800 91.640 ;
        RECT 26.660 91.140 27.200 91.640 ;
        RECT 20.950 92.300 21.370 93.700 ;
        RECT 22.650 92.300 23.070 93.700 ;
        RECT 24.350 92.300 24.770 93.700 ;
        RECT 26.050 92.300 26.470 93.700 ;
        RECT 21.640 95.130 22.085 95.690 ;
        RECT 23.340 95.130 23.785 95.690 ;
        RECT 25.040 95.130 25.485 95.690 ;
        RECT 26.740 95.130 27.185 95.690 ;
        RECT 19.195 89.885 19.250 90.295 ;
        RECT 19.550 89.885 19.605 90.295 ;
        RECT 16.460 85.940 17.000 86.440 ;
        RECT 19.860 85.940 20.400 86.440 ;
        RECT 14.760 87.240 15.300 87.740 ;
        RECT 18.160 87.240 18.700 87.740 ;
        RECT 14.760 89.840 15.300 90.340 ;
        RECT 18.160 89.840 18.700 90.340 ;
        RECT 14.095 85.985 14.150 86.395 ;
        RECT 14.450 85.985 14.505 86.395 ;
        RECT 14.095 91.185 14.150 91.595 ;
        RECT 14.450 91.185 14.505 91.595 ;
        RECT 17.495 91.185 17.550 91.595 ;
        RECT 17.850 91.185 17.905 91.595 ;
        RECT 14.095 88.585 14.150 88.995 ;
        RECT 14.450 88.585 14.505 88.995 ;
        RECT 17.495 88.585 17.550 88.995 ;
        RECT 17.850 88.585 17.905 88.995 ;
        RECT 16.460 91.140 17.000 91.640 ;
        RECT 19.860 91.140 20.400 91.640 ;
        RECT 15.795 87.285 15.850 87.695 ;
        RECT 16.150 87.285 16.205 87.695 ;
        RECT 14.150 92.300 14.570 93.700 ;
        RECT 15.850 92.300 16.270 93.700 ;
        RECT 17.550 92.300 17.970 93.700 ;
        RECT 19.250 92.300 19.670 93.700 ;
        RECT 19.195 87.285 19.250 87.695 ;
        RECT 19.550 87.285 19.605 87.695 ;
        RECT 16.460 88.540 17.000 89.040 ;
        RECT 19.860 88.540 20.400 89.040 ;
        RECT 15.685 94.090 16.095 94.135 ;
        RECT 14.840 95.130 15.285 95.690 ;
        RECT 16.540 95.130 16.985 95.690 ;
        RECT 18.240 95.130 18.685 95.690 ;
        RECT 19.940 95.130 20.385 95.690 ;
        RECT 17.495 85.985 17.550 86.395 ;
        RECT 17.850 85.985 17.905 86.395 ;
        RECT 15.795 89.885 15.850 90.295 ;
        RECT 16.150 89.885 16.205 90.295 ;
        RECT 18.160 82.040 18.700 82.540 ;
        RECT 14.095 83.385 14.150 83.795 ;
        RECT 14.450 83.385 14.505 83.795 ;
        RECT 17.495 83.385 17.550 83.795 ;
        RECT 17.850 83.385 17.905 83.795 ;
        RECT 16.460 83.340 17.000 83.840 ;
        RECT 19.860 83.340 20.400 83.840 ;
        RECT 15.795 72.985 15.850 73.395 ;
        RECT 16.150 72.985 16.205 73.395 ;
        RECT 19.195 72.985 19.250 73.395 ;
        RECT 19.550 72.985 19.605 73.395 ;
        RECT 14.760 72.940 15.300 73.440 ;
        RECT 18.160 72.940 18.700 73.440 ;
        RECT 14.095 74.285 14.150 74.695 ;
        RECT 14.450 74.285 14.505 74.695 ;
        RECT 17.495 74.285 17.550 74.695 ;
        RECT 17.850 74.285 17.905 74.695 ;
        RECT 16.460 74.240 17.000 74.740 ;
        RECT 19.860 74.240 20.400 74.740 ;
        RECT 15.795 75.585 15.850 75.995 ;
        RECT 16.150 75.585 16.205 75.995 ;
        RECT 19.195 75.585 19.250 75.995 ;
        RECT 19.550 75.585 19.605 75.995 ;
        RECT 14.760 75.540 15.300 76.040 ;
        RECT 18.160 75.540 18.700 76.040 ;
        RECT 14.095 76.885 14.150 77.295 ;
        RECT 14.450 76.885 14.505 77.295 ;
        RECT 17.495 76.885 17.550 77.295 ;
        RECT 17.850 76.885 17.905 77.295 ;
        RECT 16.460 76.840 17.000 77.340 ;
        RECT 19.860 76.840 20.400 77.340 ;
        RECT 15.795 78.185 15.850 78.595 ;
        RECT 16.150 78.185 16.205 78.595 ;
        RECT 19.195 78.185 19.250 78.595 ;
        RECT 19.550 78.185 19.605 78.595 ;
        RECT 14.760 78.140 15.300 78.640 ;
        RECT 18.160 78.140 18.700 78.640 ;
        RECT 14.095 79.485 14.150 79.895 ;
        RECT 14.450 79.485 14.505 79.895 ;
        RECT 17.495 79.485 17.550 79.895 ;
        RECT 17.850 79.485 17.905 79.895 ;
        RECT 16.460 79.440 17.000 79.940 ;
        RECT 19.860 79.440 20.400 79.940 ;
        RECT 15.795 82.085 15.850 82.495 ;
        RECT 16.150 82.085 16.205 82.495 ;
        RECT 19.195 82.085 19.250 82.495 ;
        RECT 19.550 82.085 19.605 82.495 ;
        RECT 14.760 82.040 15.300 82.540 ;
        RECT 21.250 83.385 21.305 83.795 ;
        RECT 24.295 83.385 24.350 83.795 ;
        RECT 24.650 83.385 24.705 83.795 ;
        RECT 23.260 76.840 23.800 77.340 ;
        RECT 26.660 76.840 27.200 77.340 ;
        RECT 23.260 83.340 23.800 83.840 ;
        RECT 26.660 83.340 27.200 83.840 ;
        RECT 25.995 72.985 26.050 73.395 ;
        RECT 26.350 72.985 26.405 73.395 ;
        RECT 22.595 72.985 22.650 73.395 ;
        RECT 22.950 72.985 23.005 73.395 ;
        RECT 22.595 78.185 22.650 78.595 ;
        RECT 22.950 78.185 23.005 78.595 ;
        RECT 25.995 78.185 26.050 78.595 ;
        RECT 26.350 78.185 26.405 78.595 ;
        RECT 22.595 75.585 22.650 75.995 ;
        RECT 22.950 75.585 23.005 75.995 ;
        RECT 21.560 78.140 22.100 78.640 ;
        RECT 24.960 78.140 25.500 78.640 ;
        RECT 25.995 75.585 26.050 75.995 ;
        RECT 26.350 75.585 26.405 75.995 ;
        RECT 20.895 74.285 20.950 74.695 ;
        RECT 21.250 74.285 21.305 74.695 ;
        RECT 20.895 79.485 20.950 79.895 ;
        RECT 21.250 79.485 21.305 79.895 ;
        RECT 24.295 79.485 24.350 79.895 ;
        RECT 24.650 79.485 24.705 79.895 ;
        RECT 21.560 75.540 22.100 76.040 ;
        RECT 24.960 75.540 25.500 76.040 ;
        RECT 23.260 79.440 23.800 79.940 ;
        RECT 26.660 79.440 27.200 79.940 ;
        RECT 24.295 74.285 24.350 74.695 ;
        RECT 24.650 74.285 24.705 74.695 ;
        RECT 21.560 72.940 22.100 73.440 ;
        RECT 24.960 72.940 25.500 73.440 ;
        RECT 22.595 82.085 22.650 82.495 ;
        RECT 22.950 82.085 23.005 82.495 ;
        RECT 25.995 82.085 26.050 82.495 ;
        RECT 26.350 82.085 26.405 82.495 ;
        RECT 20.895 76.885 20.950 77.295 ;
        RECT 21.250 76.885 21.305 77.295 ;
        RECT 21.560 82.040 22.100 82.540 ;
        RECT 24.960 82.040 25.500 82.540 ;
        RECT 24.295 76.885 24.350 77.295 ;
        RECT 24.650 76.885 24.705 77.295 ;
        RECT 23.260 74.240 23.800 74.740 ;
        RECT 26.660 74.240 27.200 74.740 ;
        RECT 20.895 83.385 20.950 83.795 ;
        RECT 2.195 84.685 2.250 85.095 ;
        RECT 2.550 84.685 2.605 85.095 ;
        RECT 5.595 84.685 5.650 85.095 ;
        RECT 5.950 84.685 6.005 85.095 ;
        RECT 8.995 84.685 9.050 85.095 ;
        RECT 9.350 84.685 9.405 85.095 ;
        RECT 12.395 84.685 12.450 85.095 ;
        RECT 12.750 84.685 12.805 85.095 ;
        RECT 1.160 84.640 1.700 85.140 ;
        RECT 4.560 84.640 5.100 85.140 ;
        RECT 7.960 84.640 8.500 85.140 ;
        RECT 11.360 84.640 11.900 85.140 ;
        RECT 7.295 85.985 7.350 86.395 ;
        RECT 7.650 85.985 7.705 86.395 ;
        RECT 10.695 85.985 10.750 86.395 ;
        RECT 11.050 85.985 11.105 86.395 ;
        RECT 9.660 85.940 10.200 86.440 ;
        RECT 13.060 85.940 13.600 86.440 ;
        RECT 8.995 87.285 9.050 87.695 ;
        RECT 9.350 87.285 9.405 87.695 ;
        RECT 12.395 87.285 12.450 87.695 ;
        RECT 12.750 87.285 12.805 87.695 ;
        RECT 7.960 87.240 8.500 87.740 ;
        RECT 11.360 87.240 11.900 87.740 ;
        RECT 7.295 88.585 7.350 88.995 ;
        RECT 7.650 88.585 7.705 88.995 ;
        RECT 10.695 88.585 10.750 88.995 ;
        RECT 11.050 88.585 11.105 88.995 ;
        RECT 9.660 88.540 10.200 89.040 ;
        RECT 13.060 88.540 13.600 89.040 ;
        RECT 8.995 89.885 9.050 90.295 ;
        RECT 9.350 89.885 9.405 90.295 ;
        RECT 12.395 89.885 12.450 90.295 ;
        RECT 12.750 89.885 12.805 90.295 ;
        RECT 7.960 89.840 8.500 90.340 ;
        RECT 11.360 89.840 11.900 90.340 ;
        RECT 7.295 91.185 7.350 91.595 ;
        RECT 7.650 91.185 7.705 91.595 ;
        RECT 10.695 91.185 10.750 91.595 ;
        RECT 11.050 91.185 11.105 91.595 ;
        RECT 9.660 91.140 10.200 91.640 ;
        RECT 13.060 91.140 13.600 91.640 ;
        RECT 7.350 92.300 7.770 93.700 ;
        RECT 9.050 92.300 9.470 93.700 ;
        RECT 10.750 92.300 11.170 93.700 ;
        RECT 12.450 92.300 12.870 93.700 ;
        RECT 8.040 95.130 8.485 95.690 ;
        RECT 9.740 95.130 10.185 95.690 ;
        RECT 11.440 95.130 11.885 95.690 ;
        RECT 13.140 95.130 13.585 95.690 ;
        RECT 7.930 96.380 8.470 96.920 ;
        RECT 5.950 89.885 6.005 90.295 ;
        RECT 2.860 85.940 3.400 86.440 ;
        RECT 6.260 85.940 6.800 86.440 ;
        RECT 1.160 87.240 1.700 87.740 ;
        RECT 4.560 87.240 5.100 87.740 ;
        RECT 1.160 89.840 1.700 90.340 ;
        RECT 4.560 89.840 5.100 90.340 ;
        RECT 0.495 85.985 0.550 86.395 ;
        RECT 0.850 85.985 0.905 86.395 ;
        RECT 0.495 91.185 0.550 91.595 ;
        RECT 0.850 91.185 0.905 91.595 ;
        RECT 3.895 91.185 3.950 91.595 ;
        RECT 4.250 91.185 4.305 91.595 ;
        RECT 0.495 88.585 0.550 88.995 ;
        RECT 0.850 88.585 0.905 88.995 ;
        RECT 3.895 88.585 3.950 88.995 ;
        RECT 4.250 88.585 4.305 88.995 ;
        RECT 2.860 91.140 3.400 91.640 ;
        RECT 6.260 91.140 6.800 91.640 ;
        RECT 2.195 87.285 2.250 87.695 ;
        RECT 2.550 87.285 2.605 87.695 ;
        RECT 0.550 92.300 0.970 93.700 ;
        RECT 2.250 92.300 2.670 93.700 ;
        RECT 3.950 92.300 4.370 93.700 ;
        RECT 5.650 92.300 6.070 93.700 ;
        RECT 5.595 87.285 5.650 87.695 ;
        RECT 5.950 87.285 6.005 87.695 ;
        RECT 2.860 88.540 3.400 89.040 ;
        RECT 6.260 88.540 6.800 89.040 ;
        RECT 1.240 95.130 1.685 95.690 ;
        RECT 2.940 95.130 3.385 95.690 ;
        RECT 4.640 95.130 5.085 95.690 ;
        RECT 6.340 95.130 6.785 95.690 ;
        RECT 3.895 85.985 3.950 86.395 ;
        RECT 4.250 85.985 4.305 86.395 ;
        RECT 2.195 89.885 2.250 90.295 ;
        RECT 2.550 89.885 2.605 90.295 ;
        RECT 5.595 89.885 5.650 90.295 ;
        RECT 2.195 72.985 2.250 73.395 ;
        RECT 2.195 75.585 2.250 75.995 ;
        RECT 0.495 76.885 0.550 77.295 ;
        RECT 0.850 76.885 0.905 77.295 ;
        RECT 3.895 76.885 3.950 77.295 ;
        RECT 4.250 76.885 4.305 77.295 ;
        RECT 2.550 75.585 2.605 75.995 ;
        RECT 5.595 75.585 5.650 75.995 ;
        RECT 0.495 74.285 0.550 74.695 ;
        RECT 0.850 74.285 0.905 74.695 ;
        RECT 3.895 74.285 3.950 74.695 ;
        RECT 4.250 74.285 4.305 74.695 ;
        RECT 5.950 75.585 6.005 75.995 ;
        RECT 1.160 75.540 1.700 76.040 ;
        RECT 1.160 82.040 1.700 82.540 ;
        RECT 4.560 82.040 5.100 82.540 ;
        RECT 4.560 75.540 5.100 76.040 ;
        RECT 2.860 79.440 3.400 79.940 ;
        RECT 6.260 79.440 6.800 79.940 ;
        RECT 2.550 72.985 2.605 73.395 ;
        RECT 1.160 72.940 1.700 73.440 ;
        RECT 4.560 72.940 5.100 73.440 ;
        RECT 2.195 78.185 2.250 78.595 ;
        RECT 2.550 78.185 2.605 78.595 ;
        RECT 5.595 78.185 5.650 78.595 ;
        RECT 5.950 78.185 6.005 78.595 ;
        RECT 5.595 72.985 5.650 73.395 ;
        RECT 5.950 72.985 6.005 73.395 ;
        RECT 0.495 79.485 0.550 79.895 ;
        RECT 0.850 79.485 0.905 79.895 ;
        RECT 0.495 83.385 0.550 83.795 ;
        RECT 0.850 83.385 0.905 83.795 ;
        RECT 3.895 83.385 3.950 83.795 ;
        RECT 4.250 83.385 4.305 83.795 ;
        RECT 2.860 74.240 3.400 74.740 ;
        RECT 3.895 79.485 3.950 79.895 ;
        RECT 4.250 79.485 4.305 79.895 ;
        RECT 6.260 83.340 6.800 83.840 ;
        RECT 2.195 82.085 2.250 82.495 ;
        RECT 2.550 82.085 2.605 82.495 ;
        RECT 5.595 82.085 5.650 82.495 ;
        RECT 5.950 82.085 6.005 82.495 ;
        RECT 1.160 78.140 1.700 78.640 ;
        RECT 6.260 74.240 6.800 74.740 ;
        RECT 2.860 76.840 3.400 77.340 ;
        RECT 6.260 76.840 6.800 77.340 ;
        RECT 2.860 83.340 3.400 83.840 ;
        RECT 4.560 78.140 5.100 78.640 ;
        RECT 10.695 76.885 10.750 77.295 ;
        RECT 11.050 76.885 11.105 77.295 ;
        RECT 7.295 74.285 7.350 74.695 ;
        RECT 7.650 74.285 7.705 74.695 ;
        RECT 7.960 82.040 8.500 82.540 ;
        RECT 11.360 82.040 11.900 82.540 ;
        RECT 10.695 74.285 10.750 74.695 ;
        RECT 11.050 74.285 11.105 74.695 ;
        RECT 9.660 83.340 10.200 83.840 ;
        RECT 13.060 83.340 13.600 83.840 ;
        RECT 8.995 78.185 9.050 78.595 ;
        RECT 9.350 78.185 9.405 78.595 ;
        RECT 7.960 72.940 8.500 73.440 ;
        RECT 11.360 72.940 11.900 73.440 ;
        RECT 8.995 75.585 9.050 75.995 ;
        RECT 9.350 75.585 9.405 75.995 ;
        RECT 12.395 75.585 12.450 75.995 ;
        RECT 12.750 75.585 12.805 75.995 ;
        RECT 8.995 82.085 9.050 82.495 ;
        RECT 9.350 82.085 9.405 82.495 ;
        RECT 12.395 82.085 12.450 82.495 ;
        RECT 12.750 82.085 12.805 82.495 ;
        RECT 7.295 79.485 7.350 79.895 ;
        RECT 7.650 79.485 7.705 79.895 ;
        RECT 7.960 75.540 8.500 76.040 ;
        RECT 11.360 75.540 11.900 76.040 ;
        RECT 7.295 83.385 7.350 83.795 ;
        RECT 7.650 83.385 7.705 83.795 ;
        RECT 10.695 83.385 10.750 83.795 ;
        RECT 11.050 83.385 11.105 83.795 ;
        RECT 10.695 79.485 10.750 79.895 ;
        RECT 11.050 79.485 11.105 79.895 ;
        RECT 9.660 79.440 10.200 79.940 ;
        RECT 13.060 79.440 13.600 79.940 ;
        RECT 12.395 78.185 12.450 78.595 ;
        RECT 12.750 78.185 12.805 78.595 ;
        RECT 7.960 78.140 8.500 78.640 ;
        RECT 11.360 78.140 11.900 78.640 ;
        RECT 8.995 72.985 9.050 73.395 ;
        RECT 9.350 72.985 9.405 73.395 ;
        RECT 9.660 74.240 10.200 74.740 ;
        RECT 13.060 74.240 13.600 74.740 ;
        RECT 12.395 72.985 12.450 73.395 ;
        RECT 12.750 72.985 12.805 73.395 ;
        RECT 9.660 76.840 10.200 77.340 ;
        RECT 13.060 76.840 13.600 77.340 ;
        RECT 7.295 76.885 7.350 77.295 ;
        RECT 7.650 76.885 7.705 77.295 ;
        RECT 7.295 65.185 7.350 65.595 ;
        RECT 7.650 65.185 7.705 65.595 ;
        RECT 10.695 65.185 10.750 65.595 ;
        RECT 11.050 65.185 11.105 65.595 ;
        RECT 7.295 67.785 7.350 68.195 ;
        RECT 7.650 67.785 7.705 68.195 ;
        RECT 10.695 67.785 10.750 68.195 ;
        RECT 11.050 67.785 11.105 68.195 ;
        RECT 8.995 61.285 9.050 61.695 ;
        RECT 9.350 61.285 9.405 61.695 ;
        RECT 12.395 61.285 12.450 61.695 ;
        RECT 12.750 61.285 12.805 61.695 ;
        RECT 7.295 62.585 7.350 62.995 ;
        RECT 7.650 62.585 7.705 62.995 ;
        RECT 10.695 62.585 10.750 62.995 ;
        RECT 11.050 62.585 11.105 62.995 ;
        RECT 8.995 63.885 9.050 64.295 ;
        RECT 9.350 63.885 9.405 64.295 ;
        RECT 12.395 63.885 12.450 64.295 ;
        RECT 12.750 63.885 12.805 64.295 ;
        RECT 9.660 67.740 10.200 68.240 ;
        RECT 13.060 67.740 13.600 68.240 ;
        RECT 9.660 65.140 10.200 65.640 ;
        RECT 13.060 65.140 13.600 65.640 ;
        RECT 7.960 61.240 8.500 61.740 ;
        RECT 11.360 61.240 11.900 61.740 ;
        RECT 8.995 70.385 9.050 70.795 ;
        RECT 9.350 70.385 9.405 70.795 ;
        RECT 12.395 70.385 12.450 70.795 ;
        RECT 12.750 70.385 12.805 70.795 ;
        RECT 8.995 66.485 9.050 66.895 ;
        RECT 9.350 66.485 9.405 66.895 ;
        RECT 12.395 66.485 12.450 66.895 ;
        RECT 12.750 66.485 12.805 66.895 ;
        RECT 7.960 70.340 8.500 70.840 ;
        RECT 11.360 70.340 11.900 70.840 ;
        RECT 7.960 63.840 8.500 64.340 ;
        RECT 11.360 63.840 11.900 64.340 ;
        RECT 9.660 62.540 10.200 63.040 ;
        RECT 13.060 62.540 13.600 63.040 ;
        RECT 7.295 71.685 7.350 72.095 ;
        RECT 7.650 71.685 7.705 72.095 ;
        RECT 10.695 71.685 10.750 72.095 ;
        RECT 11.050 71.685 11.105 72.095 ;
        RECT 7.960 66.440 8.500 66.940 ;
        RECT 11.360 66.440 11.900 66.940 ;
        RECT 9.660 71.640 10.200 72.140 ;
        RECT 13.060 71.640 13.600 72.140 ;
        RECT 1.160 61.240 1.700 61.740 ;
        RECT 4.560 61.240 5.100 61.740 ;
        RECT 0.495 62.585 0.550 62.995 ;
        RECT 0.850 62.585 0.905 62.995 ;
        RECT 2.195 70.385 2.250 70.795 ;
        RECT 2.550 70.385 2.605 70.795 ;
        RECT 5.595 70.385 5.650 70.795 ;
        RECT 5.950 70.385 6.005 70.795 ;
        RECT 3.895 62.585 3.950 62.995 ;
        RECT 4.250 62.585 4.305 62.995 ;
        RECT 0.495 67.785 0.550 68.195 ;
        RECT 0.850 67.785 0.905 68.195 ;
        RECT 2.195 66.485 2.250 66.895 ;
        RECT 2.550 66.485 2.605 66.895 ;
        RECT 5.595 66.485 5.650 66.895 ;
        RECT 5.950 66.485 6.005 66.895 ;
        RECT 3.895 67.785 3.950 68.195 ;
        RECT 4.250 67.785 4.305 68.195 ;
        RECT 2.195 63.885 2.250 64.295 ;
        RECT 2.550 63.885 2.605 64.295 ;
        RECT 1.160 70.340 1.700 70.840 ;
        RECT 4.560 70.340 5.100 70.840 ;
        RECT 5.595 63.885 5.650 64.295 ;
        RECT 5.950 63.885 6.005 64.295 ;
        RECT 1.160 63.840 1.700 64.340 ;
        RECT 4.560 63.840 5.100 64.340 ;
        RECT 0.495 65.185 0.550 65.595 ;
        RECT 0.850 65.185 0.905 65.595 ;
        RECT 2.860 62.540 3.400 63.040 ;
        RECT 6.260 62.540 6.800 63.040 ;
        RECT 3.895 65.185 3.950 65.595 ;
        RECT 4.250 65.185 4.305 65.595 ;
        RECT 0.495 71.685 0.550 72.095 ;
        RECT 0.850 71.685 0.905 72.095 ;
        RECT 3.895 71.685 3.950 72.095 ;
        RECT 4.250 71.685 4.305 72.095 ;
        RECT 2.860 67.740 3.400 68.240 ;
        RECT 6.260 67.740 6.800 68.240 ;
        RECT 2.195 61.285 2.250 61.695 ;
        RECT 2.550 61.285 2.605 61.695 ;
        RECT 1.160 66.440 1.700 66.940 ;
        RECT 4.560 66.440 5.100 66.940 ;
        RECT 2.860 65.140 3.400 65.640 ;
        RECT 6.260 65.140 6.800 65.640 ;
        RECT 2.860 71.640 3.400 72.140 ;
        RECT 6.260 71.640 6.800 72.140 ;
        RECT 5.595 61.285 5.650 61.695 ;
        RECT 5.950 61.285 6.005 61.695 ;
        RECT 1.160 58.640 1.700 59.140 ;
        RECT 4.560 58.640 5.100 59.140 ;
        RECT 1.160 49.540 1.700 50.040 ;
        RECT 4.560 49.540 5.100 50.040 ;
        RECT 2.195 58.685 2.250 59.095 ;
        RECT 2.550 58.685 2.605 59.095 ;
        RECT 5.595 58.685 5.650 59.095 ;
        RECT 5.950 58.685 6.005 59.095 ;
        RECT 2.860 50.840 3.400 51.340 ;
        RECT 6.260 50.840 6.800 51.340 ;
        RECT 2.195 49.585 2.250 49.995 ;
        RECT 2.550 49.585 2.605 49.995 ;
        RECT 5.595 49.585 5.650 49.995 ;
        RECT 5.950 49.585 6.005 49.995 ;
        RECT 1.160 54.740 1.700 55.240 ;
        RECT 4.560 54.740 5.100 55.240 ;
        RECT 2.195 54.785 2.250 55.195 ;
        RECT 2.550 54.785 2.605 55.195 ;
        RECT 5.595 54.785 5.650 55.195 ;
        RECT 5.950 54.785 6.005 55.195 ;
        RECT 0.495 59.985 0.550 60.395 ;
        RECT 0.850 59.985 0.905 60.395 ;
        RECT 3.895 59.985 3.950 60.395 ;
        RECT 4.250 59.985 4.305 60.395 ;
        RECT 2.860 56.040 3.400 56.540 ;
        RECT 6.260 56.040 6.800 56.540 ;
        RECT 1.160 52.140 1.700 52.640 ;
        RECT 4.560 52.140 5.100 52.640 ;
        RECT 0.495 56.085 0.550 56.495 ;
        RECT 0.850 56.085 0.905 56.495 ;
        RECT 3.895 56.085 3.950 56.495 ;
        RECT 4.250 56.085 4.305 56.495 ;
        RECT 2.195 52.185 2.250 52.595 ;
        RECT 2.550 52.185 2.605 52.595 ;
        RECT 5.595 52.185 5.650 52.595 ;
        RECT 5.950 52.185 6.005 52.595 ;
        RECT 0.495 50.885 0.550 51.295 ;
        RECT 0.850 50.885 0.905 51.295 ;
        RECT 3.895 50.885 3.950 51.295 ;
        RECT 4.250 50.885 4.305 51.295 ;
        RECT 0.495 53.485 0.550 53.895 ;
        RECT 0.850 53.485 0.905 53.895 ;
        RECT 3.895 53.485 3.950 53.895 ;
        RECT 4.250 53.485 4.305 53.895 ;
        RECT 2.860 53.440 3.400 53.940 ;
        RECT 6.260 53.440 6.800 53.940 ;
        RECT 2.860 59.940 3.400 60.440 ;
        RECT 6.260 59.940 6.800 60.440 ;
        RECT 10.695 59.985 10.750 60.395 ;
        RECT 11.050 59.985 11.105 60.395 ;
        RECT 10.695 56.085 10.750 56.495 ;
        RECT 11.050 56.085 11.105 56.495 ;
        RECT 7.960 54.740 8.500 55.240 ;
        RECT 11.360 54.740 11.900 55.240 ;
        RECT 7.960 49.540 8.500 50.040 ;
        RECT 11.360 49.540 11.900 50.040 ;
        RECT 10.695 53.485 10.750 53.895 ;
        RECT 11.050 53.485 11.105 53.895 ;
        RECT 8.995 54.785 9.050 55.195 ;
        RECT 9.350 54.785 9.405 55.195 ;
        RECT 12.395 54.785 12.450 55.195 ;
        RECT 12.750 54.785 12.805 55.195 ;
        RECT 7.960 52.140 8.500 52.640 ;
        RECT 11.360 52.140 11.900 52.640 ;
        RECT 9.660 56.040 10.200 56.540 ;
        RECT 13.060 56.040 13.600 56.540 ;
        RECT 8.995 49.585 9.050 49.995 ;
        RECT 9.350 49.585 9.405 49.995 ;
        RECT 8.995 52.185 9.050 52.595 ;
        RECT 9.350 52.185 9.405 52.595 ;
        RECT 12.395 52.185 12.450 52.595 ;
        RECT 12.750 52.185 12.805 52.595 ;
        RECT 12.395 49.585 12.450 49.995 ;
        RECT 12.750 49.585 12.805 49.995 ;
        RECT 7.295 50.885 7.350 51.295 ;
        RECT 7.650 50.885 7.705 51.295 ;
        RECT 7.960 58.640 8.500 59.140 ;
        RECT 11.360 58.640 11.900 59.140 ;
        RECT 10.695 50.885 10.750 51.295 ;
        RECT 11.050 50.885 11.105 51.295 ;
        RECT 8.995 58.685 9.050 59.095 ;
        RECT 9.350 58.685 9.405 59.095 ;
        RECT 12.395 58.685 12.450 59.095 ;
        RECT 12.750 58.685 12.805 59.095 ;
        RECT 7.295 56.085 7.350 56.495 ;
        RECT 7.650 56.085 7.705 56.495 ;
        RECT 7.295 53.485 7.350 53.895 ;
        RECT 9.660 50.840 10.200 51.340 ;
        RECT 13.060 50.840 13.600 51.340 ;
        RECT 9.660 53.440 10.200 53.940 ;
        RECT 13.060 53.440 13.600 53.940 ;
        RECT 7.295 59.985 7.350 60.395 ;
        RECT 7.650 59.985 7.705 60.395 ;
        RECT 9.660 59.940 10.200 60.440 ;
        RECT 13.060 59.940 13.600 60.440 ;
        RECT 7.650 53.485 7.705 53.895 ;
        RECT 24.295 62.585 24.350 62.995 ;
        RECT 24.650 62.585 24.705 62.995 ;
        RECT 23.260 67.740 23.800 68.240 ;
        RECT 26.660 67.740 27.200 68.240 ;
        RECT 22.595 66.485 22.650 66.895 ;
        RECT 22.950 66.485 23.005 66.895 ;
        RECT 25.995 66.485 26.050 66.895 ;
        RECT 26.350 66.485 26.405 66.895 ;
        RECT 23.260 62.540 23.800 63.040 ;
        RECT 26.660 62.540 27.200 63.040 ;
        RECT 22.595 61.285 22.650 61.695 ;
        RECT 22.950 61.285 23.005 61.695 ;
        RECT 25.995 61.285 26.050 61.695 ;
        RECT 26.350 61.285 26.405 61.695 ;
        RECT 20.895 65.185 20.950 65.595 ;
        RECT 21.250 65.185 21.305 65.595 ;
        RECT 24.295 65.185 24.350 65.595 ;
        RECT 24.650 65.185 24.705 65.595 ;
        RECT 21.560 61.240 22.100 61.740 ;
        RECT 24.960 61.240 25.500 61.740 ;
        RECT 22.595 70.385 22.650 70.795 ;
        RECT 22.950 70.385 23.005 70.795 ;
        RECT 25.995 70.385 26.050 70.795 ;
        RECT 26.350 70.385 26.405 70.795 ;
        RECT 23.260 71.640 23.800 72.140 ;
        RECT 26.660 71.640 27.200 72.140 ;
        RECT 21.560 66.440 22.100 66.940 ;
        RECT 24.960 66.440 25.500 66.940 ;
        RECT 21.560 70.340 22.100 70.840 ;
        RECT 24.960 70.340 25.500 70.840 ;
        RECT 21.560 63.840 22.100 64.340 ;
        RECT 24.960 63.840 25.500 64.340 ;
        RECT 23.260 65.140 23.800 65.640 ;
        RECT 26.660 65.140 27.200 65.640 ;
        RECT 20.895 67.785 20.950 68.195 ;
        RECT 21.250 67.785 21.305 68.195 ;
        RECT 24.295 67.785 24.350 68.195 ;
        RECT 24.650 67.785 24.705 68.195 ;
        RECT 20.895 71.685 20.950 72.095 ;
        RECT 21.250 71.685 21.305 72.095 ;
        RECT 24.295 71.685 24.350 72.095 ;
        RECT 24.650 71.685 24.705 72.095 ;
        RECT 22.595 63.885 22.650 64.295 ;
        RECT 22.950 63.885 23.005 64.295 ;
        RECT 25.995 63.885 26.050 64.295 ;
        RECT 26.350 63.885 26.405 64.295 ;
        RECT 20.895 62.585 20.950 62.995 ;
        RECT 21.250 62.585 21.305 62.995 ;
        RECT 16.460 62.540 17.000 63.040 ;
        RECT 19.860 62.540 20.400 63.040 ;
        RECT 15.795 61.285 15.850 61.695 ;
        RECT 16.150 61.285 16.205 61.695 ;
        RECT 19.195 61.285 19.250 61.695 ;
        RECT 19.550 61.285 19.605 61.695 ;
        RECT 14.760 70.340 15.300 70.840 ;
        RECT 18.160 70.340 18.700 70.840 ;
        RECT 15.795 66.485 15.850 66.895 ;
        RECT 16.150 66.485 16.205 66.895 ;
        RECT 14.760 63.840 15.300 64.340 ;
        RECT 18.160 63.840 18.700 64.340 ;
        RECT 14.760 61.240 15.300 61.740 ;
        RECT 18.160 61.240 18.700 61.740 ;
        RECT 16.460 65.140 17.000 65.640 ;
        RECT 19.860 65.140 20.400 65.640 ;
        RECT 19.195 66.485 19.250 66.895 ;
        RECT 19.550 66.485 19.605 66.895 ;
        RECT 14.095 62.585 14.150 62.995 ;
        RECT 14.450 62.585 14.505 62.995 ;
        RECT 17.495 62.585 17.550 62.995 ;
        RECT 17.850 62.585 17.905 62.995 ;
        RECT 14.095 67.785 14.150 68.195 ;
        RECT 14.450 67.785 14.505 68.195 ;
        RECT 17.495 67.785 17.550 68.195 ;
        RECT 17.850 67.785 17.905 68.195 ;
        RECT 15.795 70.385 15.850 70.795 ;
        RECT 16.150 70.385 16.205 70.795 ;
        RECT 19.195 70.385 19.250 70.795 ;
        RECT 19.550 70.385 19.605 70.795 ;
        RECT 14.095 71.685 14.150 72.095 ;
        RECT 14.450 71.685 14.505 72.095 ;
        RECT 17.495 71.685 17.550 72.095 ;
        RECT 17.850 71.685 17.905 72.095 ;
        RECT 16.460 67.740 17.000 68.240 ;
        RECT 19.860 67.740 20.400 68.240 ;
        RECT 14.095 65.185 14.150 65.595 ;
        RECT 14.450 65.185 14.505 65.595 ;
        RECT 15.795 63.885 15.850 64.295 ;
        RECT 16.150 63.885 16.205 64.295 ;
        RECT 19.195 63.885 19.250 64.295 ;
        RECT 19.550 63.885 19.605 64.295 ;
        RECT 16.460 71.640 17.000 72.140 ;
        RECT 19.860 71.640 20.400 72.140 ;
        RECT 17.495 65.185 17.550 65.595 ;
        RECT 17.850 65.185 17.905 65.595 ;
        RECT 14.760 66.440 15.300 66.940 ;
        RECT 18.160 66.440 18.700 66.940 ;
        RECT 15.795 58.685 15.850 59.095 ;
        RECT 16.150 58.685 16.205 59.095 ;
        RECT 14.095 56.085 14.150 56.495 ;
        RECT 14.450 56.085 14.505 56.495 ;
        RECT 15.795 49.585 15.850 49.995 ;
        RECT 16.150 49.585 16.205 49.995 ;
        RECT 19.195 49.585 19.250 49.995 ;
        RECT 19.550 49.585 19.605 49.995 ;
        RECT 17.495 56.085 17.550 56.495 ;
        RECT 17.850 56.085 17.905 56.495 ;
        RECT 15.795 54.785 15.850 55.195 ;
        RECT 16.150 54.785 16.205 55.195 ;
        RECT 19.195 54.785 19.250 55.195 ;
        RECT 19.550 54.785 19.605 55.195 ;
        RECT 14.095 59.985 14.150 60.395 ;
        RECT 14.450 59.985 14.505 60.395 ;
        RECT 14.095 50.885 14.150 51.295 ;
        RECT 14.450 50.885 14.505 51.295 ;
        RECT 17.495 50.885 17.550 51.295 ;
        RECT 17.850 50.885 17.905 51.295 ;
        RECT 17.495 59.985 17.550 60.395 ;
        RECT 17.850 59.985 17.905 60.395 ;
        RECT 16.460 56.040 17.000 56.540 ;
        RECT 19.860 56.040 20.400 56.540 ;
        RECT 19.195 58.685 19.250 59.095 ;
        RECT 19.550 58.685 19.605 59.095 ;
        RECT 14.760 52.140 15.300 52.640 ;
        RECT 18.160 52.140 18.700 52.640 ;
        RECT 14.095 53.485 14.150 53.895 ;
        RECT 14.450 53.485 14.505 53.895 ;
        RECT 17.495 53.485 17.550 53.895 ;
        RECT 17.850 53.485 17.905 53.895 ;
        RECT 14.760 54.740 15.300 55.240 ;
        RECT 18.160 54.740 18.700 55.240 ;
        RECT 14.760 58.640 15.300 59.140 ;
        RECT 18.160 58.640 18.700 59.140 ;
        RECT 14.760 49.540 15.300 50.040 ;
        RECT 18.160 49.540 18.700 50.040 ;
        RECT 15.795 52.185 15.850 52.595 ;
        RECT 16.460 53.440 17.000 53.940 ;
        RECT 19.860 53.440 20.400 53.940 ;
        RECT 16.150 52.185 16.205 52.595 ;
        RECT 19.195 52.185 19.250 52.595 ;
        RECT 19.550 52.185 19.605 52.595 ;
        RECT 16.460 50.840 17.000 51.340 ;
        RECT 16.460 59.940 17.000 60.440 ;
        RECT 19.860 59.940 20.400 60.440 ;
        RECT 19.860 50.840 20.400 51.340 ;
        RECT 25.995 49.585 26.050 49.995 ;
        RECT 26.350 49.585 26.405 49.995 ;
        RECT 24.295 56.085 24.350 56.495 ;
        RECT 24.650 56.085 24.705 56.495 ;
        RECT 25.995 52.185 26.050 52.595 ;
        RECT 26.350 52.185 26.405 52.595 ;
        RECT 21.560 58.640 22.100 59.140 ;
        RECT 24.960 58.640 25.500 59.140 ;
        RECT 22.595 54.785 22.650 55.195 ;
        RECT 22.950 54.785 23.005 55.195 ;
        RECT 25.995 54.785 26.050 55.195 ;
        RECT 26.350 54.785 26.405 55.195 ;
        RECT 21.560 52.140 22.100 52.640 ;
        RECT 24.960 52.140 25.500 52.640 ;
        RECT 23.260 50.840 23.800 51.340 ;
        RECT 26.660 50.840 27.200 51.340 ;
        RECT 21.560 49.540 22.100 50.040 ;
        RECT 24.960 49.540 25.500 50.040 ;
        RECT 20.895 53.485 20.950 53.895 ;
        RECT 21.250 53.485 21.305 53.895 ;
        RECT 24.295 53.485 24.350 53.895 ;
        RECT 24.650 53.485 24.705 53.895 ;
        RECT 20.895 50.885 20.950 51.295 ;
        RECT 21.250 50.885 21.305 51.295 ;
        RECT 24.295 50.885 24.350 51.295 ;
        RECT 24.650 50.885 24.705 51.295 ;
        RECT 20.895 59.985 20.950 60.395 ;
        RECT 21.250 59.985 21.305 60.395 ;
        RECT 21.560 54.740 22.100 55.240 ;
        RECT 24.960 54.740 25.500 55.240 ;
        RECT 24.295 59.985 24.350 60.395 ;
        RECT 24.650 59.985 24.705 60.395 ;
        RECT 22.595 58.685 22.650 59.095 ;
        RECT 22.950 58.685 23.005 59.095 ;
        RECT 23.260 56.040 23.800 56.540 ;
        RECT 26.660 56.040 27.200 56.540 ;
        RECT 25.995 58.685 26.050 59.095 ;
        RECT 23.260 53.440 23.800 53.940 ;
        RECT 26.660 53.440 27.200 53.940 ;
        RECT 26.350 58.685 26.405 59.095 ;
        RECT 22.595 52.185 22.650 52.595 ;
        RECT 22.950 52.185 23.005 52.595 ;
        RECT 20.895 56.085 20.950 56.495 ;
        RECT 21.250 56.085 21.305 56.495 ;
        RECT 22.595 49.585 22.650 49.995 ;
        RECT 23.260 59.940 23.800 60.440 ;
        RECT 26.660 59.940 27.200 60.440 ;
        RECT 22.950 49.585 23.005 49.995 ;
        RECT 23.260 44.340 23.800 44.840 ;
        RECT 26.660 44.340 27.200 44.840 ;
        RECT 22.595 46.985 22.650 47.395 ;
        RECT 22.950 46.985 23.005 47.395 ;
        RECT 25.995 46.985 26.050 47.395 ;
        RECT 26.350 46.985 26.405 47.395 ;
        RECT 21.560 46.940 22.100 47.440 ;
        RECT 24.960 46.940 25.500 47.440 ;
        RECT 20.895 36.585 20.950 36.995 ;
        RECT 21.250 36.585 21.305 36.995 ;
        RECT 24.295 36.585 24.350 36.995 ;
        RECT 24.650 36.585 24.705 36.995 ;
        RECT 23.260 36.540 23.800 37.040 ;
        RECT 26.660 36.540 27.200 37.040 ;
        RECT 22.595 37.885 22.650 38.295 ;
        RECT 22.950 37.885 23.005 38.295 ;
        RECT 25.995 37.885 26.050 38.295 ;
        RECT 26.350 37.885 26.405 38.295 ;
        RECT 21.560 37.840 22.100 38.340 ;
        RECT 24.960 37.840 25.500 38.340 ;
        RECT 20.895 39.185 20.950 39.595 ;
        RECT 21.250 39.185 21.305 39.595 ;
        RECT 24.295 39.185 24.350 39.595 ;
        RECT 24.650 39.185 24.705 39.595 ;
        RECT 23.260 39.140 23.800 39.640 ;
        RECT 26.660 39.140 27.200 39.640 ;
        RECT 22.595 40.485 22.650 40.895 ;
        RECT 22.950 40.485 23.005 40.895 ;
        RECT 25.995 40.485 26.050 40.895 ;
        RECT 26.350 40.485 26.405 40.895 ;
        RECT 21.560 40.440 22.100 40.940 ;
        RECT 24.960 40.440 25.500 40.940 ;
        RECT 20.895 41.785 20.950 42.195 ;
        RECT 21.250 41.785 21.305 42.195 ;
        RECT 24.295 41.785 24.350 42.195 ;
        RECT 24.650 41.785 24.705 42.195 ;
        RECT 23.260 41.740 23.800 42.240 ;
        RECT 26.660 41.740 27.200 42.240 ;
        RECT 22.595 43.085 22.650 43.495 ;
        RECT 22.950 43.085 23.005 43.495 ;
        RECT 25.995 43.085 26.050 43.495 ;
        RECT 26.350 43.085 26.405 43.495 ;
        RECT 21.560 43.040 22.100 43.540 ;
        RECT 24.960 43.040 25.500 43.540 ;
        RECT 20.895 44.385 20.950 44.795 ;
        RECT 21.250 44.385 21.305 44.795 ;
        RECT 24.295 44.385 24.350 44.795 ;
        RECT 24.650 44.385 24.705 44.795 ;
        RECT 16.460 39.140 17.000 39.640 ;
        RECT 19.860 39.140 20.400 39.640 ;
        RECT 16.460 36.540 17.000 37.040 ;
        RECT 19.860 36.540 20.400 37.040 ;
        RECT 15.795 40.485 15.850 40.895 ;
        RECT 16.150 40.485 16.205 40.895 ;
        RECT 19.195 40.485 19.250 40.895 ;
        RECT 19.550 40.485 19.605 40.895 ;
        RECT 14.760 46.940 15.300 47.440 ;
        RECT 18.160 46.940 18.700 47.440 ;
        RECT 15.795 37.885 15.850 38.295 ;
        RECT 16.150 37.885 16.205 38.295 ;
        RECT 14.760 40.440 15.300 40.940 ;
        RECT 18.160 40.440 18.700 40.940 ;
        RECT 19.195 37.885 19.250 38.295 ;
        RECT 19.550 37.885 19.605 38.295 ;
        RECT 14.095 41.785 14.150 42.195 ;
        RECT 14.450 41.785 14.505 42.195 ;
        RECT 17.495 41.785 17.550 42.195 ;
        RECT 17.850 41.785 17.905 42.195 ;
        RECT 19.195 46.985 19.250 47.395 ;
        RECT 19.550 46.985 19.605 47.395 ;
        RECT 14.095 36.585 14.150 36.995 ;
        RECT 14.450 36.585 14.505 36.995 ;
        RECT 16.460 41.740 17.000 42.240 ;
        RECT 19.860 41.740 20.400 42.240 ;
        RECT 14.760 37.840 15.300 38.340 ;
        RECT 18.160 37.840 18.700 38.340 ;
        RECT 15.795 43.085 15.850 43.495 ;
        RECT 16.150 43.085 16.205 43.495 ;
        RECT 19.195 43.085 19.250 43.495 ;
        RECT 19.550 43.085 19.605 43.495 ;
        RECT 17.495 36.585 17.550 36.995 ;
        RECT 17.850 36.585 17.905 36.995 ;
        RECT 14.095 39.185 14.150 39.595 ;
        RECT 14.450 39.185 14.505 39.595 ;
        RECT 14.760 43.040 15.300 43.540 ;
        RECT 18.160 43.040 18.700 43.540 ;
        RECT 17.495 39.185 17.550 39.595 ;
        RECT 17.850 39.185 17.905 39.595 ;
        RECT 14.095 44.385 14.150 44.795 ;
        RECT 14.450 44.385 14.505 44.795 ;
        RECT 17.495 44.385 17.550 44.795 ;
        RECT 17.850 44.385 17.905 44.795 ;
        RECT 16.460 44.340 17.000 44.840 ;
        RECT 19.860 44.340 20.400 44.840 ;
        RECT 15.795 46.985 15.850 47.395 ;
        RECT 16.150 46.985 16.205 47.395 ;
        RECT 19.195 31.385 19.250 31.795 ;
        RECT 19.550 31.385 19.605 31.795 ;
        RECT 14.760 31.340 15.300 31.840 ;
        RECT 18.160 31.340 18.700 31.840 ;
        RECT 14.095 32.685 14.150 33.095 ;
        RECT 14.450 32.685 14.505 33.095 ;
        RECT 17.495 32.685 17.550 33.095 ;
        RECT 17.850 32.685 17.905 33.095 ;
        RECT 16.460 32.640 17.000 33.140 ;
        RECT 19.860 32.640 20.400 33.140 ;
        RECT 15.795 35.285 15.850 35.695 ;
        RECT 16.150 35.285 16.205 35.695 ;
        RECT 19.195 35.285 19.250 35.695 ;
        RECT 19.550 35.285 19.605 35.695 ;
        RECT 14.760 35.240 15.300 35.740 ;
        RECT 18.160 35.240 18.700 35.740 ;
        RECT 14.095 24.885 14.150 25.295 ;
        RECT 14.450 24.885 14.505 25.295 ;
        RECT 17.495 24.885 17.550 25.295 ;
        RECT 17.850 24.885 17.905 25.295 ;
        RECT 16.460 24.840 17.000 25.340 ;
        RECT 19.860 24.840 20.400 25.340 ;
        RECT 15.795 26.185 15.850 26.595 ;
        RECT 16.150 26.185 16.205 26.595 ;
        RECT 19.195 26.185 19.250 26.595 ;
        RECT 19.550 26.185 19.605 26.595 ;
        RECT 14.760 26.140 15.300 26.640 ;
        RECT 18.160 26.140 18.700 26.640 ;
        RECT 14.095 27.485 14.150 27.895 ;
        RECT 14.450 27.485 14.505 27.895 ;
        RECT 17.495 27.485 17.550 27.895 ;
        RECT 17.850 27.485 17.905 27.895 ;
        RECT 16.460 27.440 17.000 27.940 ;
        RECT 19.860 27.440 20.400 27.940 ;
        RECT 15.795 28.785 15.850 29.195 ;
        RECT 16.150 28.785 16.205 29.195 ;
        RECT 19.195 28.785 19.250 29.195 ;
        RECT 19.550 28.785 19.605 29.195 ;
        RECT 14.760 28.740 15.300 29.240 ;
        RECT 18.160 28.740 18.700 29.240 ;
        RECT 14.095 30.085 14.150 30.495 ;
        RECT 14.450 30.085 14.505 30.495 ;
        RECT 17.495 30.085 17.550 30.495 ;
        RECT 17.850 30.085 17.905 30.495 ;
        RECT 16.460 30.040 17.000 30.540 ;
        RECT 19.860 30.040 20.400 30.540 ;
        RECT 15.795 31.385 15.850 31.795 ;
        RECT 16.150 31.385 16.205 31.795 ;
        RECT 22.595 28.785 22.650 29.195 ;
        RECT 22.950 28.785 23.005 29.195 ;
        RECT 23.260 32.640 23.800 33.140 ;
        RECT 26.660 32.640 27.200 33.140 ;
        RECT 25.995 28.785 26.050 29.195 ;
        RECT 26.350 28.785 26.405 29.195 ;
        RECT 21.560 26.140 22.100 26.640 ;
        RECT 24.960 26.140 25.500 26.640 ;
        RECT 22.595 35.285 22.650 35.695 ;
        RECT 22.950 35.285 23.005 35.695 ;
        RECT 25.995 35.285 26.050 35.695 ;
        RECT 26.350 35.285 26.405 35.695 ;
        RECT 21.560 28.740 22.100 29.240 ;
        RECT 24.960 28.740 25.500 29.240 ;
        RECT 21.560 35.240 22.100 35.740 ;
        RECT 24.960 35.240 25.500 35.740 ;
        RECT 24.295 24.885 24.350 25.295 ;
        RECT 24.650 24.885 24.705 25.295 ;
        RECT 20.895 24.885 20.950 25.295 ;
        RECT 21.250 24.885 21.305 25.295 ;
        RECT 20.895 30.085 20.950 30.495 ;
        RECT 21.250 30.085 21.305 30.495 ;
        RECT 24.295 30.085 24.350 30.495 ;
        RECT 24.650 30.085 24.705 30.495 ;
        RECT 20.895 27.485 20.950 27.895 ;
        RECT 21.250 27.485 21.305 27.895 ;
        RECT 23.260 30.040 23.800 30.540 ;
        RECT 26.660 30.040 27.200 30.540 ;
        RECT 24.295 27.485 24.350 27.895 ;
        RECT 24.650 27.485 24.705 27.895 ;
        RECT 22.595 26.185 22.650 26.595 ;
        RECT 22.950 26.185 23.005 26.595 ;
        RECT 22.595 31.385 22.650 31.795 ;
        RECT 22.950 31.385 23.005 31.795 ;
        RECT 25.995 31.385 26.050 31.795 ;
        RECT 26.350 31.385 26.405 31.795 ;
        RECT 23.260 27.440 23.800 27.940 ;
        RECT 26.660 27.440 27.200 27.940 ;
        RECT 21.560 31.340 22.100 31.840 ;
        RECT 24.960 31.340 25.500 31.840 ;
        RECT 25.995 26.185 26.050 26.595 ;
        RECT 26.350 26.185 26.405 26.595 ;
        RECT 23.260 24.840 23.800 25.340 ;
        RECT 26.660 24.840 27.200 25.340 ;
        RECT 20.895 32.685 20.950 33.095 ;
        RECT 21.250 32.685 21.305 33.095 ;
        RECT 24.295 32.685 24.350 33.095 ;
        RECT 24.650 32.685 24.705 33.095 ;
        RECT 7.960 46.940 8.500 47.440 ;
        RECT 11.360 46.940 11.900 47.440 ;
        RECT 12.395 46.985 12.450 47.395 ;
        RECT 12.750 46.985 12.805 47.395 ;
        RECT 7.295 36.585 7.350 36.995 ;
        RECT 7.650 36.585 7.705 36.995 ;
        RECT 10.695 36.585 10.750 36.995 ;
        RECT 11.050 36.585 11.105 36.995 ;
        RECT 9.660 36.540 10.200 37.040 ;
        RECT 13.060 36.540 13.600 37.040 ;
        RECT 8.995 37.885 9.050 38.295 ;
        RECT 9.350 37.885 9.405 38.295 ;
        RECT 12.395 37.885 12.450 38.295 ;
        RECT 12.750 37.885 12.805 38.295 ;
        RECT 9.660 44.340 10.200 44.840 ;
        RECT 13.060 44.340 13.600 44.840 ;
        RECT 7.960 37.840 8.500 38.340 ;
        RECT 11.360 37.840 11.900 38.340 ;
        RECT 7.295 39.185 7.350 39.595 ;
        RECT 7.650 39.185 7.705 39.595 ;
        RECT 10.695 39.185 10.750 39.595 ;
        RECT 11.050 39.185 11.105 39.595 ;
        RECT 9.660 39.140 10.200 39.640 ;
        RECT 13.060 39.140 13.600 39.640 ;
        RECT 8.995 40.485 9.050 40.895 ;
        RECT 9.350 40.485 9.405 40.895 ;
        RECT 12.395 40.485 12.450 40.895 ;
        RECT 12.750 40.485 12.805 40.895 ;
        RECT 7.960 40.440 8.500 40.940 ;
        RECT 11.360 40.440 11.900 40.940 ;
        RECT 7.295 41.785 7.350 42.195 ;
        RECT 7.650 41.785 7.705 42.195 ;
        RECT 10.695 41.785 10.750 42.195 ;
        RECT 11.050 41.785 11.105 42.195 ;
        RECT 9.660 41.740 10.200 42.240 ;
        RECT 13.060 41.740 13.600 42.240 ;
        RECT 8.995 43.085 9.050 43.495 ;
        RECT 9.350 43.085 9.405 43.495 ;
        RECT 12.395 43.085 12.450 43.495 ;
        RECT 12.750 43.085 12.805 43.495 ;
        RECT 7.960 43.040 8.500 43.540 ;
        RECT 11.360 43.040 11.900 43.540 ;
        RECT 8.995 46.985 9.050 47.395 ;
        RECT 9.350 46.985 9.405 47.395 ;
        RECT 7.295 44.385 7.350 44.795 ;
        RECT 7.650 44.385 7.705 44.795 ;
        RECT 10.695 44.385 10.750 44.795 ;
        RECT 11.050 44.385 11.105 44.795 ;
        RECT 1.160 37.840 1.700 38.340 ;
        RECT 4.560 37.840 5.100 38.340 ;
        RECT 1.160 40.440 1.700 40.940 ;
        RECT 4.560 40.440 5.100 40.940 ;
        RECT 2.195 37.885 2.250 38.295 ;
        RECT 2.550 37.885 2.605 38.295 ;
        RECT 2.195 46.985 2.250 47.395 ;
        RECT 2.550 46.985 2.605 47.395 ;
        RECT 0.495 41.785 0.550 42.195 ;
        RECT 0.850 41.785 0.905 42.195 ;
        RECT 3.895 41.785 3.950 42.195 ;
        RECT 4.250 41.785 4.305 42.195 ;
        RECT 0.495 39.185 0.550 39.595 ;
        RECT 0.850 39.185 0.905 39.595 ;
        RECT 3.895 39.185 3.950 39.595 ;
        RECT 4.250 39.185 4.305 39.595 ;
        RECT 2.860 41.740 3.400 42.240 ;
        RECT 6.260 41.740 6.800 42.240 ;
        RECT 5.595 37.885 5.650 38.295 ;
        RECT 5.950 37.885 6.005 38.295 ;
        RECT 2.195 43.085 2.250 43.495 ;
        RECT 2.550 43.085 2.605 43.495 ;
        RECT 5.595 43.085 5.650 43.495 ;
        RECT 5.950 43.085 6.005 43.495 ;
        RECT 3.895 36.585 3.950 36.995 ;
        RECT 4.250 36.585 4.305 36.995 ;
        RECT 2.860 39.140 3.400 39.640 ;
        RECT 6.260 39.140 6.800 39.640 ;
        RECT 5.595 46.985 5.650 47.395 ;
        RECT 5.950 46.985 6.005 47.395 ;
        RECT 1.160 43.040 1.700 43.540 ;
        RECT 4.560 43.040 5.100 43.540 ;
        RECT 2.860 36.540 3.400 37.040 ;
        RECT 6.260 36.540 6.800 37.040 ;
        RECT 2.195 40.485 2.250 40.895 ;
        RECT 2.550 40.485 2.605 40.895 ;
        RECT 0.495 44.385 0.550 44.795 ;
        RECT 0.850 44.385 0.905 44.795 ;
        RECT 3.895 44.385 3.950 44.795 ;
        RECT 4.250 44.385 4.305 44.795 ;
        RECT 5.595 40.485 5.650 40.895 ;
        RECT 5.950 40.485 6.005 40.895 ;
        RECT 0.495 36.585 0.550 36.995 ;
        RECT 0.850 36.585 0.905 36.995 ;
        RECT 1.160 46.940 1.700 47.440 ;
        RECT 4.560 46.940 5.100 47.440 ;
        RECT 2.860 44.340 3.400 44.840 ;
        RECT 6.260 44.340 6.800 44.840 ;
        RECT 0.495 27.485 0.550 27.895 ;
        RECT 0.850 27.485 0.905 27.895 ;
        RECT 3.895 27.485 3.950 27.895 ;
        RECT 4.250 27.485 4.305 27.895 ;
        RECT 1.160 31.340 1.700 31.840 ;
        RECT 4.560 31.340 5.100 31.840 ;
        RECT 2.860 30.040 3.400 30.540 ;
        RECT 6.260 30.040 6.800 30.540 ;
        RECT 2.195 26.185 2.250 26.595 ;
        RECT 2.550 26.185 2.605 26.595 ;
        RECT 5.595 26.185 5.650 26.595 ;
        RECT 5.950 26.185 6.005 26.595 ;
        RECT 0.495 30.085 0.550 30.495 ;
        RECT 0.850 30.085 0.905 30.495 ;
        RECT 3.895 30.085 3.950 30.495 ;
        RECT 4.250 30.085 4.305 30.495 ;
        RECT 1.160 28.740 1.700 29.240 ;
        RECT 4.560 28.740 5.100 29.240 ;
        RECT 5.595 35.285 5.650 35.695 ;
        RECT 5.950 35.285 6.005 35.695 ;
        RECT 0.495 32.685 0.550 33.095 ;
        RECT 0.850 32.685 0.905 33.095 ;
        RECT 3.895 32.685 3.950 33.095 ;
        RECT 4.250 32.685 4.305 33.095 ;
        RECT 2.195 31.385 2.250 31.795 ;
        RECT 2.550 31.385 2.605 31.795 ;
        RECT 5.595 31.385 5.650 31.795 ;
        RECT 5.950 31.385 6.005 31.795 ;
        RECT 0.495 24.885 0.550 25.295 ;
        RECT 0.850 24.885 0.905 25.295 ;
        RECT 2.195 35.285 2.250 35.695 ;
        RECT 2.550 35.285 2.605 35.695 ;
        RECT 2.195 28.785 2.250 29.195 ;
        RECT 2.550 28.785 2.605 29.195 ;
        RECT 5.595 28.785 5.650 29.195 ;
        RECT 5.950 28.785 6.005 29.195 ;
        RECT 1.160 35.240 1.700 35.740 ;
        RECT 4.560 35.240 5.100 35.740 ;
        RECT 3.895 24.885 3.950 25.295 ;
        RECT 4.250 24.885 4.305 25.295 ;
        RECT 2.860 24.840 3.400 25.340 ;
        RECT 6.260 24.840 6.800 25.340 ;
        RECT 2.860 27.440 3.400 27.940 ;
        RECT 6.260 27.440 6.800 27.940 ;
        RECT 2.860 32.640 3.400 33.140 ;
        RECT 6.260 32.640 6.800 33.140 ;
        RECT 1.160 26.140 1.700 26.640 ;
        RECT 4.560 26.140 5.100 26.640 ;
        RECT 9.660 24.840 10.200 25.340 ;
        RECT 13.060 24.840 13.600 25.340 ;
        RECT 7.960 31.340 8.500 31.840 ;
        RECT 11.360 31.340 11.900 31.840 ;
        RECT 10.695 27.485 10.750 27.895 ;
        RECT 11.050 27.485 11.105 27.895 ;
        RECT 10.695 30.085 10.750 30.495 ;
        RECT 11.050 30.085 11.105 30.495 ;
        RECT 7.960 28.740 8.500 29.240 ;
        RECT 11.360 28.740 11.900 29.240 ;
        RECT 10.695 24.885 10.750 25.295 ;
        RECT 11.050 24.885 11.105 25.295 ;
        RECT 12.395 26.185 12.450 26.595 ;
        RECT 12.750 26.185 12.805 26.595 ;
        RECT 9.660 32.640 10.200 33.140 ;
        RECT 13.060 32.640 13.600 33.140 ;
        RECT 8.995 31.385 9.050 31.795 ;
        RECT 9.350 31.385 9.405 31.795 ;
        RECT 9.660 27.440 10.200 27.940 ;
        RECT 13.060 27.440 13.600 27.940 ;
        RECT 7.295 32.685 7.350 33.095 ;
        RECT 7.650 32.685 7.705 33.095 ;
        RECT 8.995 28.785 9.050 29.195 ;
        RECT 9.350 28.785 9.405 29.195 ;
        RECT 12.395 31.385 12.450 31.795 ;
        RECT 12.750 31.385 12.805 31.795 ;
        RECT 10.695 32.685 10.750 33.095 ;
        RECT 11.050 32.685 11.105 33.095 ;
        RECT 8.995 35.285 9.050 35.695 ;
        RECT 9.350 35.285 9.405 35.695 ;
        RECT 7.295 24.885 7.350 25.295 ;
        RECT 7.650 24.885 7.705 25.295 ;
        RECT 7.960 35.240 8.500 35.740 ;
        RECT 11.360 35.240 11.900 35.740 ;
        RECT 8.995 26.185 9.050 26.595 ;
        RECT 9.350 26.185 9.405 26.595 ;
        RECT 12.395 28.785 12.450 29.195 ;
        RECT 12.750 28.785 12.805 29.195 ;
        RECT 7.295 30.085 7.350 30.495 ;
        RECT 7.650 30.085 7.705 30.495 ;
        RECT 9.660 30.040 10.200 30.540 ;
        RECT 13.060 30.040 13.600 30.540 ;
        RECT 7.295 27.485 7.350 27.895 ;
        RECT 7.650 27.485 7.705 27.895 ;
        RECT 7.960 26.140 8.500 26.640 ;
        RECT 11.360 26.140 11.900 26.640 ;
        RECT 12.395 35.285 12.450 35.695 ;
        RECT 12.750 35.285 12.805 35.695 ;
        RECT 2.195 11.885 2.250 12.295 ;
        RECT 2.550 11.885 2.605 12.295 ;
        RECT 5.595 11.885 5.650 12.295 ;
        RECT 5.950 11.885 6.005 12.295 ;
        RECT 8.995 11.885 9.050 12.295 ;
        RECT 9.350 11.885 9.405 12.295 ;
        RECT 12.395 11.885 12.450 12.295 ;
        RECT 12.750 11.885 12.805 12.295 ;
        RECT 1.160 11.840 1.700 12.340 ;
        RECT 4.560 11.840 5.100 12.340 ;
        RECT 7.960 11.840 8.500 12.340 ;
        RECT 11.360 11.840 11.900 12.340 ;
        RECT 12.395 19.685 12.450 20.095 ;
        RECT 12.750 19.685 12.805 20.095 ;
        RECT 7.960 19.640 8.500 20.140 ;
        RECT 11.360 19.640 11.900 20.140 ;
        RECT 7.295 20.985 7.350 21.395 ;
        RECT 7.650 20.985 7.705 21.395 ;
        RECT 10.695 20.985 10.750 21.395 ;
        RECT 11.050 20.985 11.105 21.395 ;
        RECT 9.660 20.940 10.200 21.440 ;
        RECT 13.060 20.940 13.600 21.440 ;
        RECT 8.995 23.585 9.050 23.995 ;
        RECT 9.350 23.585 9.405 23.995 ;
        RECT 12.395 23.585 12.450 23.995 ;
        RECT 12.750 23.585 12.805 23.995 ;
        RECT 7.960 23.540 8.500 24.040 ;
        RECT 11.360 23.540 11.900 24.040 ;
        RECT 12.395 17.085 12.450 17.495 ;
        RECT 12.750 17.085 12.805 17.495 ;
        RECT 7.960 17.040 8.500 17.540 ;
        RECT 11.360 17.040 11.900 17.540 ;
        RECT 7.295 18.385 7.350 18.795 ;
        RECT 7.650 18.385 7.705 18.795 ;
        RECT 10.695 18.385 10.750 18.795 ;
        RECT 11.050 18.385 11.105 18.795 ;
        RECT 9.660 18.340 10.200 18.840 ;
        RECT 13.060 18.340 13.600 18.840 ;
        RECT 8.995 19.685 9.050 20.095 ;
        RECT 9.350 19.685 9.405 20.095 ;
        RECT 7.295 13.185 7.350 13.595 ;
        RECT 7.650 13.185 7.705 13.595 ;
        RECT 10.695 13.185 10.750 13.595 ;
        RECT 11.050 13.185 11.105 13.595 ;
        RECT 9.660 13.140 10.200 13.640 ;
        RECT 13.060 13.140 13.600 13.640 ;
        RECT 8.995 14.485 9.050 14.895 ;
        RECT 9.350 14.485 9.405 14.895 ;
        RECT 12.395 14.485 12.450 14.895 ;
        RECT 12.750 14.485 12.805 14.895 ;
        RECT 7.960 14.440 8.500 14.940 ;
        RECT 11.360 14.440 11.900 14.940 ;
        RECT 7.295 15.785 7.350 16.195 ;
        RECT 7.650 15.785 7.705 16.195 ;
        RECT 10.695 15.785 10.750 16.195 ;
        RECT 11.050 15.785 11.105 16.195 ;
        RECT 9.660 15.740 10.200 16.240 ;
        RECT 13.060 15.740 13.600 16.240 ;
        RECT 8.995 17.085 9.050 17.495 ;
        RECT 9.350 17.085 9.405 17.495 ;
        RECT 3.895 18.385 3.950 18.795 ;
        RECT 4.250 18.385 4.305 18.795 ;
        RECT 2.195 19.685 2.250 20.095 ;
        RECT 2.550 19.685 2.605 20.095 ;
        RECT 2.860 20.940 3.400 21.440 ;
        RECT 6.260 20.940 6.800 21.440 ;
        RECT 0.495 13.185 0.550 13.595 ;
        RECT 0.850 13.185 0.905 13.595 ;
        RECT 3.895 13.185 3.950 13.595 ;
        RECT 4.250 13.185 4.305 13.595 ;
        RECT 5.595 19.685 5.650 20.095 ;
        RECT 5.950 19.685 6.005 20.095 ;
        RECT 2.195 23.585 2.250 23.995 ;
        RECT 2.550 23.585 2.605 23.995 ;
        RECT 2.860 13.140 3.400 13.640 ;
        RECT 6.260 13.140 6.800 13.640 ;
        RECT 5.595 23.585 5.650 23.995 ;
        RECT 5.950 23.585 6.005 23.995 ;
        RECT 2.195 14.485 2.250 14.895 ;
        RECT 2.550 14.485 2.605 14.895 ;
        RECT 5.595 14.485 5.650 14.895 ;
        RECT 5.950 14.485 6.005 14.895 ;
        RECT 1.160 17.040 1.700 17.540 ;
        RECT 4.560 17.040 5.100 17.540 ;
        RECT 0.495 18.385 0.550 18.795 ;
        RECT 0.850 18.385 0.905 18.795 ;
        RECT 1.160 14.440 1.700 14.940 ;
        RECT 4.560 14.440 5.100 14.940 ;
        RECT 1.160 23.540 1.700 24.040 ;
        RECT 4.560 23.540 5.100 24.040 ;
        RECT 0.495 15.785 0.550 16.195 ;
        RECT 0.850 15.785 0.905 16.195 ;
        RECT 3.895 15.785 3.950 16.195 ;
        RECT 4.250 15.785 4.305 16.195 ;
        RECT 1.160 19.640 1.700 20.140 ;
        RECT 4.560 19.640 5.100 20.140 ;
        RECT 2.860 18.340 3.400 18.840 ;
        RECT 6.260 18.340 6.800 18.840 ;
        RECT 2.860 15.740 3.400 16.240 ;
        RECT 6.260 15.740 6.800 16.240 ;
        RECT 0.495 20.985 0.550 21.395 ;
        RECT 0.850 20.985 0.905 21.395 ;
        RECT 2.195 17.085 2.250 17.495 ;
        RECT 2.550 17.085 2.605 17.495 ;
        RECT 5.595 17.085 5.650 17.495 ;
        RECT 5.950 17.085 6.005 17.495 ;
        RECT 3.895 20.985 3.950 21.395 ;
        RECT 4.250 20.985 4.305 21.395 ;
        RECT 0.495 1.485 0.550 1.895 ;
        RECT 0.850 1.485 0.905 1.895 ;
        RECT 3.895 1.485 3.950 1.895 ;
        RECT 4.250 1.485 4.305 1.895 ;
        RECT 2.860 1.440 3.400 1.940 ;
        RECT 6.260 1.440 6.800 1.940 ;
        RECT 2.195 2.785 2.250 3.195 ;
        RECT 2.550 2.785 2.605 3.195 ;
        RECT 5.595 2.785 5.650 3.195 ;
        RECT 5.950 2.785 6.005 3.195 ;
        RECT 1.160 2.740 1.700 3.240 ;
        RECT 4.560 2.740 5.100 3.240 ;
        RECT 0.495 4.085 0.550 4.495 ;
        RECT 0.850 4.085 0.905 4.495 ;
        RECT 3.895 4.085 3.950 4.495 ;
        RECT 4.250 4.085 4.305 4.495 ;
        RECT 2.860 4.040 3.400 4.540 ;
        RECT 6.260 4.040 6.800 4.540 ;
        RECT 2.195 5.385 2.250 5.795 ;
        RECT 2.550 5.385 2.605 5.795 ;
        RECT 5.595 5.385 5.650 5.795 ;
        RECT 5.950 5.385 6.005 5.795 ;
        RECT 1.160 5.340 1.700 5.840 ;
        RECT 4.560 5.340 5.100 5.840 ;
        RECT 0.495 6.685 0.550 7.095 ;
        RECT 0.850 6.685 0.905 7.095 ;
        RECT 3.895 6.685 3.950 7.095 ;
        RECT 4.250 6.685 4.305 7.095 ;
        RECT 2.860 6.640 3.400 7.140 ;
        RECT 6.260 6.640 6.800 7.140 ;
        RECT 2.195 7.985 2.250 8.395 ;
        RECT 2.550 7.985 2.605 8.395 ;
        RECT 5.595 7.985 5.650 8.395 ;
        RECT 5.950 7.985 6.005 8.395 ;
        RECT 1.160 7.940 1.700 8.440 ;
        RECT 4.560 7.940 5.100 8.440 ;
        RECT 0.495 9.285 0.550 9.695 ;
        RECT 0.850 9.285 0.905 9.695 ;
        RECT 3.895 9.285 3.950 9.695 ;
        RECT 4.250 9.285 4.305 9.695 ;
        RECT 2.860 9.240 3.400 9.740 ;
        RECT 6.260 9.240 6.800 9.740 ;
        RECT 2.195 0.185 2.250 0.595 ;
        RECT 2.550 0.185 2.605 0.595 ;
        RECT 5.595 0.185 5.650 0.595 ;
        RECT 5.950 0.185 6.005 0.595 ;
        RECT 1.160 0.140 1.700 0.640 ;
        RECT 4.560 0.140 5.100 0.640 ;
        RECT 12.395 5.385 12.450 5.795 ;
        RECT 12.750 5.385 12.805 5.795 ;
        RECT 8.995 2.785 9.050 3.195 ;
        RECT 9.350 2.785 9.405 3.195 ;
        RECT 7.960 5.340 8.500 5.840 ;
        RECT 11.360 5.340 11.900 5.840 ;
        RECT 12.395 2.785 12.450 3.195 ;
        RECT 12.750 2.785 12.805 3.195 ;
        RECT 7.295 1.485 7.350 1.895 ;
        RECT 7.650 1.485 7.705 1.895 ;
        RECT 7.295 6.685 7.350 7.095 ;
        RECT 7.650 6.685 7.705 7.095 ;
        RECT 10.695 6.685 10.750 7.095 ;
        RECT 11.050 6.685 11.105 7.095 ;
        RECT 7.960 2.740 8.500 3.240 ;
        RECT 11.360 2.740 11.900 3.240 ;
        RECT 9.660 6.640 10.200 7.140 ;
        RECT 13.060 6.640 13.600 7.140 ;
        RECT 10.695 1.485 10.750 1.895 ;
        RECT 11.050 1.485 11.105 1.895 ;
        RECT 7.960 0.140 8.500 0.640 ;
        RECT 11.360 0.140 11.900 0.640 ;
        RECT 8.995 7.985 9.050 8.395 ;
        RECT 9.350 7.985 9.405 8.395 ;
        RECT 12.395 7.985 12.450 8.395 ;
        RECT 12.750 7.985 12.805 8.395 ;
        RECT 7.295 4.085 7.350 4.495 ;
        RECT 7.650 4.085 7.705 4.495 ;
        RECT 7.960 7.940 8.500 8.440 ;
        RECT 11.360 7.940 11.900 8.440 ;
        RECT 10.695 4.085 10.750 4.495 ;
        RECT 11.050 4.085 11.105 4.495 ;
        RECT 9.660 1.440 10.200 1.940 ;
        RECT 13.060 1.440 13.600 1.940 ;
        RECT 7.295 9.285 7.350 9.695 ;
        RECT 7.650 9.285 7.705 9.695 ;
        RECT 10.695 9.285 10.750 9.695 ;
        RECT 11.050 9.285 11.105 9.695 ;
        RECT 9.660 4.040 10.200 4.540 ;
        RECT 13.060 4.040 13.600 4.540 ;
        RECT 9.660 9.240 10.200 9.740 ;
        RECT 13.060 9.240 13.600 9.740 ;
        RECT 12.395 0.185 12.450 0.595 ;
        RECT 12.750 0.185 12.805 0.595 ;
        RECT 8.995 0.185 9.050 0.595 ;
        RECT 9.350 0.185 9.405 0.595 ;
        RECT 8.995 5.385 9.050 5.795 ;
        RECT 9.350 5.385 9.405 5.795 ;
        RECT 15.795 11.885 15.850 12.295 ;
        RECT 16.150 11.885 16.205 12.295 ;
        RECT 19.195 11.885 19.250 12.295 ;
        RECT 19.550 11.885 19.605 12.295 ;
        RECT 22.595 11.885 22.650 12.295 ;
        RECT 22.950 11.885 23.005 12.295 ;
        RECT 25.995 11.885 26.050 12.295 ;
        RECT 26.350 11.885 26.405 12.295 ;
        RECT 14.760 11.840 15.300 12.340 ;
        RECT 18.160 11.840 18.700 12.340 ;
        RECT 21.560 11.840 22.100 12.340 ;
        RECT 24.960 11.840 25.500 12.340 ;
        RECT 21.560 19.640 22.100 20.140 ;
        RECT 24.960 19.640 25.500 20.140 ;
        RECT 20.895 20.985 20.950 21.395 ;
        RECT 21.250 20.985 21.305 21.395 ;
        RECT 21.560 23.540 22.100 24.040 ;
        RECT 24.960 23.540 25.500 24.040 ;
        RECT 24.295 20.985 24.350 21.395 ;
        RECT 24.650 20.985 24.705 21.395 ;
        RECT 23.260 20.940 23.800 21.440 ;
        RECT 26.660 20.940 27.200 21.440 ;
        RECT 22.595 23.585 22.650 23.995 ;
        RECT 22.950 23.585 23.005 23.995 ;
        RECT 25.995 23.585 26.050 23.995 ;
        RECT 26.350 23.585 26.405 23.995 ;
        RECT 20.895 13.185 20.950 13.595 ;
        RECT 21.250 13.185 21.305 13.595 ;
        RECT 24.295 13.185 24.350 13.595 ;
        RECT 24.650 13.185 24.705 13.595 ;
        RECT 23.260 13.140 23.800 13.640 ;
        RECT 26.660 13.140 27.200 13.640 ;
        RECT 22.595 14.485 22.650 14.895 ;
        RECT 22.950 14.485 23.005 14.895 ;
        RECT 25.995 14.485 26.050 14.895 ;
        RECT 26.350 14.485 26.405 14.895 ;
        RECT 21.560 14.440 22.100 14.940 ;
        RECT 24.960 14.440 25.500 14.940 ;
        RECT 20.895 15.785 20.950 16.195 ;
        RECT 21.250 15.785 21.305 16.195 ;
        RECT 24.295 15.785 24.350 16.195 ;
        RECT 24.650 15.785 24.705 16.195 ;
        RECT 23.260 15.740 23.800 16.240 ;
        RECT 26.660 15.740 27.200 16.240 ;
        RECT 22.595 17.085 22.650 17.495 ;
        RECT 22.950 17.085 23.005 17.495 ;
        RECT 25.995 17.085 26.050 17.495 ;
        RECT 26.350 17.085 26.405 17.495 ;
        RECT 21.560 17.040 22.100 17.540 ;
        RECT 24.960 17.040 25.500 17.540 ;
        RECT 20.895 18.385 20.950 18.795 ;
        RECT 21.250 18.385 21.305 18.795 ;
        RECT 24.295 18.385 24.350 18.795 ;
        RECT 24.650 18.385 24.705 18.795 ;
        RECT 23.260 18.340 23.800 18.840 ;
        RECT 26.660 18.340 27.200 18.840 ;
        RECT 22.595 19.685 22.650 20.095 ;
        RECT 22.950 19.685 23.005 20.095 ;
        RECT 25.995 19.685 26.050 20.095 ;
        RECT 26.350 19.685 26.405 20.095 ;
        RECT 14.760 14.440 15.300 14.940 ;
        RECT 18.160 14.440 18.700 14.940 ;
        RECT 14.095 20.985 14.150 21.395 ;
        RECT 14.450 20.985 14.505 21.395 ;
        RECT 14.095 15.785 14.150 16.195 ;
        RECT 14.450 15.785 14.505 16.195 ;
        RECT 17.495 15.785 17.550 16.195 ;
        RECT 17.850 15.785 17.905 16.195 ;
        RECT 16.460 20.940 17.000 21.440 ;
        RECT 19.860 20.940 20.400 21.440 ;
        RECT 14.095 13.185 14.150 13.595 ;
        RECT 14.450 13.185 14.505 13.595 ;
        RECT 16.460 15.740 17.000 16.240 ;
        RECT 19.860 15.740 20.400 16.240 ;
        RECT 17.495 13.185 17.550 13.595 ;
        RECT 17.850 13.185 17.905 13.595 ;
        RECT 15.795 17.085 15.850 17.495 ;
        RECT 16.150 17.085 16.205 17.495 ;
        RECT 19.195 17.085 19.250 17.495 ;
        RECT 19.550 17.085 19.605 17.495 ;
        RECT 17.495 20.985 17.550 21.395 ;
        RECT 17.850 20.985 17.905 21.395 ;
        RECT 14.760 23.540 15.300 24.040 ;
        RECT 18.160 23.540 18.700 24.040 ;
        RECT 14.760 17.040 15.300 17.540 ;
        RECT 18.160 17.040 18.700 17.540 ;
        RECT 16.460 13.140 17.000 13.640 ;
        RECT 19.860 13.140 20.400 13.640 ;
        RECT 14.095 18.385 14.150 18.795 ;
        RECT 14.450 18.385 14.505 18.795 ;
        RECT 17.495 18.385 17.550 18.795 ;
        RECT 17.850 18.385 17.905 18.795 ;
        RECT 15.795 23.585 15.850 23.995 ;
        RECT 16.150 23.585 16.205 23.995 ;
        RECT 15.795 14.485 15.850 14.895 ;
        RECT 16.150 14.485 16.205 14.895 ;
        RECT 16.460 18.340 17.000 18.840 ;
        RECT 19.860 18.340 20.400 18.840 ;
        RECT 19.195 14.485 19.250 14.895 ;
        RECT 19.550 14.485 19.605 14.895 ;
        RECT 15.795 19.685 15.850 20.095 ;
        RECT 16.150 19.685 16.205 20.095 ;
        RECT 19.195 19.685 19.250 20.095 ;
        RECT 19.550 19.685 19.605 20.095 ;
        RECT 19.195 23.585 19.250 23.995 ;
        RECT 19.550 23.585 19.605 23.995 ;
        RECT 14.760 19.640 15.300 20.140 ;
        RECT 18.160 19.640 18.700 20.140 ;
        RECT 14.760 0.140 15.300 0.640 ;
        RECT 18.160 0.140 18.700 0.640 ;
        RECT 17.495 9.285 17.550 9.695 ;
        RECT 17.850 9.285 17.905 9.695 ;
        RECT 15.795 2.785 15.850 3.195 ;
        RECT 16.150 2.785 16.205 3.195 ;
        RECT 19.195 2.785 19.250 3.195 ;
        RECT 19.550 2.785 19.605 3.195 ;
        RECT 16.460 4.040 17.000 4.540 ;
        RECT 19.860 4.040 20.400 4.540 ;
        RECT 15.795 7.985 15.850 8.395 ;
        RECT 16.150 7.985 16.205 8.395 ;
        RECT 19.195 7.985 19.250 8.395 ;
        RECT 19.550 7.985 19.605 8.395 ;
        RECT 14.095 6.685 14.150 7.095 ;
        RECT 14.450 6.685 14.505 7.095 ;
        RECT 17.495 6.685 17.550 7.095 ;
        RECT 17.850 6.685 17.905 7.095 ;
        RECT 14.095 4.085 14.150 4.495 ;
        RECT 14.450 4.085 14.505 4.495 ;
        RECT 17.495 4.085 17.550 4.495 ;
        RECT 17.850 4.085 17.905 4.495 ;
        RECT 15.795 0.185 15.850 0.595 ;
        RECT 16.150 0.185 16.205 0.595 ;
        RECT 19.195 0.185 19.250 0.595 ;
        RECT 19.550 0.185 19.605 0.595 ;
        RECT 14.760 2.740 15.300 3.240 ;
        RECT 18.160 2.740 18.700 3.240 ;
        RECT 15.795 5.385 15.850 5.795 ;
        RECT 16.150 5.385 16.205 5.795 ;
        RECT 14.760 7.940 15.300 8.440 ;
        RECT 18.160 7.940 18.700 8.440 ;
        RECT 14.760 5.340 15.300 5.840 ;
        RECT 18.160 5.340 18.700 5.840 ;
        RECT 19.195 5.385 19.250 5.795 ;
        RECT 19.550 5.385 19.605 5.795 ;
        RECT 16.460 1.440 17.000 1.940 ;
        RECT 19.860 1.440 20.400 1.940 ;
        RECT 16.460 9.240 17.000 9.740 ;
        RECT 19.860 9.240 20.400 9.740 ;
        RECT 16.460 6.640 17.000 7.140 ;
        RECT 19.860 6.640 20.400 7.140 ;
        RECT 14.095 1.485 14.150 1.895 ;
        RECT 14.450 1.485 14.505 1.895 ;
        RECT 17.495 1.485 17.550 1.895 ;
        RECT 17.850 1.485 17.905 1.895 ;
        RECT 14.095 9.285 14.150 9.695 ;
        RECT 14.450 9.285 14.505 9.695 ;
        RECT 21.560 2.740 22.100 3.240 ;
        RECT 24.960 2.740 25.500 3.240 ;
        RECT 25.995 0.185 26.050 0.595 ;
        RECT 26.350 0.185 26.405 0.595 ;
        RECT 20.895 9.285 20.950 9.695 ;
        RECT 21.250 9.285 21.305 9.695 ;
        RECT 22.595 7.985 22.650 8.395 ;
        RECT 22.950 7.985 23.005 8.395 ;
        RECT 25.995 7.985 26.050 8.395 ;
        RECT 26.350 7.985 26.405 8.395 ;
        RECT 23.260 9.240 23.800 9.740 ;
        RECT 26.660 9.240 27.200 9.740 ;
        RECT 23.260 4.040 23.800 4.540 ;
        RECT 26.660 4.040 27.200 4.540 ;
        RECT 24.295 9.285 24.350 9.695 ;
        RECT 24.650 9.285 24.705 9.695 ;
        RECT 23.260 6.640 23.800 7.140 ;
        RECT 26.660 6.640 27.200 7.140 ;
        RECT 22.595 5.385 22.650 5.795 ;
        RECT 22.950 5.385 23.005 5.795 ;
        RECT 21.560 5.340 22.100 5.840 ;
        RECT 24.960 5.340 25.500 5.840 ;
        RECT 20.895 1.485 20.950 1.895 ;
        RECT 21.250 1.485 21.305 1.895 ;
        RECT 21.560 7.940 22.100 8.440 ;
        RECT 24.960 7.940 25.500 8.440 ;
        RECT 24.295 1.485 24.350 1.895 ;
        RECT 24.650 1.485 24.705 1.895 ;
        RECT 25.995 5.385 26.050 5.795 ;
        RECT 26.350 5.385 26.405 5.795 ;
        RECT 20.895 4.085 20.950 4.495 ;
        RECT 21.250 4.085 21.305 4.495 ;
        RECT 24.295 4.085 24.350 4.495 ;
        RECT 24.650 4.085 24.705 4.495 ;
        RECT 21.560 0.140 22.100 0.640 ;
        RECT 24.960 0.140 25.500 0.640 ;
        RECT 23.260 1.440 23.800 1.940 ;
        RECT 26.660 1.440 27.200 1.940 ;
        RECT 22.595 0.185 22.650 0.595 ;
        RECT 22.950 0.185 23.005 0.595 ;
        RECT 22.595 2.785 22.650 3.195 ;
        RECT 22.950 2.785 23.005 3.195 ;
        RECT 20.895 6.685 20.950 7.095 ;
        RECT 21.250 6.685 21.305 7.095 ;
        RECT 24.295 6.685 24.350 7.095 ;
        RECT 24.650 6.685 24.705 7.095 ;
        RECT 25.995 2.785 26.050 3.195 ;
        RECT 26.350 2.785 26.405 3.195 ;
        RECT 49.795 46.985 49.850 47.395 ;
        RECT 50.150 46.985 50.205 47.395 ;
        RECT 53.195 46.985 53.250 47.395 ;
        RECT 53.550 46.985 53.605 47.395 ;
        RECT 48.760 46.940 49.300 47.440 ;
        RECT 52.160 46.940 52.700 47.440 ;
        RECT 48.095 36.585 48.150 36.995 ;
        RECT 48.450 36.585 48.505 36.995 ;
        RECT 51.495 36.585 51.550 36.995 ;
        RECT 51.850 36.585 51.905 36.995 ;
        RECT 50.460 36.540 51.000 37.040 ;
        RECT 53.860 36.540 54.400 37.040 ;
        RECT 49.795 37.885 49.850 38.295 ;
        RECT 50.150 37.885 50.205 38.295 ;
        RECT 53.195 37.885 53.250 38.295 ;
        RECT 53.550 37.885 53.605 38.295 ;
        RECT 48.760 37.840 49.300 38.340 ;
        RECT 52.160 37.840 52.700 38.340 ;
        RECT 48.095 39.185 48.150 39.595 ;
        RECT 48.450 39.185 48.505 39.595 ;
        RECT 51.495 39.185 51.550 39.595 ;
        RECT 51.850 39.185 51.905 39.595 ;
        RECT 50.460 39.140 51.000 39.640 ;
        RECT 53.860 39.140 54.400 39.640 ;
        RECT 49.795 40.485 49.850 40.895 ;
        RECT 50.150 40.485 50.205 40.895 ;
        RECT 53.195 40.485 53.250 40.895 ;
        RECT 53.550 40.485 53.605 40.895 ;
        RECT 48.760 40.440 49.300 40.940 ;
        RECT 52.160 40.440 52.700 40.940 ;
        RECT 48.095 41.785 48.150 42.195 ;
        RECT 48.450 41.785 48.505 42.195 ;
        RECT 51.495 41.785 51.550 42.195 ;
        RECT 51.850 41.785 51.905 42.195 ;
        RECT 50.460 41.740 51.000 42.240 ;
        RECT 53.860 41.740 54.400 42.240 ;
        RECT 49.795 43.085 49.850 43.495 ;
        RECT 50.150 43.085 50.205 43.495 ;
        RECT 53.195 43.085 53.250 43.495 ;
        RECT 53.550 43.085 53.605 43.495 ;
        RECT 48.760 43.040 49.300 43.540 ;
        RECT 52.160 43.040 52.700 43.540 ;
        RECT 48.095 44.385 48.150 44.795 ;
        RECT 48.450 44.385 48.505 44.795 ;
        RECT 51.495 44.385 51.550 44.795 ;
        RECT 51.850 44.385 51.905 44.795 ;
        RECT 50.460 44.340 51.000 44.840 ;
        RECT 53.860 44.340 54.400 44.840 ;
        RECT 42.995 40.485 43.050 40.895 ;
        RECT 43.350 40.485 43.405 40.895 ;
        RECT 46.395 40.485 46.450 40.895 ;
        RECT 46.750 40.485 46.805 40.895 ;
        RECT 42.995 37.885 43.050 38.295 ;
        RECT 43.350 37.885 43.405 38.295 ;
        RECT 46.395 37.885 46.450 38.295 ;
        RECT 46.750 37.885 46.805 38.295 ;
        RECT 41.960 40.440 42.500 40.940 ;
        RECT 45.360 40.440 45.900 40.940 ;
        RECT 41.295 36.585 41.350 36.995 ;
        RECT 41.650 36.585 41.705 36.995 ;
        RECT 41.295 41.785 41.350 42.195 ;
        RECT 41.650 41.785 41.705 42.195 ;
        RECT 44.695 41.785 44.750 42.195 ;
        RECT 45.050 41.785 45.105 42.195 ;
        RECT 44.695 36.585 44.750 36.995 ;
        RECT 45.050 36.585 45.105 36.995 ;
        RECT 41.960 37.840 42.500 38.340 ;
        RECT 45.360 37.840 45.900 38.340 ;
        RECT 43.660 41.740 44.200 42.240 ;
        RECT 47.060 41.740 47.600 42.240 ;
        RECT 46.395 46.985 46.450 47.395 ;
        RECT 46.750 46.985 46.805 47.395 ;
        RECT 42.995 43.085 43.050 43.495 ;
        RECT 43.350 43.085 43.405 43.495 ;
        RECT 46.395 43.085 46.450 43.495 ;
        RECT 46.750 43.085 46.805 43.495 ;
        RECT 41.295 39.185 41.350 39.595 ;
        RECT 41.650 39.185 41.705 39.595 ;
        RECT 44.695 39.185 44.750 39.595 ;
        RECT 45.050 39.185 45.105 39.595 ;
        RECT 41.960 43.040 42.500 43.540 ;
        RECT 45.360 43.040 45.900 43.540 ;
        RECT 41.960 46.940 42.500 47.440 ;
        RECT 45.360 46.940 45.900 47.440 ;
        RECT 41.295 44.385 41.350 44.795 ;
        RECT 41.650 44.385 41.705 44.795 ;
        RECT 44.695 44.385 44.750 44.795 ;
        RECT 45.050 44.385 45.105 44.795 ;
        RECT 43.660 36.540 44.200 37.040 ;
        RECT 47.060 36.540 47.600 37.040 ;
        RECT 43.660 39.140 44.200 39.640 ;
        RECT 47.060 39.140 47.600 39.640 ;
        RECT 43.660 44.340 44.200 44.840 ;
        RECT 47.060 44.340 47.600 44.840 ;
        RECT 42.995 46.985 43.050 47.395 ;
        RECT 43.350 46.985 43.405 47.395 ;
        RECT 41.295 32.685 41.350 33.095 ;
        RECT 41.650 32.685 41.705 33.095 ;
        RECT 44.695 32.685 44.750 33.095 ;
        RECT 45.050 32.685 45.105 33.095 ;
        RECT 43.660 32.640 44.200 33.140 ;
        RECT 47.060 32.640 47.600 33.140 ;
        RECT 42.995 35.285 43.050 35.695 ;
        RECT 43.350 35.285 43.405 35.695 ;
        RECT 46.395 35.285 46.450 35.695 ;
        RECT 46.750 35.285 46.805 35.695 ;
        RECT 41.960 35.240 42.500 35.740 ;
        RECT 45.360 35.240 45.900 35.740 ;
        RECT 41.295 24.885 41.350 25.295 ;
        RECT 41.650 24.885 41.705 25.295 ;
        RECT 44.695 24.885 44.750 25.295 ;
        RECT 45.050 24.885 45.105 25.295 ;
        RECT 43.660 24.840 44.200 25.340 ;
        RECT 47.060 24.840 47.600 25.340 ;
        RECT 42.995 26.185 43.050 26.595 ;
        RECT 43.350 26.185 43.405 26.595 ;
        RECT 46.395 26.185 46.450 26.595 ;
        RECT 46.750 26.185 46.805 26.595 ;
        RECT 41.960 26.140 42.500 26.640 ;
        RECT 45.360 26.140 45.900 26.640 ;
        RECT 41.295 27.485 41.350 27.895 ;
        RECT 41.650 27.485 41.705 27.895 ;
        RECT 44.695 27.485 44.750 27.895 ;
        RECT 45.050 27.485 45.105 27.895 ;
        RECT 43.660 27.440 44.200 27.940 ;
        RECT 47.060 27.440 47.600 27.940 ;
        RECT 42.995 28.785 43.050 29.195 ;
        RECT 43.350 28.785 43.405 29.195 ;
        RECT 46.395 28.785 46.450 29.195 ;
        RECT 46.750 28.785 46.805 29.195 ;
        RECT 41.960 28.740 42.500 29.240 ;
        RECT 45.360 28.740 45.900 29.240 ;
        RECT 41.295 30.085 41.350 30.495 ;
        RECT 41.650 30.085 41.705 30.495 ;
        RECT 44.695 30.085 44.750 30.495 ;
        RECT 45.050 30.085 45.105 30.495 ;
        RECT 43.660 30.040 44.200 30.540 ;
        RECT 47.060 30.040 47.600 30.540 ;
        RECT 42.995 31.385 43.050 31.795 ;
        RECT 43.350 31.385 43.405 31.795 ;
        RECT 46.395 31.385 46.450 31.795 ;
        RECT 46.750 31.385 46.805 31.795 ;
        RECT 41.960 31.340 42.500 31.840 ;
        RECT 45.360 31.340 45.900 31.840 ;
        RECT 53.195 28.785 53.250 29.195 ;
        RECT 53.550 28.785 53.605 29.195 ;
        RECT 48.760 26.140 49.300 26.640 ;
        RECT 52.160 26.140 52.700 26.640 ;
        RECT 49.795 35.285 49.850 35.695 ;
        RECT 50.150 35.285 50.205 35.695 ;
        RECT 53.195 35.285 53.250 35.695 ;
        RECT 53.550 35.285 53.605 35.695 ;
        RECT 48.760 28.740 49.300 29.240 ;
        RECT 52.160 28.740 52.700 29.240 ;
        RECT 48.760 35.240 49.300 35.740 ;
        RECT 52.160 35.240 52.700 35.740 ;
        RECT 51.495 24.885 51.550 25.295 ;
        RECT 51.850 24.885 51.905 25.295 ;
        RECT 48.095 24.885 48.150 25.295 ;
        RECT 48.450 24.885 48.505 25.295 ;
        RECT 48.095 30.085 48.150 30.495 ;
        RECT 48.450 30.085 48.505 30.495 ;
        RECT 51.495 30.085 51.550 30.495 ;
        RECT 51.850 30.085 51.905 30.495 ;
        RECT 48.095 27.485 48.150 27.895 ;
        RECT 48.450 27.485 48.505 27.895 ;
        RECT 50.460 30.040 51.000 30.540 ;
        RECT 53.860 30.040 54.400 30.540 ;
        RECT 51.495 27.485 51.550 27.895 ;
        RECT 51.850 27.485 51.905 27.895 ;
        RECT 49.795 26.185 49.850 26.595 ;
        RECT 50.150 26.185 50.205 26.595 ;
        RECT 49.795 31.385 49.850 31.795 ;
        RECT 50.150 31.385 50.205 31.795 ;
        RECT 53.195 31.385 53.250 31.795 ;
        RECT 53.550 31.385 53.605 31.795 ;
        RECT 50.460 27.440 51.000 27.940 ;
        RECT 53.860 27.440 54.400 27.940 ;
        RECT 48.760 31.340 49.300 31.840 ;
        RECT 52.160 31.340 52.700 31.840 ;
        RECT 53.195 26.185 53.250 26.595 ;
        RECT 53.550 26.185 53.605 26.595 ;
        RECT 50.460 24.840 51.000 25.340 ;
        RECT 53.860 24.840 54.400 25.340 ;
        RECT 48.095 32.685 48.150 33.095 ;
        RECT 48.450 32.685 48.505 33.095 ;
        RECT 51.495 32.685 51.550 33.095 ;
        RECT 51.850 32.685 51.905 33.095 ;
        RECT 49.795 28.785 49.850 29.195 ;
        RECT 50.150 28.785 50.205 29.195 ;
        RECT 50.460 32.640 51.000 33.140 ;
        RECT 53.860 32.640 54.400 33.140 ;
        RECT 34.495 36.585 34.550 36.995 ;
        RECT 34.850 36.585 34.905 36.995 ;
        RECT 37.895 36.585 37.950 36.995 ;
        RECT 38.250 36.585 38.305 36.995 ;
        RECT 36.860 36.540 37.400 37.040 ;
        RECT 40.260 36.540 40.800 37.040 ;
        RECT 36.195 37.885 36.250 38.295 ;
        RECT 36.550 37.885 36.605 38.295 ;
        RECT 39.595 37.885 39.650 38.295 ;
        RECT 39.950 37.885 40.005 38.295 ;
        RECT 35.160 37.840 35.700 38.340 ;
        RECT 38.560 37.840 39.100 38.340 ;
        RECT 34.495 39.185 34.550 39.595 ;
        RECT 34.850 39.185 34.905 39.595 ;
        RECT 37.895 39.185 37.950 39.595 ;
        RECT 38.250 39.185 38.305 39.595 ;
        RECT 35.160 46.940 35.700 47.440 ;
        RECT 38.560 46.940 39.100 47.440 ;
        RECT 36.860 39.140 37.400 39.640 ;
        RECT 40.260 39.140 40.800 39.640 ;
        RECT 36.195 40.485 36.250 40.895 ;
        RECT 36.550 40.485 36.605 40.895 ;
        RECT 39.595 40.485 39.650 40.895 ;
        RECT 39.950 40.485 40.005 40.895 ;
        RECT 35.160 40.440 35.700 40.940 ;
        RECT 38.560 40.440 39.100 40.940 ;
        RECT 34.495 41.785 34.550 42.195 ;
        RECT 34.850 41.785 34.905 42.195 ;
        RECT 37.895 41.785 37.950 42.195 ;
        RECT 38.250 41.785 38.305 42.195 ;
        RECT 36.195 46.985 36.250 47.395 ;
        RECT 36.550 46.985 36.605 47.395 ;
        RECT 36.860 41.740 37.400 42.240 ;
        RECT 40.260 41.740 40.800 42.240 ;
        RECT 36.195 43.085 36.250 43.495 ;
        RECT 36.550 43.085 36.605 43.495 ;
        RECT 39.595 43.085 39.650 43.495 ;
        RECT 39.950 43.085 40.005 43.495 ;
        RECT 39.595 46.985 39.650 47.395 ;
        RECT 39.950 46.985 40.005 47.395 ;
        RECT 35.160 43.040 35.700 43.540 ;
        RECT 38.560 43.040 39.100 43.540 ;
        RECT 34.495 44.385 34.550 44.795 ;
        RECT 34.850 44.385 34.905 44.795 ;
        RECT 37.895 44.385 37.950 44.795 ;
        RECT 38.250 44.385 38.305 44.795 ;
        RECT 36.860 44.340 37.400 44.840 ;
        RECT 40.260 44.340 40.800 44.840 ;
        RECT 28.360 37.840 28.900 38.340 ;
        RECT 31.760 37.840 32.300 38.340 ;
        RECT 28.360 40.440 28.900 40.940 ;
        RECT 31.760 40.440 32.300 40.940 ;
        RECT 27.695 36.585 27.750 36.995 ;
        RECT 28.050 36.585 28.105 36.995 ;
        RECT 27.695 41.785 27.750 42.195 ;
        RECT 28.050 41.785 28.105 42.195 ;
        RECT 31.095 41.785 31.150 42.195 ;
        RECT 31.450 41.785 31.505 42.195 ;
        RECT 27.695 39.185 27.750 39.595 ;
        RECT 28.050 39.185 28.105 39.595 ;
        RECT 31.095 39.185 31.150 39.595 ;
        RECT 31.450 39.185 31.505 39.595 ;
        RECT 29.395 37.885 29.450 38.295 ;
        RECT 29.750 37.885 29.805 38.295 ;
        RECT 30.060 41.740 30.600 42.240 ;
        RECT 33.460 41.740 34.000 42.240 ;
        RECT 32.795 37.885 32.850 38.295 ;
        RECT 33.150 37.885 33.205 38.295 ;
        RECT 29.395 43.085 29.450 43.495 ;
        RECT 29.750 43.085 29.805 43.495 ;
        RECT 32.795 43.085 32.850 43.495 ;
        RECT 33.150 43.085 33.205 43.495 ;
        RECT 28.360 46.940 28.900 47.440 ;
        RECT 31.760 46.940 32.300 47.440 ;
        RECT 31.095 36.585 31.150 36.995 ;
        RECT 31.450 36.585 31.505 36.995 ;
        RECT 30.060 39.140 30.600 39.640 ;
        RECT 33.460 39.140 34.000 39.640 ;
        RECT 28.360 43.040 28.900 43.540 ;
        RECT 31.760 43.040 32.300 43.540 ;
        RECT 30.060 36.540 30.600 37.040 ;
        RECT 33.460 36.540 34.000 37.040 ;
        RECT 27.695 44.385 27.750 44.795 ;
        RECT 28.050 44.385 28.105 44.795 ;
        RECT 31.095 44.385 31.150 44.795 ;
        RECT 31.450 44.385 31.505 44.795 ;
        RECT 29.395 40.485 29.450 40.895 ;
        RECT 29.750 40.485 29.805 40.895 ;
        RECT 32.795 40.485 32.850 40.895 ;
        RECT 33.150 40.485 33.205 40.895 ;
        RECT 30.060 44.340 30.600 44.840 ;
        RECT 33.460 44.340 34.000 44.840 ;
        RECT 32.795 46.985 32.850 47.395 ;
        RECT 33.150 46.985 33.205 47.395 ;
        RECT 29.395 46.985 29.450 47.395 ;
        RECT 29.750 46.985 29.805 47.395 ;
        RECT 29.395 31.385 29.450 31.795 ;
        RECT 29.750 31.385 29.805 31.795 ;
        RECT 28.360 26.140 28.900 26.640 ;
        RECT 31.760 26.140 32.300 26.640 ;
        RECT 27.695 32.685 27.750 33.095 ;
        RECT 28.050 32.685 28.105 33.095 ;
        RECT 32.795 26.185 32.850 26.595 ;
        RECT 33.150 26.185 33.205 26.595 ;
        RECT 28.360 35.240 28.900 35.740 ;
        RECT 31.760 35.240 32.300 35.740 ;
        RECT 31.095 24.885 31.150 25.295 ;
        RECT 31.450 24.885 31.505 25.295 ;
        RECT 32.795 31.385 32.850 31.795 ;
        RECT 33.150 31.385 33.205 31.795 ;
        RECT 31.095 32.685 31.150 33.095 ;
        RECT 31.450 32.685 31.505 33.095 ;
        RECT 31.095 27.485 31.150 27.895 ;
        RECT 31.450 27.485 31.505 27.895 ;
        RECT 28.360 28.740 28.900 29.240 ;
        RECT 31.760 28.740 32.300 29.240 ;
        RECT 31.095 30.085 31.150 30.495 ;
        RECT 31.450 30.085 31.505 30.495 ;
        RECT 30.060 27.440 30.600 27.940 ;
        RECT 33.460 27.440 34.000 27.940 ;
        RECT 30.060 30.040 30.600 30.540 ;
        RECT 33.460 30.040 34.000 30.540 ;
        RECT 32.795 35.285 32.850 35.695 ;
        RECT 33.150 35.285 33.205 35.695 ;
        RECT 32.795 28.785 32.850 29.195 ;
        RECT 33.150 28.785 33.205 29.195 ;
        RECT 27.695 30.085 27.750 30.495 ;
        RECT 28.050 30.085 28.105 30.495 ;
        RECT 27.695 24.885 27.750 25.295 ;
        RECT 28.050 24.885 28.105 25.295 ;
        RECT 30.060 32.640 30.600 33.140 ;
        RECT 33.460 32.640 34.000 33.140 ;
        RECT 29.395 26.185 29.450 26.595 ;
        RECT 29.750 26.185 29.805 26.595 ;
        RECT 27.695 27.485 27.750 27.895 ;
        RECT 28.050 27.485 28.105 27.895 ;
        RECT 28.360 31.340 28.900 31.840 ;
        RECT 31.760 31.340 32.300 31.840 ;
        RECT 29.395 28.785 29.450 29.195 ;
        RECT 29.750 28.785 29.805 29.195 ;
        RECT 29.395 35.285 29.450 35.695 ;
        RECT 29.750 35.285 29.805 35.695 ;
        RECT 30.060 24.840 30.600 25.340 ;
        RECT 33.460 24.840 34.000 25.340 ;
        RECT 36.195 31.385 36.250 31.795 ;
        RECT 36.550 31.385 36.605 31.795 ;
        RECT 39.595 31.385 39.650 31.795 ;
        RECT 39.950 31.385 40.005 31.795 ;
        RECT 35.160 35.240 35.700 35.740 ;
        RECT 38.560 35.240 39.100 35.740 ;
        RECT 36.195 26.185 36.250 26.595 ;
        RECT 36.550 26.185 36.605 26.595 ;
        RECT 34.495 32.685 34.550 33.095 ;
        RECT 34.850 32.685 34.905 33.095 ;
        RECT 37.895 32.685 37.950 33.095 ;
        RECT 38.250 32.685 38.305 33.095 ;
        RECT 35.160 28.740 35.700 29.240 ;
        RECT 38.560 28.740 39.100 29.240 ;
        RECT 34.495 27.485 34.550 27.895 ;
        RECT 34.850 27.485 34.905 27.895 ;
        RECT 37.895 27.485 37.950 27.895 ;
        RECT 38.250 27.485 38.305 27.895 ;
        RECT 36.860 30.040 37.400 30.540 ;
        RECT 40.260 30.040 40.800 30.540 ;
        RECT 36.860 27.440 37.400 27.940 ;
        RECT 40.260 27.440 40.800 27.940 ;
        RECT 34.495 30.085 34.550 30.495 ;
        RECT 34.850 30.085 34.905 30.495 ;
        RECT 37.895 30.085 37.950 30.495 ;
        RECT 38.250 30.085 38.305 30.495 ;
        RECT 34.495 24.885 34.550 25.295 ;
        RECT 34.850 24.885 34.905 25.295 ;
        RECT 39.595 26.185 39.650 26.595 ;
        RECT 39.950 26.185 40.005 26.595 ;
        RECT 36.195 28.785 36.250 29.195 ;
        RECT 36.550 28.785 36.605 29.195 ;
        RECT 35.160 31.340 35.700 31.840 ;
        RECT 38.560 31.340 39.100 31.840 ;
        RECT 36.860 32.640 37.400 33.140 ;
        RECT 40.260 32.640 40.800 33.140 ;
        RECT 37.895 24.885 37.950 25.295 ;
        RECT 38.250 24.885 38.305 25.295 ;
        RECT 35.160 26.140 35.700 26.640 ;
        RECT 38.560 26.140 39.100 26.640 ;
        RECT 39.595 28.785 39.650 29.195 ;
        RECT 39.950 28.785 40.005 29.195 ;
        RECT 36.860 24.840 37.400 25.340 ;
        RECT 40.260 24.840 40.800 25.340 ;
        RECT 39.595 35.285 39.650 35.695 ;
        RECT 39.950 35.285 40.005 35.695 ;
        RECT 36.195 35.285 36.250 35.695 ;
        RECT 36.550 35.285 36.605 35.695 ;
        RECT 29.395 11.885 29.450 12.295 ;
        RECT 29.750 11.885 29.805 12.295 ;
        RECT 32.795 11.885 32.850 12.295 ;
        RECT 33.150 11.885 33.205 12.295 ;
        RECT 36.195 11.885 36.250 12.295 ;
        RECT 36.550 11.885 36.605 12.295 ;
        RECT 39.595 11.885 39.650 12.295 ;
        RECT 39.950 11.885 40.005 12.295 ;
        RECT 28.360 11.840 28.900 12.340 ;
        RECT 31.760 11.840 32.300 12.340 ;
        RECT 35.160 11.840 35.700 12.340 ;
        RECT 38.560 11.840 39.100 12.340 ;
        RECT 34.495 15.785 34.550 16.195 ;
        RECT 34.850 15.785 34.905 16.195 ;
        RECT 37.895 15.785 37.950 16.195 ;
        RECT 38.250 15.785 38.305 16.195 ;
        RECT 34.495 13.185 34.550 13.595 ;
        RECT 34.850 13.185 34.905 13.595 ;
        RECT 37.895 13.185 37.950 13.595 ;
        RECT 38.250 13.185 38.305 13.595 ;
        RECT 36.860 18.340 37.400 18.840 ;
        RECT 40.260 18.340 40.800 18.840 ;
        RECT 36.195 14.485 36.250 14.895 ;
        RECT 36.550 14.485 36.605 14.895 ;
        RECT 39.595 14.485 39.650 14.895 ;
        RECT 39.950 14.485 40.005 14.895 ;
        RECT 36.860 15.740 37.400 16.240 ;
        RECT 40.260 15.740 40.800 16.240 ;
        RECT 34.495 18.385 34.550 18.795 ;
        RECT 34.850 18.385 34.905 18.795 ;
        RECT 37.895 18.385 37.950 18.795 ;
        RECT 38.250 18.385 38.305 18.795 ;
        RECT 36.195 23.585 36.250 23.995 ;
        RECT 36.550 23.585 36.605 23.995 ;
        RECT 39.595 23.585 39.650 23.995 ;
        RECT 39.950 23.585 40.005 23.995 ;
        RECT 36.195 19.685 36.250 20.095 ;
        RECT 36.550 19.685 36.605 20.095 ;
        RECT 39.595 19.685 39.650 20.095 ;
        RECT 39.950 19.685 40.005 20.095 ;
        RECT 35.160 23.540 35.700 24.040 ;
        RECT 38.560 23.540 39.100 24.040 ;
        RECT 36.195 17.085 36.250 17.495 ;
        RECT 36.550 17.085 36.605 17.495 ;
        RECT 39.595 17.085 39.650 17.495 ;
        RECT 39.950 17.085 40.005 17.495 ;
        RECT 35.160 19.640 35.700 20.140 ;
        RECT 38.560 19.640 39.100 20.140 ;
        RECT 35.160 14.440 35.700 14.940 ;
        RECT 38.560 14.440 39.100 14.940 ;
        RECT 36.860 13.140 37.400 13.640 ;
        RECT 40.260 13.140 40.800 13.640 ;
        RECT 34.495 20.985 34.550 21.395 ;
        RECT 34.850 20.985 34.905 21.395 ;
        RECT 37.895 20.985 37.950 21.395 ;
        RECT 38.250 20.985 38.305 21.395 ;
        RECT 35.160 17.040 35.700 17.540 ;
        RECT 38.560 17.040 39.100 17.540 ;
        RECT 36.860 20.940 37.400 21.440 ;
        RECT 40.260 20.940 40.800 21.440 ;
        RECT 27.695 13.185 27.750 13.595 ;
        RECT 28.050 13.185 28.105 13.595 ;
        RECT 28.360 23.540 28.900 24.040 ;
        RECT 31.760 23.540 32.300 24.040 ;
        RECT 31.095 13.185 31.150 13.595 ;
        RECT 31.450 13.185 31.505 13.595 ;
        RECT 29.395 17.085 29.450 17.495 ;
        RECT 29.750 17.085 29.805 17.495 ;
        RECT 32.795 17.085 32.850 17.495 ;
        RECT 33.150 17.085 33.205 17.495 ;
        RECT 30.060 15.740 30.600 16.240 ;
        RECT 33.460 15.740 34.000 16.240 ;
        RECT 31.095 15.785 31.150 16.195 ;
        RECT 31.450 15.785 31.505 16.195 ;
        RECT 28.360 19.640 28.900 20.140 ;
        RECT 31.760 19.640 32.300 20.140 ;
        RECT 27.695 18.385 27.750 18.795 ;
        RECT 28.050 18.385 28.105 18.795 ;
        RECT 28.360 14.440 28.900 14.940 ;
        RECT 31.760 14.440 32.300 14.940 ;
        RECT 29.395 14.485 29.450 14.895 ;
        RECT 29.750 14.485 29.805 14.895 ;
        RECT 30.060 13.140 30.600 13.640 ;
        RECT 33.460 13.140 34.000 13.640 ;
        RECT 32.795 14.485 32.850 14.895 ;
        RECT 33.150 14.485 33.205 14.895 ;
        RECT 27.695 20.985 27.750 21.395 ;
        RECT 28.050 20.985 28.105 21.395 ;
        RECT 31.095 20.985 31.150 21.395 ;
        RECT 31.450 20.985 31.505 21.395 ;
        RECT 30.060 18.340 30.600 18.840 ;
        RECT 33.460 18.340 34.000 18.840 ;
        RECT 29.395 19.685 29.450 20.095 ;
        RECT 29.750 19.685 29.805 20.095 ;
        RECT 28.360 17.040 28.900 17.540 ;
        RECT 31.760 17.040 32.300 17.540 ;
        RECT 32.795 19.685 32.850 20.095 ;
        RECT 33.150 19.685 33.205 20.095 ;
        RECT 29.395 23.585 29.450 23.995 ;
        RECT 29.750 23.585 29.805 23.995 ;
        RECT 32.795 23.585 32.850 23.995 ;
        RECT 33.150 23.585 33.205 23.995 ;
        RECT 30.060 20.940 30.600 21.440 ;
        RECT 33.460 20.940 34.000 21.440 ;
        RECT 31.095 18.385 31.150 18.795 ;
        RECT 31.450 18.385 31.505 18.795 ;
        RECT 27.695 15.785 27.750 16.195 ;
        RECT 28.050 15.785 28.105 16.195 ;
        RECT 30.060 4.040 30.600 4.540 ;
        RECT 33.460 4.040 34.000 4.540 ;
        RECT 31.095 9.285 31.150 9.695 ;
        RECT 31.450 9.285 31.505 9.695 ;
        RECT 27.695 6.685 27.750 7.095 ;
        RECT 28.050 6.685 28.105 7.095 ;
        RECT 31.095 6.685 31.150 7.095 ;
        RECT 31.450 6.685 31.505 7.095 ;
        RECT 30.060 6.640 30.600 7.140 ;
        RECT 33.460 6.640 34.000 7.140 ;
        RECT 30.060 1.440 30.600 1.940 ;
        RECT 33.460 1.440 34.000 1.940 ;
        RECT 28.360 7.940 28.900 8.440 ;
        RECT 31.760 7.940 32.300 8.440 ;
        RECT 28.360 0.140 28.900 0.640 ;
        RECT 31.760 0.140 32.300 0.640 ;
        RECT 29.395 5.385 29.450 5.795 ;
        RECT 29.750 5.385 29.805 5.795 ;
        RECT 28.360 2.740 28.900 3.240 ;
        RECT 31.760 2.740 32.300 3.240 ;
        RECT 32.795 5.385 32.850 5.795 ;
        RECT 33.150 5.385 33.205 5.795 ;
        RECT 28.360 5.340 28.900 5.840 ;
        RECT 31.760 5.340 32.300 5.840 ;
        RECT 30.060 9.240 30.600 9.740 ;
        RECT 33.460 9.240 34.000 9.740 ;
        RECT 27.695 9.285 27.750 9.695 ;
        RECT 28.050 9.285 28.105 9.695 ;
        RECT 29.395 2.785 29.450 3.195 ;
        RECT 29.750 2.785 29.805 3.195 ;
        RECT 27.695 4.085 27.750 4.495 ;
        RECT 28.050 4.085 28.105 4.495 ;
        RECT 31.095 4.085 31.150 4.495 ;
        RECT 31.450 4.085 31.505 4.495 ;
        RECT 32.795 2.785 32.850 3.195 ;
        RECT 33.150 2.785 33.205 3.195 ;
        RECT 29.395 7.985 29.450 8.395 ;
        RECT 29.750 7.985 29.805 8.395 ;
        RECT 27.695 1.485 27.750 1.895 ;
        RECT 28.050 1.485 28.105 1.895 ;
        RECT 31.095 1.485 31.150 1.895 ;
        RECT 31.450 1.485 31.505 1.895 ;
        RECT 29.395 0.185 29.450 0.595 ;
        RECT 29.750 0.185 29.805 0.595 ;
        RECT 32.795 0.185 32.850 0.595 ;
        RECT 33.150 0.185 33.205 0.595 ;
        RECT 32.795 7.985 32.850 8.395 ;
        RECT 33.150 7.985 33.205 8.395 ;
        RECT 35.160 2.740 35.700 3.240 ;
        RECT 38.560 2.740 39.100 3.240 ;
        RECT 36.860 4.040 37.400 4.540 ;
        RECT 40.260 4.040 40.800 4.540 ;
        RECT 36.195 7.985 36.250 8.395 ;
        RECT 36.550 7.985 36.605 8.395 ;
        RECT 39.595 7.985 39.650 8.395 ;
        RECT 39.950 7.985 40.005 8.395 ;
        RECT 36.860 9.240 37.400 9.740 ;
        RECT 40.260 9.240 40.800 9.740 ;
        RECT 36.195 5.385 36.250 5.795 ;
        RECT 36.550 5.385 36.605 5.795 ;
        RECT 39.595 5.385 39.650 5.795 ;
        RECT 39.950 5.385 40.005 5.795 ;
        RECT 36.860 1.440 37.400 1.940 ;
        RECT 40.260 1.440 40.800 1.940 ;
        RECT 34.495 9.285 34.550 9.695 ;
        RECT 34.850 9.285 34.905 9.695 ;
        RECT 36.195 2.785 36.250 3.195 ;
        RECT 36.550 2.785 36.605 3.195 ;
        RECT 39.595 2.785 39.650 3.195 ;
        RECT 39.950 2.785 40.005 3.195 ;
        RECT 34.495 4.085 34.550 4.495 ;
        RECT 34.850 4.085 34.905 4.495 ;
        RECT 37.895 4.085 37.950 4.495 ;
        RECT 38.250 4.085 38.305 4.495 ;
        RECT 37.895 9.285 37.950 9.695 ;
        RECT 38.250 9.285 38.305 9.695 ;
        RECT 36.860 6.640 37.400 7.140 ;
        RECT 40.260 6.640 40.800 7.140 ;
        RECT 34.495 6.685 34.550 7.095 ;
        RECT 34.850 6.685 34.905 7.095 ;
        RECT 37.895 6.685 37.950 7.095 ;
        RECT 38.250 6.685 38.305 7.095 ;
        RECT 34.495 1.485 34.550 1.895 ;
        RECT 34.850 1.485 34.905 1.895 ;
        RECT 37.895 1.485 37.950 1.895 ;
        RECT 38.250 1.485 38.305 1.895 ;
        RECT 35.160 7.940 35.700 8.440 ;
        RECT 38.560 7.940 39.100 8.440 ;
        RECT 35.160 5.340 35.700 5.840 ;
        RECT 38.560 5.340 39.100 5.840 ;
        RECT 36.195 0.185 36.250 0.595 ;
        RECT 36.550 0.185 36.605 0.595 ;
        RECT 39.595 0.185 39.650 0.595 ;
        RECT 39.950 0.185 40.005 0.595 ;
        RECT 35.160 0.140 35.700 0.640 ;
        RECT 38.560 0.140 39.100 0.640 ;
        RECT 49.795 11.885 49.850 12.295 ;
        RECT 50.150 11.885 50.205 12.295 ;
        RECT 53.195 11.885 53.250 12.295 ;
        RECT 53.550 11.885 53.605 12.295 ;
        RECT 41.960 11.840 42.500 12.340 ;
        RECT 45.360 11.840 45.900 12.340 ;
        RECT 48.760 11.840 49.300 12.340 ;
        RECT 52.160 11.840 52.700 12.340 ;
        RECT 42.995 11.885 43.050 12.295 ;
        RECT 43.350 11.885 43.405 12.295 ;
        RECT 46.395 11.885 46.450 12.295 ;
        RECT 46.750 11.885 46.805 12.295 ;
        RECT 49.795 23.585 49.850 23.995 ;
        RECT 50.150 23.585 50.205 23.995 ;
        RECT 53.195 23.585 53.250 23.995 ;
        RECT 53.550 23.585 53.605 23.995 ;
        RECT 48.095 15.785 48.150 16.195 ;
        RECT 48.450 15.785 48.505 16.195 ;
        RECT 51.495 15.785 51.550 16.195 ;
        RECT 51.850 15.785 51.905 16.195 ;
        RECT 49.795 19.685 49.850 20.095 ;
        RECT 50.150 19.685 50.205 20.095 ;
        RECT 53.195 19.685 53.250 20.095 ;
        RECT 53.550 19.685 53.605 20.095 ;
        RECT 48.760 17.040 49.300 17.540 ;
        RECT 52.160 17.040 52.700 17.540 ;
        RECT 48.095 13.185 48.150 13.595 ;
        RECT 48.450 13.185 48.505 13.595 ;
        RECT 51.495 13.185 51.550 13.595 ;
        RECT 51.850 13.185 51.905 13.595 ;
        RECT 48.760 19.640 49.300 20.140 ;
        RECT 52.160 19.640 52.700 20.140 ;
        RECT 48.760 14.440 49.300 14.940 ;
        RECT 52.160 14.440 52.700 14.940 ;
        RECT 50.460 15.740 51.000 16.240 ;
        RECT 53.860 15.740 54.400 16.240 ;
        RECT 49.795 14.485 49.850 14.895 ;
        RECT 50.150 14.485 50.205 14.895 ;
        RECT 53.195 14.485 53.250 14.895 ;
        RECT 53.550 14.485 53.605 14.895 ;
        RECT 48.095 18.385 48.150 18.795 ;
        RECT 48.450 18.385 48.505 18.795 ;
        RECT 51.495 18.385 51.550 18.795 ;
        RECT 51.850 18.385 51.905 18.795 ;
        RECT 48.095 20.985 48.150 21.395 ;
        RECT 48.450 20.985 48.505 21.395 ;
        RECT 51.495 20.985 51.550 21.395 ;
        RECT 51.850 20.985 51.905 21.395 ;
        RECT 48.760 23.540 49.300 24.040 ;
        RECT 52.160 23.540 52.700 24.040 ;
        RECT 49.795 17.085 49.850 17.495 ;
        RECT 50.150 17.085 50.205 17.495 ;
        RECT 53.195 17.085 53.250 17.495 ;
        RECT 53.550 17.085 53.605 17.495 ;
        RECT 50.460 20.940 51.000 21.440 ;
        RECT 53.860 20.940 54.400 21.440 ;
        RECT 50.460 18.340 51.000 18.840 ;
        RECT 53.860 18.340 54.400 18.840 ;
        RECT 50.460 13.140 51.000 13.640 ;
        RECT 53.860 13.140 54.400 13.640 ;
        RECT 43.660 15.740 44.200 16.240 ;
        RECT 47.060 15.740 47.600 16.240 ;
        RECT 44.695 15.785 44.750 16.195 ;
        RECT 45.050 15.785 45.105 16.195 ;
        RECT 41.960 17.040 42.500 17.540 ;
        RECT 45.360 17.040 45.900 17.540 ;
        RECT 42.995 17.085 43.050 17.495 ;
        RECT 43.350 17.085 43.405 17.495 ;
        RECT 41.295 18.385 41.350 18.795 ;
        RECT 41.650 18.385 41.705 18.795 ;
        RECT 44.695 18.385 44.750 18.795 ;
        RECT 45.050 18.385 45.105 18.795 ;
        RECT 41.295 13.185 41.350 13.595 ;
        RECT 41.650 13.185 41.705 13.595 ;
        RECT 44.695 13.185 44.750 13.595 ;
        RECT 45.050 13.185 45.105 13.595 ;
        RECT 41.295 20.985 41.350 21.395 ;
        RECT 41.650 20.985 41.705 21.395 ;
        RECT 44.695 20.985 44.750 21.395 ;
        RECT 45.050 20.985 45.105 21.395 ;
        RECT 46.395 17.085 46.450 17.495 ;
        RECT 46.750 17.085 46.805 17.495 ;
        RECT 42.995 19.685 43.050 20.095 ;
        RECT 43.350 19.685 43.405 20.095 ;
        RECT 41.960 23.540 42.500 24.040 ;
        RECT 45.360 23.540 45.900 24.040 ;
        RECT 42.995 23.585 43.050 23.995 ;
        RECT 43.350 23.585 43.405 23.995 ;
        RECT 46.395 23.585 46.450 23.995 ;
        RECT 46.750 23.585 46.805 23.995 ;
        RECT 41.960 19.640 42.500 20.140 ;
        RECT 45.360 19.640 45.900 20.140 ;
        RECT 43.660 20.940 44.200 21.440 ;
        RECT 47.060 20.940 47.600 21.440 ;
        RECT 46.395 19.685 46.450 20.095 ;
        RECT 46.750 19.685 46.805 20.095 ;
        RECT 43.660 18.340 44.200 18.840 ;
        RECT 47.060 18.340 47.600 18.840 ;
        RECT 41.960 14.440 42.500 14.940 ;
        RECT 45.360 14.440 45.900 14.940 ;
        RECT 43.660 13.140 44.200 13.640 ;
        RECT 47.060 13.140 47.600 13.640 ;
        RECT 41.295 15.785 41.350 16.195 ;
        RECT 41.650 15.785 41.705 16.195 ;
        RECT 42.995 14.485 43.050 14.895 ;
        RECT 43.350 14.485 43.405 14.895 ;
        RECT 46.395 14.485 46.450 14.895 ;
        RECT 46.750 14.485 46.805 14.895 ;
        RECT 44.695 9.285 44.750 9.695 ;
        RECT 45.050 9.285 45.105 9.695 ;
        RECT 41.960 5.340 42.500 5.840 ;
        RECT 45.360 5.340 45.900 5.840 ;
        RECT 43.660 4.040 44.200 4.540 ;
        RECT 47.060 4.040 47.600 4.540 ;
        RECT 41.960 7.940 42.500 8.440 ;
        RECT 45.360 7.940 45.900 8.440 ;
        RECT 43.660 9.240 44.200 9.740 ;
        RECT 47.060 9.240 47.600 9.740 ;
        RECT 42.995 7.985 43.050 8.395 ;
        RECT 43.350 7.985 43.405 8.395 ;
        RECT 46.395 7.985 46.450 8.395 ;
        RECT 46.750 7.985 46.805 8.395 ;
        RECT 41.960 2.740 42.500 3.240 ;
        RECT 45.360 2.740 45.900 3.240 ;
        RECT 41.295 1.485 41.350 1.895 ;
        RECT 41.650 1.485 41.705 1.895 ;
        RECT 44.695 1.485 44.750 1.895 ;
        RECT 45.050 1.485 45.105 1.895 ;
        RECT 42.995 5.385 43.050 5.795 ;
        RECT 43.350 5.385 43.405 5.795 ;
        RECT 46.395 5.385 46.450 5.795 ;
        RECT 46.750 5.385 46.805 5.795 ;
        RECT 41.295 6.685 41.350 7.095 ;
        RECT 41.650 6.685 41.705 7.095 ;
        RECT 44.695 6.685 44.750 7.095 ;
        RECT 45.050 6.685 45.105 7.095 ;
        RECT 41.960 0.140 42.500 0.640 ;
        RECT 45.360 0.140 45.900 0.640 ;
        RECT 43.660 1.440 44.200 1.940 ;
        RECT 47.060 1.440 47.600 1.940 ;
        RECT 42.995 2.785 43.050 3.195 ;
        RECT 43.350 2.785 43.405 3.195 ;
        RECT 46.395 2.785 46.450 3.195 ;
        RECT 46.750 2.785 46.805 3.195 ;
        RECT 42.995 0.185 43.050 0.595 ;
        RECT 43.350 0.185 43.405 0.595 ;
        RECT 46.395 0.185 46.450 0.595 ;
        RECT 46.750 0.185 46.805 0.595 ;
        RECT 43.660 6.640 44.200 7.140 ;
        RECT 47.060 6.640 47.600 7.140 ;
        RECT 41.295 9.285 41.350 9.695 ;
        RECT 41.650 9.285 41.705 9.695 ;
        RECT 41.295 4.085 41.350 4.495 ;
        RECT 41.650 4.085 41.705 4.495 ;
        RECT 44.695 4.085 44.750 4.495 ;
        RECT 45.050 4.085 45.105 4.495 ;
        RECT 48.095 9.285 48.150 9.695 ;
        RECT 48.450 9.285 48.505 9.695 ;
        RECT 51.495 9.285 51.550 9.695 ;
        RECT 51.850 9.285 51.905 9.695 ;
        RECT 48.760 2.740 49.300 3.240 ;
        RECT 52.160 2.740 52.700 3.240 ;
        RECT 48.760 0.140 49.300 0.640 ;
        RECT 52.160 0.140 52.700 0.640 ;
        RECT 49.795 7.985 49.850 8.395 ;
        RECT 50.150 7.985 50.205 8.395 ;
        RECT 48.760 5.340 49.300 5.840 ;
        RECT 52.160 5.340 52.700 5.840 ;
        RECT 53.195 7.985 53.250 8.395 ;
        RECT 53.550 7.985 53.605 8.395 ;
        RECT 49.795 5.385 49.850 5.795 ;
        RECT 50.150 5.385 50.205 5.795 ;
        RECT 53.195 5.385 53.250 5.795 ;
        RECT 53.550 5.385 53.605 5.795 ;
        RECT 50.460 4.040 51.000 4.540 ;
        RECT 53.860 4.040 54.400 4.540 ;
        RECT 48.095 6.685 48.150 7.095 ;
        RECT 48.450 6.685 48.505 7.095 ;
        RECT 51.495 6.685 51.550 7.095 ;
        RECT 51.850 6.685 51.905 7.095 ;
        RECT 53.195 2.785 53.250 3.195 ;
        RECT 53.550 2.785 53.605 3.195 ;
        RECT 50.460 1.440 51.000 1.940 ;
        RECT 53.860 1.440 54.400 1.940 ;
        RECT 51.495 4.085 51.550 4.495 ;
        RECT 51.850 4.085 51.905 4.495 ;
        RECT 50.460 6.640 51.000 7.140 ;
        RECT 53.860 6.640 54.400 7.140 ;
        RECT 48.095 1.485 48.150 1.895 ;
        RECT 48.450 1.485 48.505 1.895 ;
        RECT 49.795 0.185 49.850 0.595 ;
        RECT 50.150 0.185 50.205 0.595 ;
        RECT 53.195 0.185 53.250 0.595 ;
        RECT 53.550 0.185 53.605 0.595 ;
        RECT 48.760 7.940 49.300 8.440 ;
        RECT 52.160 7.940 52.700 8.440 ;
        RECT 51.495 1.485 51.550 1.895 ;
        RECT 51.850 1.485 51.905 1.895 ;
        RECT 50.460 9.240 51.000 9.740 ;
        RECT 53.860 9.240 54.400 9.740 ;
        RECT 49.795 2.785 49.850 3.195 ;
        RECT 50.150 2.785 50.205 3.195 ;
        RECT 48.095 4.085 48.150 4.495 ;
        RECT 48.450 4.085 48.505 4.495 ;
      LAYER met4 ;
        RECT 30.060 71.640 30.300 72.140 ;
        RECT 33.460 71.640 33.700 72.140 ;
        RECT 36.860 71.640 37.100 72.140 ;
        RECT 40.260 71.640 40.500 72.140 ;
        RECT 43.660 71.640 43.900 72.140 ;
        RECT 47.060 71.640 47.300 72.140 ;
        RECT 50.460 71.640 50.700 72.140 ;
        RECT 53.860 71.640 54.100 72.140 ;
        RECT 41.960 72.940 42.200 73.440 ;
        RECT 45.360 72.940 45.600 73.440 ;
        RECT 48.760 72.940 49.000 73.440 ;
        RECT 52.160 72.940 52.400 73.440 ;
        RECT 43.660 74.240 43.900 74.740 ;
        RECT 47.060 74.240 47.300 74.740 ;
        RECT 50.460 74.240 50.700 74.740 ;
        RECT 53.860 74.240 54.100 74.740 ;
        RECT 41.960 75.540 42.200 76.040 ;
        RECT 45.360 75.540 45.600 76.040 ;
        RECT 48.760 75.540 49.000 76.040 ;
        RECT 52.160 75.540 52.400 76.040 ;
        RECT 43.660 76.840 43.900 77.340 ;
        RECT 47.060 76.840 47.300 77.340 ;
        RECT 50.460 76.840 50.700 77.340 ;
        RECT 53.860 76.840 54.100 77.340 ;
        RECT 41.960 78.140 42.200 78.640 ;
        RECT 45.360 78.140 45.600 78.640 ;
        RECT 48.760 78.140 49.000 78.640 ;
        RECT 52.160 78.140 52.400 78.640 ;
        RECT 43.660 79.440 43.900 79.940 ;
        RECT 47.060 79.440 47.300 79.940 ;
        RECT 50.460 79.440 50.700 79.940 ;
        RECT 53.860 79.440 54.100 79.940 ;
        RECT 41.960 82.040 42.200 82.540 ;
        RECT 45.360 82.040 45.600 82.540 ;
        RECT 48.760 82.040 49.000 82.540 ;
        RECT 52.160 82.040 52.400 82.540 ;
        RECT 43.660 83.340 43.900 83.840 ;
        RECT 47.060 83.340 47.300 83.840 ;
        RECT 50.460 83.340 50.700 83.840 ;
        RECT 53.860 83.340 54.100 83.840 ;
        RECT 41.960 84.640 42.200 85.140 ;
        RECT 45.360 84.640 45.600 85.140 ;
        RECT 48.760 84.640 49.000 85.140 ;
        RECT 52.160 84.640 52.400 85.140 ;
        RECT 43.660 85.940 43.900 86.440 ;
        RECT 47.060 85.940 47.300 86.440 ;
        RECT 50.460 85.940 50.700 86.440 ;
        RECT 53.860 85.940 54.100 86.440 ;
        RECT 41.960 87.240 42.200 87.740 ;
        RECT 45.360 87.240 45.600 87.740 ;
        RECT 48.760 87.240 49.000 87.740 ;
        RECT 52.160 87.240 52.400 87.740 ;
        RECT 43.660 88.540 43.900 89.040 ;
        RECT 47.060 88.540 47.300 89.040 ;
        RECT 50.460 88.540 50.700 89.040 ;
        RECT 53.860 88.540 54.100 89.040 ;
        RECT 41.960 89.840 42.200 90.340 ;
        RECT 45.360 89.840 45.600 90.340 ;
        RECT 48.760 89.840 49.000 90.340 ;
        RECT 52.160 89.840 52.400 90.340 ;
        RECT 43.660 91.140 43.900 91.640 ;
        RECT 47.060 91.140 47.300 91.640 ;
        RECT 50.460 91.140 50.700 91.640 ;
        RECT 53.860 91.140 54.100 91.640 ;
        RECT 42.000 95.160 42.200 95.660 ;
        RECT 43.700 95.160 43.900 95.660 ;
        RECT 45.400 95.160 45.600 95.660 ;
        RECT 47.100 95.160 47.300 95.660 ;
        RECT 48.800 95.160 49.000 95.660 ;
        RECT 50.500 95.160 50.700 95.660 ;
        RECT 52.200 95.160 52.400 95.660 ;
        RECT 53.900 95.160 54.100 95.660 ;
        RECT 28.360 84.640 28.600 85.140 ;
        RECT 31.760 84.640 32.000 85.140 ;
        RECT 35.160 84.640 35.400 85.140 ;
        RECT 38.560 84.640 38.800 85.140 ;
        RECT 28.360 78.140 28.600 78.640 ;
        RECT 31.760 78.140 32.000 78.640 ;
        RECT 35.160 78.140 35.400 78.640 ;
        RECT 38.560 78.140 38.800 78.640 ;
        RECT 30.060 85.940 30.300 86.440 ;
        RECT 33.460 85.940 33.700 86.440 ;
        RECT 36.860 85.940 37.100 86.440 ;
        RECT 40.260 85.940 40.500 86.440 ;
        RECT 28.360 75.540 28.600 76.040 ;
        RECT 31.760 75.540 32.000 76.040 ;
        RECT 35.160 75.540 35.400 76.040 ;
        RECT 38.560 75.540 38.800 76.040 ;
        RECT 28.360 87.240 28.600 87.740 ;
        RECT 31.760 87.240 32.000 87.740 ;
        RECT 35.160 87.240 35.400 87.740 ;
        RECT 38.560 87.240 38.800 87.740 ;
        RECT 30.060 79.440 30.300 79.940 ;
        RECT 33.460 79.440 33.700 79.940 ;
        RECT 36.860 79.440 37.100 79.940 ;
        RECT 40.260 79.440 40.500 79.940 ;
        RECT 30.060 88.540 30.300 89.040 ;
        RECT 33.460 88.540 33.700 89.040 ;
        RECT 36.860 88.540 37.100 89.040 ;
        RECT 40.260 88.540 40.500 89.040 ;
        RECT 30.060 74.240 30.300 74.740 ;
        RECT 33.460 74.240 33.700 74.740 ;
        RECT 36.860 74.240 37.100 74.740 ;
        RECT 40.260 74.240 40.500 74.740 ;
        RECT 28.360 89.840 28.600 90.340 ;
        RECT 31.760 89.840 32.000 90.340 ;
        RECT 35.160 89.840 35.400 90.340 ;
        RECT 38.560 89.840 38.800 90.340 ;
        RECT 28.360 82.040 28.600 82.540 ;
        RECT 31.760 82.040 32.000 82.540 ;
        RECT 35.160 82.040 35.400 82.540 ;
        RECT 38.560 82.040 38.800 82.540 ;
        RECT 30.060 91.140 30.300 91.640 ;
        RECT 33.460 91.140 33.700 91.640 ;
        RECT 36.860 91.140 37.100 91.640 ;
        RECT 40.260 91.140 40.500 91.640 ;
        RECT 30.060 76.840 30.300 77.340 ;
        RECT 33.460 76.840 33.700 77.340 ;
        RECT 36.860 76.840 37.100 77.340 ;
        RECT 40.260 76.840 40.500 77.340 ;
        RECT 28.400 95.160 28.600 95.660 ;
        RECT 30.100 95.160 30.300 95.660 ;
        RECT 31.800 95.160 32.000 95.660 ;
        RECT 33.500 95.160 33.700 95.660 ;
        RECT 35.200 95.160 35.400 95.660 ;
        RECT 36.900 95.160 37.100 95.660 ;
        RECT 38.600 95.160 38.800 95.660 ;
        RECT 40.300 95.160 40.500 95.660 ;
        RECT 30.060 83.340 30.300 83.840 ;
        RECT 33.460 83.340 33.700 83.840 ;
        RECT 36.860 83.340 37.100 83.840 ;
        RECT 40.260 83.340 40.500 83.840 ;
        RECT 28.360 72.940 28.600 73.440 ;
        RECT 31.760 72.940 32.000 73.440 ;
        RECT 35.160 72.940 35.400 73.440 ;
        RECT 38.560 72.940 38.800 73.440 ;
        RECT 30.060 50.840 30.300 51.340 ;
        RECT 33.460 50.840 33.700 51.340 ;
        RECT 36.860 50.840 37.100 51.340 ;
        RECT 40.260 50.840 40.500 51.340 ;
        RECT 28.360 52.140 28.600 52.640 ;
        RECT 31.760 52.140 32.000 52.640 ;
        RECT 35.160 52.140 35.400 52.640 ;
        RECT 38.560 52.140 38.800 52.640 ;
        RECT 30.060 53.440 30.300 53.940 ;
        RECT 33.460 53.440 33.700 53.940 ;
        RECT 36.860 53.440 37.100 53.940 ;
        RECT 40.260 53.440 40.500 53.940 ;
        RECT 28.360 54.740 28.600 55.240 ;
        RECT 31.760 54.740 32.000 55.240 ;
        RECT 35.160 54.740 35.400 55.240 ;
        RECT 38.560 54.740 38.800 55.240 ;
        RECT 30.060 56.040 30.300 56.540 ;
        RECT 33.460 56.040 33.700 56.540 ;
        RECT 36.860 56.040 37.100 56.540 ;
        RECT 40.260 56.040 40.500 56.540 ;
        RECT 28.360 58.640 28.600 59.140 ;
        RECT 31.760 58.640 32.000 59.140 ;
        RECT 35.160 58.640 35.400 59.140 ;
        RECT 38.560 58.640 38.800 59.140 ;
        RECT 30.060 59.940 30.300 60.440 ;
        RECT 33.460 59.940 33.700 60.440 ;
        RECT 36.860 59.940 37.100 60.440 ;
        RECT 40.260 59.940 40.500 60.440 ;
        RECT 28.360 61.240 28.600 61.740 ;
        RECT 31.760 61.240 32.000 61.740 ;
        RECT 35.160 61.240 35.400 61.740 ;
        RECT 38.560 61.240 38.800 61.740 ;
        RECT 30.060 62.540 30.300 63.040 ;
        RECT 33.460 62.540 33.700 63.040 ;
        RECT 36.860 62.540 37.100 63.040 ;
        RECT 40.260 62.540 40.500 63.040 ;
        RECT 28.360 63.840 28.600 64.340 ;
        RECT 31.760 63.840 32.000 64.340 ;
        RECT 35.160 63.840 35.400 64.340 ;
        RECT 38.560 63.840 38.800 64.340 ;
        RECT 30.060 65.140 30.300 65.640 ;
        RECT 33.460 65.140 33.700 65.640 ;
        RECT 36.860 65.140 37.100 65.640 ;
        RECT 40.260 65.140 40.500 65.640 ;
        RECT 28.360 66.440 28.600 66.940 ;
        RECT 31.760 66.440 32.000 66.940 ;
        RECT 35.160 66.440 35.400 66.940 ;
        RECT 38.560 66.440 38.800 66.940 ;
        RECT 30.060 67.740 30.300 68.240 ;
        RECT 33.460 67.740 33.700 68.240 ;
        RECT 36.860 67.740 37.100 68.240 ;
        RECT 40.260 67.740 40.500 68.240 ;
        RECT 28.360 70.340 28.600 70.840 ;
        RECT 31.760 70.340 32.000 70.840 ;
        RECT 35.160 70.340 35.400 70.840 ;
        RECT 38.560 70.340 38.800 70.840 ;
        RECT 30.060 48.240 30.300 48.740 ;
        RECT 33.460 48.240 33.700 48.740 ;
        RECT 36.860 48.240 37.100 48.740 ;
        RECT 40.260 48.240 40.500 48.740 ;
        RECT 28.360 49.540 28.600 50.040 ;
        RECT 31.760 49.540 32.000 50.040 ;
        RECT 35.160 49.540 35.400 50.040 ;
        RECT 38.560 49.540 38.800 50.040 ;
        RECT 43.660 53.440 43.900 53.940 ;
        RECT 47.060 53.440 47.300 53.940 ;
        RECT 50.460 53.440 50.700 53.940 ;
        RECT 53.860 53.440 54.100 53.940 ;
        RECT 41.960 61.240 42.200 61.740 ;
        RECT 45.360 61.240 45.600 61.740 ;
        RECT 48.760 61.240 49.000 61.740 ;
        RECT 52.160 61.240 52.400 61.740 ;
        RECT 43.660 50.840 43.900 51.340 ;
        RECT 47.060 50.840 47.300 51.340 ;
        RECT 50.460 50.840 50.700 51.340 ;
        RECT 53.860 50.840 54.100 51.340 ;
        RECT 43.660 62.540 43.900 63.040 ;
        RECT 47.060 62.540 47.300 63.040 ;
        RECT 50.460 62.540 50.700 63.040 ;
        RECT 53.860 62.540 54.100 63.040 ;
        RECT 41.960 54.740 42.200 55.240 ;
        RECT 45.360 54.740 45.600 55.240 ;
        RECT 48.760 54.740 49.000 55.240 ;
        RECT 52.160 54.740 52.400 55.240 ;
        RECT 41.960 63.840 42.200 64.340 ;
        RECT 45.360 63.840 45.600 64.340 ;
        RECT 48.760 63.840 49.000 64.340 ;
        RECT 52.160 63.840 52.400 64.340 ;
        RECT 41.960 49.540 42.200 50.040 ;
        RECT 45.360 49.540 45.600 50.040 ;
        RECT 48.760 49.540 49.000 50.040 ;
        RECT 52.160 49.540 52.400 50.040 ;
        RECT 43.660 65.140 43.900 65.640 ;
        RECT 47.060 65.140 47.300 65.640 ;
        RECT 50.460 65.140 50.700 65.640 ;
        RECT 53.860 65.140 54.100 65.640 ;
        RECT 43.660 56.040 43.900 56.540 ;
        RECT 47.060 56.040 47.300 56.540 ;
        RECT 50.460 56.040 50.700 56.540 ;
        RECT 53.860 56.040 54.100 56.540 ;
        RECT 41.960 66.440 42.200 66.940 ;
        RECT 45.360 66.440 45.600 66.940 ;
        RECT 48.760 66.440 49.000 66.940 ;
        RECT 52.160 66.440 52.400 66.940 ;
        RECT 41.960 52.140 42.200 52.640 ;
        RECT 45.360 52.140 45.600 52.640 ;
        RECT 48.760 52.140 49.000 52.640 ;
        RECT 52.160 52.140 52.400 52.640 ;
        RECT 43.660 67.740 43.900 68.240 ;
        RECT 47.060 67.740 47.300 68.240 ;
        RECT 50.460 67.740 50.700 68.240 ;
        RECT 53.860 67.740 54.100 68.240 ;
        RECT 41.960 58.640 42.200 59.140 ;
        RECT 45.360 58.640 45.600 59.140 ;
        RECT 48.760 58.640 49.000 59.140 ;
        RECT 52.160 58.640 52.400 59.140 ;
        RECT 41.960 70.340 42.200 70.840 ;
        RECT 45.360 70.340 45.600 70.840 ;
        RECT 48.760 70.340 49.000 70.840 ;
        RECT 52.160 70.340 52.400 70.840 ;
        RECT 43.660 48.240 43.900 48.740 ;
        RECT 47.060 48.240 47.300 48.740 ;
        RECT 50.460 48.240 50.700 48.740 ;
        RECT 53.860 48.240 54.100 48.740 ;
        RECT 43.660 59.940 43.900 60.440 ;
        RECT 47.060 59.940 47.300 60.440 ;
        RECT 50.460 59.940 50.700 60.440 ;
        RECT 53.860 59.940 54.100 60.440 ;
        RECT 2.860 71.640 3.100 72.140 ;
        RECT 6.260 71.640 6.500 72.140 ;
        RECT 9.660 71.640 9.900 72.140 ;
        RECT 13.060 71.640 13.300 72.140 ;
        RECT 16.460 71.640 16.700 72.140 ;
        RECT 19.860 71.640 20.100 72.140 ;
        RECT 23.260 71.640 23.500 72.140 ;
        RECT 26.660 71.640 26.900 72.140 ;
        RECT 14.760 75.540 15.000 76.040 ;
        RECT 18.160 75.540 18.400 76.040 ;
        RECT 21.560 75.540 21.800 76.040 ;
        RECT 24.960 75.540 25.200 76.040 ;
        RECT 16.460 76.840 16.700 77.340 ;
        RECT 19.860 76.840 20.100 77.340 ;
        RECT 23.260 76.840 23.500 77.340 ;
        RECT 26.660 76.840 26.900 77.340 ;
        RECT 14.760 78.140 15.000 78.640 ;
        RECT 18.160 78.140 18.400 78.640 ;
        RECT 21.560 78.140 21.800 78.640 ;
        RECT 24.960 78.140 25.200 78.640 ;
        RECT 16.460 79.440 16.700 79.940 ;
        RECT 19.860 79.440 20.100 79.940 ;
        RECT 23.260 79.440 23.500 79.940 ;
        RECT 26.660 79.440 26.900 79.940 ;
        RECT 14.760 82.040 15.000 82.540 ;
        RECT 18.160 82.040 18.400 82.540 ;
        RECT 21.560 82.040 21.800 82.540 ;
        RECT 24.960 82.040 25.200 82.540 ;
        RECT 16.460 83.340 16.700 83.840 ;
        RECT 19.860 83.340 20.100 83.840 ;
        RECT 23.260 83.340 23.500 83.840 ;
        RECT 26.660 83.340 26.900 83.840 ;
        RECT 14.760 84.640 15.000 85.140 ;
        RECT 18.160 84.640 18.400 85.140 ;
        RECT 21.560 84.640 21.800 85.140 ;
        RECT 24.960 84.640 25.200 85.140 ;
        RECT 16.460 85.940 16.700 86.440 ;
        RECT 19.860 85.940 20.100 86.440 ;
        RECT 23.260 85.940 23.500 86.440 ;
        RECT 26.660 85.940 26.900 86.440 ;
        RECT 14.760 87.240 15.000 87.740 ;
        RECT 18.160 87.240 18.400 87.740 ;
        RECT 21.560 87.240 21.800 87.740 ;
        RECT 24.960 87.240 25.200 87.740 ;
        RECT 16.460 88.540 16.700 89.040 ;
        RECT 19.860 88.540 20.100 89.040 ;
        RECT 23.260 88.540 23.500 89.040 ;
        RECT 26.660 88.540 26.900 89.040 ;
        RECT 14.760 89.840 15.000 90.340 ;
        RECT 18.160 89.840 18.400 90.340 ;
        RECT 21.560 89.840 21.800 90.340 ;
        RECT 24.960 89.840 25.200 90.340 ;
        RECT 16.460 91.140 16.700 91.640 ;
        RECT 19.860 91.140 20.100 91.640 ;
        RECT 23.260 91.140 23.500 91.640 ;
        RECT 26.660 91.140 26.900 91.640 ;
        RECT 14.800 95.160 15.000 95.660 ;
        RECT 16.500 95.160 16.700 95.660 ;
        RECT 18.200 95.160 18.400 95.660 ;
        RECT 19.900 95.160 20.100 95.660 ;
        RECT 21.600 95.160 21.800 95.660 ;
        RECT 23.300 95.160 23.500 95.660 ;
        RECT 25.000 95.160 25.200 95.660 ;
        RECT 26.700 95.160 26.900 95.660 ;
        RECT 14.760 72.940 15.000 73.440 ;
        RECT 18.160 72.940 18.400 73.440 ;
        RECT 21.560 72.940 21.800 73.440 ;
        RECT 24.960 72.940 25.200 73.440 ;
        RECT 16.460 74.240 16.700 74.740 ;
        RECT 19.860 74.240 20.100 74.740 ;
        RECT 23.260 74.240 23.500 74.740 ;
        RECT 26.660 74.240 26.900 74.740 ;
        RECT 2.860 85.940 3.100 86.440 ;
        RECT 6.260 85.940 6.500 86.440 ;
        RECT 9.660 85.940 9.900 86.440 ;
        RECT 13.060 85.940 13.300 86.440 ;
        RECT 1.160 75.540 1.400 76.040 ;
        RECT 4.560 75.540 4.800 76.040 ;
        RECT 7.960 75.540 8.200 76.040 ;
        RECT 11.360 75.540 11.600 76.040 ;
        RECT 1.160 87.240 1.400 87.740 ;
        RECT 4.560 87.240 4.800 87.740 ;
        RECT 7.960 87.240 8.200 87.740 ;
        RECT 11.360 87.240 11.600 87.740 ;
        RECT 2.860 79.440 3.100 79.940 ;
        RECT 6.260 79.440 6.500 79.940 ;
        RECT 9.660 79.440 9.900 79.940 ;
        RECT 13.060 79.440 13.300 79.940 ;
        RECT 2.860 88.540 3.100 89.040 ;
        RECT 6.260 88.540 6.500 89.040 ;
        RECT 9.660 88.540 9.900 89.040 ;
        RECT 13.060 88.540 13.300 89.040 ;
        RECT 2.860 74.240 3.100 74.740 ;
        RECT 6.260 74.240 6.500 74.740 ;
        RECT 9.660 74.240 9.900 74.740 ;
        RECT 13.060 74.240 13.300 74.740 ;
        RECT 1.160 89.840 1.400 90.340 ;
        RECT 4.560 89.840 4.800 90.340 ;
        RECT 7.960 89.840 8.200 90.340 ;
        RECT 11.360 89.840 11.600 90.340 ;
        RECT 1.160 82.040 1.400 82.540 ;
        RECT 4.560 82.040 4.800 82.540 ;
        RECT 7.960 82.040 8.200 82.540 ;
        RECT 11.360 82.040 11.600 82.540 ;
        RECT 2.860 91.140 3.100 91.640 ;
        RECT 6.260 91.140 6.500 91.640 ;
        RECT 9.660 91.140 9.900 91.640 ;
        RECT 13.060 91.140 13.300 91.640 ;
        RECT 2.860 76.840 3.100 77.340 ;
        RECT 6.260 76.840 6.500 77.340 ;
        RECT 9.660 76.840 9.900 77.340 ;
        RECT 13.060 76.840 13.300 77.340 ;
        RECT 1.200 95.160 1.400 95.660 ;
        RECT 2.900 95.160 3.100 95.660 ;
        RECT 4.600 95.160 4.800 95.660 ;
        RECT 6.300 95.160 6.500 95.660 ;
        RECT 8.000 95.160 8.200 95.660 ;
        RECT 9.700 95.160 9.900 95.660 ;
        RECT 11.400 95.160 11.600 95.660 ;
        RECT 13.100 95.160 13.300 95.660 ;
        RECT 2.860 83.340 3.100 83.840 ;
        RECT 6.260 83.340 6.500 83.840 ;
        RECT 9.660 83.340 9.900 83.840 ;
        RECT 13.060 83.340 13.300 83.840 ;
        RECT 1.160 72.940 1.400 73.440 ;
        RECT 4.560 72.940 4.800 73.440 ;
        RECT 7.960 72.940 8.200 73.440 ;
        RECT 11.360 72.940 11.600 73.440 ;
        RECT 1.160 84.640 1.400 85.140 ;
        RECT 4.560 84.640 4.800 85.140 ;
        RECT 7.960 84.640 8.200 85.140 ;
        RECT 11.360 84.640 11.600 85.140 ;
        RECT 1.160 78.140 1.400 78.640 ;
        RECT 4.560 78.140 4.800 78.640 ;
        RECT 7.960 78.140 8.200 78.640 ;
        RECT 11.360 78.140 11.600 78.640 ;
        RECT 2.860 50.840 3.100 51.340 ;
        RECT 6.260 50.840 6.500 51.340 ;
        RECT 9.660 50.840 9.900 51.340 ;
        RECT 13.060 50.840 13.300 51.340 ;
        RECT 1.160 54.740 1.400 55.240 ;
        RECT 4.560 54.740 4.800 55.240 ;
        RECT 7.960 54.740 8.200 55.240 ;
        RECT 11.360 54.740 11.600 55.240 ;
        RECT 2.860 67.740 3.100 68.240 ;
        RECT 6.260 67.740 6.500 68.240 ;
        RECT 9.660 67.740 9.900 68.240 ;
        RECT 13.060 67.740 13.300 68.240 ;
        RECT 2.860 65.140 3.100 65.640 ;
        RECT 6.260 65.140 6.500 65.640 ;
        RECT 9.660 65.140 9.900 65.640 ;
        RECT 13.060 65.140 13.300 65.640 ;
        RECT 1.160 61.240 1.400 61.740 ;
        RECT 4.560 61.240 4.800 61.740 ;
        RECT 7.960 61.240 8.200 61.740 ;
        RECT 11.360 61.240 11.600 61.740 ;
        RECT 1.160 58.640 1.400 59.140 ;
        RECT 4.560 58.640 4.800 59.140 ;
        RECT 7.960 58.640 8.200 59.140 ;
        RECT 11.360 58.640 11.600 59.140 ;
        RECT 2.860 59.940 3.100 60.440 ;
        RECT 6.260 59.940 6.500 60.440 ;
        RECT 9.660 59.940 9.900 60.440 ;
        RECT 13.060 59.940 13.300 60.440 ;
        RECT 2.860 56.040 3.100 56.540 ;
        RECT 6.260 56.040 6.500 56.540 ;
        RECT 9.660 56.040 9.900 56.540 ;
        RECT 13.060 56.040 13.300 56.540 ;
        RECT 1.160 70.340 1.400 70.840 ;
        RECT 4.560 70.340 4.800 70.840 ;
        RECT 7.960 70.340 8.200 70.840 ;
        RECT 11.360 70.340 11.600 70.840 ;
        RECT 1.160 63.840 1.400 64.340 ;
        RECT 4.560 63.840 4.800 64.340 ;
        RECT 7.960 63.840 8.200 64.340 ;
        RECT 11.360 63.840 11.600 64.340 ;
        RECT 2.860 62.540 3.100 63.040 ;
        RECT 6.260 62.540 6.500 63.040 ;
        RECT 9.660 62.540 9.900 63.040 ;
        RECT 13.060 62.540 13.300 63.040 ;
        RECT 1.160 66.440 1.400 66.940 ;
        RECT 4.560 66.440 4.800 66.940 ;
        RECT 7.960 66.440 8.200 66.940 ;
        RECT 11.360 66.440 11.600 66.940 ;
        RECT 2.860 53.440 3.100 53.940 ;
        RECT 6.260 53.440 6.500 53.940 ;
        RECT 9.660 53.440 9.900 53.940 ;
        RECT 13.060 53.440 13.300 53.940 ;
        RECT 2.860 48.240 3.100 48.740 ;
        RECT 6.260 48.240 6.500 48.740 ;
        RECT 9.660 48.240 9.900 48.740 ;
        RECT 13.060 48.240 13.300 48.740 ;
        RECT 1.160 49.540 1.400 50.040 ;
        RECT 4.560 49.540 4.800 50.040 ;
        RECT 7.960 49.540 8.200 50.040 ;
        RECT 11.360 49.540 11.600 50.040 ;
        RECT 1.160 52.140 1.400 52.640 ;
        RECT 4.560 52.140 4.800 52.640 ;
        RECT 7.960 52.140 8.200 52.640 ;
        RECT 11.360 52.140 11.600 52.640 ;
        RECT 16.460 56.040 16.700 56.540 ;
        RECT 19.860 56.040 20.100 56.540 ;
        RECT 23.260 56.040 23.500 56.540 ;
        RECT 26.660 56.040 26.900 56.540 ;
        RECT 14.760 54.740 15.000 55.240 ;
        RECT 18.160 54.740 18.400 55.240 ;
        RECT 21.560 54.740 21.800 55.240 ;
        RECT 24.960 54.740 25.200 55.240 ;
        RECT 14.760 49.540 15.000 50.040 ;
        RECT 18.160 49.540 18.400 50.040 ;
        RECT 21.560 49.540 21.800 50.040 ;
        RECT 24.960 49.540 25.200 50.040 ;
        RECT 14.760 58.640 15.000 59.140 ;
        RECT 18.160 58.640 18.400 59.140 ;
        RECT 21.560 58.640 21.800 59.140 ;
        RECT 24.960 58.640 25.200 59.140 ;
        RECT 14.760 61.240 15.000 61.740 ;
        RECT 18.160 61.240 18.400 61.740 ;
        RECT 21.560 61.240 21.800 61.740 ;
        RECT 24.960 61.240 25.200 61.740 ;
        RECT 14.760 66.440 15.000 66.940 ;
        RECT 18.160 66.440 18.400 66.940 ;
        RECT 21.560 66.440 21.800 66.940 ;
        RECT 24.960 66.440 25.200 66.940 ;
        RECT 16.460 62.540 16.700 63.040 ;
        RECT 19.860 62.540 20.100 63.040 ;
        RECT 23.260 62.540 23.500 63.040 ;
        RECT 26.660 62.540 26.900 63.040 ;
        RECT 14.760 70.340 15.000 70.840 ;
        RECT 18.160 70.340 18.400 70.840 ;
        RECT 21.560 70.340 21.800 70.840 ;
        RECT 24.960 70.340 25.200 70.840 ;
        RECT 16.460 50.840 16.700 51.340 ;
        RECT 19.860 50.840 20.100 51.340 ;
        RECT 23.260 50.840 23.500 51.340 ;
        RECT 26.660 50.840 26.900 51.340 ;
        RECT 16.460 65.140 16.700 65.640 ;
        RECT 19.860 65.140 20.100 65.640 ;
        RECT 23.260 65.140 23.500 65.640 ;
        RECT 26.660 65.140 26.900 65.640 ;
        RECT 14.760 52.140 15.000 52.640 ;
        RECT 18.160 52.140 18.400 52.640 ;
        RECT 21.560 52.140 21.800 52.640 ;
        RECT 24.960 52.140 25.200 52.640 ;
        RECT 14.760 63.840 15.000 64.340 ;
        RECT 18.160 63.840 18.400 64.340 ;
        RECT 21.560 63.840 21.800 64.340 ;
        RECT 24.960 63.840 25.200 64.340 ;
        RECT 16.460 53.440 16.700 53.940 ;
        RECT 19.860 53.440 20.100 53.940 ;
        RECT 23.260 53.440 23.500 53.940 ;
        RECT 26.660 53.440 26.900 53.940 ;
        RECT 16.460 48.240 16.700 48.740 ;
        RECT 19.860 48.240 20.100 48.740 ;
        RECT 23.260 48.240 23.500 48.740 ;
        RECT 26.660 48.240 26.900 48.740 ;
        RECT 16.460 59.940 16.700 60.440 ;
        RECT 19.860 59.940 20.100 60.440 ;
        RECT 23.260 59.940 23.500 60.440 ;
        RECT 26.660 59.940 26.900 60.440 ;
        RECT 16.460 67.740 16.700 68.240 ;
        RECT 19.860 67.740 20.100 68.240 ;
        RECT 23.260 67.740 23.500 68.240 ;
        RECT 26.660 67.740 26.900 68.240 ;
        RECT 1.160 23.540 1.400 24.040 ;
        RECT 4.560 23.540 4.800 24.040 ;
        RECT 7.960 23.540 8.200 24.040 ;
        RECT 11.360 23.540 11.600 24.040 ;
        RECT 14.760 23.540 15.000 24.040 ;
        RECT 18.160 23.540 18.400 24.040 ;
        RECT 21.560 23.540 21.800 24.040 ;
        RECT 24.960 23.540 25.200 24.040 ;
        RECT 16.460 24.840 16.700 25.340 ;
        RECT 19.860 24.840 20.100 25.340 ;
        RECT 23.260 24.840 23.500 25.340 ;
        RECT 26.660 24.840 26.900 25.340 ;
        RECT 14.760 26.140 15.000 26.640 ;
        RECT 18.160 26.140 18.400 26.640 ;
        RECT 21.560 26.140 21.800 26.640 ;
        RECT 24.960 26.140 25.200 26.640 ;
        RECT 16.460 27.440 16.700 27.940 ;
        RECT 19.860 27.440 20.100 27.940 ;
        RECT 23.260 27.440 23.500 27.940 ;
        RECT 26.660 27.440 26.900 27.940 ;
        RECT 14.760 28.740 15.000 29.240 ;
        RECT 18.160 28.740 18.400 29.240 ;
        RECT 21.560 28.740 21.800 29.240 ;
        RECT 24.960 28.740 25.200 29.240 ;
        RECT 16.460 30.040 16.700 30.540 ;
        RECT 19.860 30.040 20.100 30.540 ;
        RECT 23.260 30.040 23.500 30.540 ;
        RECT 26.660 30.040 26.900 30.540 ;
        RECT 14.760 31.340 15.000 31.840 ;
        RECT 18.160 31.340 18.400 31.840 ;
        RECT 21.560 31.340 21.800 31.840 ;
        RECT 24.960 31.340 25.200 31.840 ;
        RECT 16.460 32.640 16.700 33.140 ;
        RECT 19.860 32.640 20.100 33.140 ;
        RECT 23.260 32.640 23.500 33.140 ;
        RECT 26.660 32.640 26.900 33.140 ;
        RECT 14.760 35.240 15.000 35.740 ;
        RECT 18.160 35.240 18.400 35.740 ;
        RECT 21.560 35.240 21.800 35.740 ;
        RECT 24.960 35.240 25.200 35.740 ;
        RECT 16.460 36.540 16.700 37.040 ;
        RECT 19.860 36.540 20.100 37.040 ;
        RECT 23.260 36.540 23.500 37.040 ;
        RECT 26.660 36.540 26.900 37.040 ;
        RECT 14.760 37.840 15.000 38.340 ;
        RECT 18.160 37.840 18.400 38.340 ;
        RECT 21.560 37.840 21.800 38.340 ;
        RECT 24.960 37.840 25.200 38.340 ;
        RECT 16.460 39.140 16.700 39.640 ;
        RECT 19.860 39.140 20.100 39.640 ;
        RECT 23.260 39.140 23.500 39.640 ;
        RECT 26.660 39.140 26.900 39.640 ;
        RECT 14.760 40.440 15.000 40.940 ;
        RECT 18.160 40.440 18.400 40.940 ;
        RECT 21.560 40.440 21.800 40.940 ;
        RECT 24.960 40.440 25.200 40.940 ;
        RECT 16.460 41.740 16.700 42.240 ;
        RECT 19.860 41.740 20.100 42.240 ;
        RECT 23.260 41.740 23.500 42.240 ;
        RECT 26.660 41.740 26.900 42.240 ;
        RECT 14.760 43.040 15.000 43.540 ;
        RECT 18.160 43.040 18.400 43.540 ;
        RECT 21.560 43.040 21.800 43.540 ;
        RECT 24.960 43.040 25.200 43.540 ;
        RECT 16.460 44.340 16.700 44.840 ;
        RECT 19.860 44.340 20.100 44.840 ;
        RECT 23.260 44.340 23.500 44.840 ;
        RECT 26.660 44.340 26.900 44.840 ;
        RECT 14.760 46.940 15.000 47.440 ;
        RECT 18.160 46.940 18.400 47.440 ;
        RECT 21.560 46.940 21.800 47.440 ;
        RECT 24.960 46.940 25.200 47.440 ;
        RECT 2.860 36.540 3.100 37.040 ;
        RECT 6.260 36.540 6.500 37.040 ;
        RECT 9.660 36.540 9.900 37.040 ;
        RECT 13.060 36.540 13.300 37.040 ;
        RECT 2.860 30.040 3.100 30.540 ;
        RECT 6.260 30.040 6.500 30.540 ;
        RECT 9.660 30.040 9.900 30.540 ;
        RECT 13.060 30.040 13.300 30.540 ;
        RECT 1.160 37.840 1.400 38.340 ;
        RECT 4.560 37.840 4.800 38.340 ;
        RECT 7.960 37.840 8.200 38.340 ;
        RECT 11.360 37.840 11.600 38.340 ;
        RECT 2.860 27.440 3.100 27.940 ;
        RECT 6.260 27.440 6.500 27.940 ;
        RECT 9.660 27.440 9.900 27.940 ;
        RECT 13.060 27.440 13.300 27.940 ;
        RECT 2.860 39.140 3.100 39.640 ;
        RECT 6.260 39.140 6.500 39.640 ;
        RECT 9.660 39.140 9.900 39.640 ;
        RECT 13.060 39.140 13.300 39.640 ;
        RECT 1.160 31.340 1.400 31.840 ;
        RECT 4.560 31.340 4.800 31.840 ;
        RECT 7.960 31.340 8.200 31.840 ;
        RECT 11.360 31.340 11.600 31.840 ;
        RECT 1.160 40.440 1.400 40.940 ;
        RECT 4.560 40.440 4.800 40.940 ;
        RECT 7.960 40.440 8.200 40.940 ;
        RECT 11.360 40.440 11.600 40.940 ;
        RECT 1.160 26.140 1.400 26.640 ;
        RECT 4.560 26.140 4.800 26.640 ;
        RECT 7.960 26.140 8.200 26.640 ;
        RECT 11.360 26.140 11.600 26.640 ;
        RECT 2.860 41.740 3.100 42.240 ;
        RECT 6.260 41.740 6.500 42.240 ;
        RECT 9.660 41.740 9.900 42.240 ;
        RECT 13.060 41.740 13.300 42.240 ;
        RECT 2.860 32.640 3.100 33.140 ;
        RECT 6.260 32.640 6.500 33.140 ;
        RECT 9.660 32.640 9.900 33.140 ;
        RECT 13.060 32.640 13.300 33.140 ;
        RECT 1.160 43.040 1.400 43.540 ;
        RECT 4.560 43.040 4.800 43.540 ;
        RECT 7.960 43.040 8.200 43.540 ;
        RECT 11.360 43.040 11.600 43.540 ;
        RECT 1.160 28.740 1.400 29.240 ;
        RECT 4.560 28.740 4.800 29.240 ;
        RECT 7.960 28.740 8.200 29.240 ;
        RECT 11.360 28.740 11.600 29.240 ;
        RECT 2.860 44.340 3.100 44.840 ;
        RECT 6.260 44.340 6.500 44.840 ;
        RECT 9.660 44.340 9.900 44.840 ;
        RECT 13.060 44.340 13.300 44.840 ;
        RECT 1.160 35.240 1.400 35.740 ;
        RECT 4.560 35.240 4.800 35.740 ;
        RECT 7.960 35.240 8.200 35.740 ;
        RECT 11.360 35.240 11.600 35.740 ;
        RECT 1.160 46.940 1.400 47.440 ;
        RECT 4.560 46.940 4.800 47.440 ;
        RECT 7.960 46.940 8.200 47.440 ;
        RECT 11.360 46.940 11.600 47.440 ;
        RECT 2.860 24.840 3.100 25.340 ;
        RECT 6.260 24.840 6.500 25.340 ;
        RECT 9.660 24.840 9.900 25.340 ;
        RECT 13.060 24.840 13.300 25.340 ;
        RECT 1.160 2.740 1.400 3.240 ;
        RECT 4.560 2.740 4.800 3.240 ;
        RECT 7.960 2.740 8.200 3.240 ;
        RECT 11.360 2.740 11.600 3.240 ;
        RECT 2.860 4.040 3.100 4.540 ;
        RECT 6.260 4.040 6.500 4.540 ;
        RECT 9.660 4.040 9.900 4.540 ;
        RECT 13.060 4.040 13.300 4.540 ;
        RECT 1.160 5.340 1.400 5.840 ;
        RECT 4.560 5.340 4.800 5.840 ;
        RECT 7.960 5.340 8.200 5.840 ;
        RECT 11.360 5.340 11.600 5.840 ;
        RECT 2.860 6.640 3.100 7.140 ;
        RECT 6.260 6.640 6.500 7.140 ;
        RECT 9.660 6.640 9.900 7.140 ;
        RECT 13.060 6.640 13.300 7.140 ;
        RECT 1.160 7.940 1.400 8.440 ;
        RECT 4.560 7.940 4.800 8.440 ;
        RECT 7.960 7.940 8.200 8.440 ;
        RECT 11.360 7.940 11.600 8.440 ;
        RECT 2.860 9.240 3.100 9.740 ;
        RECT 6.260 9.240 6.500 9.740 ;
        RECT 9.660 9.240 9.900 9.740 ;
        RECT 13.060 9.240 13.300 9.740 ;
        RECT 1.160 11.840 1.400 12.340 ;
        RECT 4.560 11.840 4.800 12.340 ;
        RECT 7.960 11.840 8.200 12.340 ;
        RECT 11.360 11.840 11.600 12.340 ;
        RECT 2.860 13.140 3.100 13.640 ;
        RECT 6.260 13.140 6.500 13.640 ;
        RECT 9.660 13.140 9.900 13.640 ;
        RECT 13.060 13.140 13.300 13.640 ;
        RECT 1.160 14.440 1.400 14.940 ;
        RECT 4.560 14.440 4.800 14.940 ;
        RECT 7.960 14.440 8.200 14.940 ;
        RECT 11.360 14.440 11.600 14.940 ;
        RECT 2.860 15.740 3.100 16.240 ;
        RECT 6.260 15.740 6.500 16.240 ;
        RECT 9.660 15.740 9.900 16.240 ;
        RECT 13.060 15.740 13.300 16.240 ;
        RECT 1.160 17.040 1.400 17.540 ;
        RECT 4.560 17.040 4.800 17.540 ;
        RECT 7.960 17.040 8.200 17.540 ;
        RECT 11.360 17.040 11.600 17.540 ;
        RECT 2.860 18.340 3.100 18.840 ;
        RECT 6.260 18.340 6.500 18.840 ;
        RECT 9.660 18.340 9.900 18.840 ;
        RECT 13.060 18.340 13.300 18.840 ;
        RECT 1.160 19.640 1.400 20.140 ;
        RECT 4.560 19.640 4.800 20.140 ;
        RECT 7.960 19.640 8.200 20.140 ;
        RECT 11.360 19.640 11.600 20.140 ;
        RECT 2.860 20.940 3.100 21.440 ;
        RECT 6.260 20.940 6.500 21.440 ;
        RECT 9.660 20.940 9.900 21.440 ;
        RECT 13.060 20.940 13.300 21.440 ;
        RECT 1.160 0.140 1.400 0.640 ;
        RECT 4.560 0.140 4.800 0.640 ;
        RECT 7.960 0.140 8.200 0.640 ;
        RECT 11.360 0.140 11.600 0.640 ;
        RECT 2.860 1.440 3.100 1.940 ;
        RECT 6.260 1.440 6.500 1.940 ;
        RECT 9.660 1.440 9.900 1.940 ;
        RECT 13.060 1.440 13.300 1.940 ;
        RECT 14.760 5.340 15.000 5.840 ;
        RECT 18.160 5.340 18.400 5.840 ;
        RECT 21.560 5.340 21.800 5.840 ;
        RECT 24.960 5.340 25.200 5.840 ;
        RECT 16.460 13.140 16.700 13.640 ;
        RECT 19.860 13.140 20.100 13.640 ;
        RECT 23.260 13.140 23.500 13.640 ;
        RECT 26.660 13.140 26.900 13.640 ;
        RECT 14.760 2.740 15.000 3.240 ;
        RECT 18.160 2.740 18.400 3.240 ;
        RECT 21.560 2.740 21.800 3.240 ;
        RECT 24.960 2.740 25.200 3.240 ;
        RECT 14.760 14.440 15.000 14.940 ;
        RECT 18.160 14.440 18.400 14.940 ;
        RECT 21.560 14.440 21.800 14.940 ;
        RECT 24.960 14.440 25.200 14.940 ;
        RECT 16.460 6.640 16.700 7.140 ;
        RECT 19.860 6.640 20.100 7.140 ;
        RECT 23.260 6.640 23.500 7.140 ;
        RECT 26.660 6.640 26.900 7.140 ;
        RECT 16.460 15.740 16.700 16.240 ;
        RECT 19.860 15.740 20.100 16.240 ;
        RECT 23.260 15.740 23.500 16.240 ;
        RECT 26.660 15.740 26.900 16.240 ;
        RECT 16.460 1.440 16.700 1.940 ;
        RECT 19.860 1.440 20.100 1.940 ;
        RECT 23.260 1.440 23.500 1.940 ;
        RECT 26.660 1.440 26.900 1.940 ;
        RECT 14.760 17.040 15.000 17.540 ;
        RECT 18.160 17.040 18.400 17.540 ;
        RECT 21.560 17.040 21.800 17.540 ;
        RECT 24.960 17.040 25.200 17.540 ;
        RECT 14.760 7.940 15.000 8.440 ;
        RECT 18.160 7.940 18.400 8.440 ;
        RECT 21.560 7.940 21.800 8.440 ;
        RECT 24.960 7.940 25.200 8.440 ;
        RECT 16.460 18.340 16.700 18.840 ;
        RECT 19.860 18.340 20.100 18.840 ;
        RECT 23.260 18.340 23.500 18.840 ;
        RECT 26.660 18.340 26.900 18.840 ;
        RECT 16.460 4.040 16.700 4.540 ;
        RECT 19.860 4.040 20.100 4.540 ;
        RECT 23.260 4.040 23.500 4.540 ;
        RECT 26.660 4.040 26.900 4.540 ;
        RECT 14.760 19.640 15.000 20.140 ;
        RECT 18.160 19.640 18.400 20.140 ;
        RECT 21.560 19.640 21.800 20.140 ;
        RECT 24.960 19.640 25.200 20.140 ;
        RECT 16.460 9.240 16.700 9.740 ;
        RECT 19.860 9.240 20.100 9.740 ;
        RECT 23.260 9.240 23.500 9.740 ;
        RECT 26.660 9.240 26.900 9.740 ;
        RECT 16.460 20.940 16.700 21.440 ;
        RECT 19.860 20.940 20.100 21.440 ;
        RECT 23.260 20.940 23.500 21.440 ;
        RECT 26.660 20.940 26.900 21.440 ;
        RECT 14.760 0.140 15.000 0.640 ;
        RECT 18.160 0.140 18.400 0.640 ;
        RECT 21.560 0.140 21.800 0.640 ;
        RECT 24.960 0.140 25.200 0.640 ;
        RECT 14.760 11.840 15.000 12.340 ;
        RECT 18.160 11.840 18.400 12.340 ;
        RECT 21.560 11.840 21.800 12.340 ;
        RECT 24.960 11.840 25.200 12.340 ;
        RECT 28.360 23.540 28.600 24.040 ;
        RECT 31.760 23.540 32.000 24.040 ;
        RECT 35.160 23.540 35.400 24.040 ;
        RECT 38.560 23.540 38.800 24.040 ;
        RECT 41.960 23.540 42.200 24.040 ;
        RECT 45.360 23.540 45.600 24.040 ;
        RECT 48.760 23.540 49.000 24.040 ;
        RECT 52.160 23.540 52.400 24.040 ;
        RECT 43.660 24.840 43.900 25.340 ;
        RECT 47.060 24.840 47.300 25.340 ;
        RECT 50.460 24.840 50.700 25.340 ;
        RECT 53.860 24.840 54.100 25.340 ;
        RECT 41.960 26.140 42.200 26.640 ;
        RECT 45.360 26.140 45.600 26.640 ;
        RECT 48.760 26.140 49.000 26.640 ;
        RECT 52.160 26.140 52.400 26.640 ;
        RECT 43.660 27.440 43.900 27.940 ;
        RECT 47.060 27.440 47.300 27.940 ;
        RECT 50.460 27.440 50.700 27.940 ;
        RECT 53.860 27.440 54.100 27.940 ;
        RECT 41.960 28.740 42.200 29.240 ;
        RECT 45.360 28.740 45.600 29.240 ;
        RECT 48.760 28.740 49.000 29.240 ;
        RECT 52.160 28.740 52.400 29.240 ;
        RECT 43.660 30.040 43.900 30.540 ;
        RECT 47.060 30.040 47.300 30.540 ;
        RECT 50.460 30.040 50.700 30.540 ;
        RECT 53.860 30.040 54.100 30.540 ;
        RECT 41.960 31.340 42.200 31.840 ;
        RECT 45.360 31.340 45.600 31.840 ;
        RECT 48.760 31.340 49.000 31.840 ;
        RECT 52.160 31.340 52.400 31.840 ;
        RECT 43.660 32.640 43.900 33.140 ;
        RECT 47.060 32.640 47.300 33.140 ;
        RECT 50.460 32.640 50.700 33.140 ;
        RECT 53.860 32.640 54.100 33.140 ;
        RECT 41.960 35.240 42.200 35.740 ;
        RECT 45.360 35.240 45.600 35.740 ;
        RECT 48.760 35.240 49.000 35.740 ;
        RECT 52.160 35.240 52.400 35.740 ;
        RECT 43.660 36.540 43.900 37.040 ;
        RECT 47.060 36.540 47.300 37.040 ;
        RECT 50.460 36.540 50.700 37.040 ;
        RECT 53.860 36.540 54.100 37.040 ;
        RECT 41.960 37.840 42.200 38.340 ;
        RECT 45.360 37.840 45.600 38.340 ;
        RECT 48.760 37.840 49.000 38.340 ;
        RECT 52.160 37.840 52.400 38.340 ;
        RECT 43.660 39.140 43.900 39.640 ;
        RECT 47.060 39.140 47.300 39.640 ;
        RECT 50.460 39.140 50.700 39.640 ;
        RECT 53.860 39.140 54.100 39.640 ;
        RECT 41.960 40.440 42.200 40.940 ;
        RECT 45.360 40.440 45.600 40.940 ;
        RECT 48.760 40.440 49.000 40.940 ;
        RECT 52.160 40.440 52.400 40.940 ;
        RECT 43.660 41.740 43.900 42.240 ;
        RECT 47.060 41.740 47.300 42.240 ;
        RECT 50.460 41.740 50.700 42.240 ;
        RECT 53.860 41.740 54.100 42.240 ;
        RECT 41.960 43.040 42.200 43.540 ;
        RECT 45.360 43.040 45.600 43.540 ;
        RECT 48.760 43.040 49.000 43.540 ;
        RECT 52.160 43.040 52.400 43.540 ;
        RECT 43.660 44.340 43.900 44.840 ;
        RECT 47.060 44.340 47.300 44.840 ;
        RECT 50.460 44.340 50.700 44.840 ;
        RECT 53.860 44.340 54.100 44.840 ;
        RECT 41.960 46.940 42.200 47.440 ;
        RECT 45.360 46.940 45.600 47.440 ;
        RECT 48.760 46.940 49.000 47.440 ;
        RECT 52.160 46.940 52.400 47.440 ;
        RECT 30.060 36.540 30.300 37.040 ;
        RECT 33.460 36.540 33.700 37.040 ;
        RECT 36.860 36.540 37.100 37.040 ;
        RECT 40.260 36.540 40.500 37.040 ;
        RECT 30.060 30.040 30.300 30.540 ;
        RECT 33.460 30.040 33.700 30.540 ;
        RECT 36.860 30.040 37.100 30.540 ;
        RECT 40.260 30.040 40.500 30.540 ;
        RECT 28.360 37.840 28.600 38.340 ;
        RECT 31.760 37.840 32.000 38.340 ;
        RECT 35.160 37.840 35.400 38.340 ;
        RECT 38.560 37.840 38.800 38.340 ;
        RECT 30.060 27.440 30.300 27.940 ;
        RECT 33.460 27.440 33.700 27.940 ;
        RECT 36.860 27.440 37.100 27.940 ;
        RECT 40.260 27.440 40.500 27.940 ;
        RECT 30.060 39.140 30.300 39.640 ;
        RECT 33.460 39.140 33.700 39.640 ;
        RECT 36.860 39.140 37.100 39.640 ;
        RECT 40.260 39.140 40.500 39.640 ;
        RECT 28.360 31.340 28.600 31.840 ;
        RECT 31.760 31.340 32.000 31.840 ;
        RECT 35.160 31.340 35.400 31.840 ;
        RECT 38.560 31.340 38.800 31.840 ;
        RECT 28.360 40.440 28.600 40.940 ;
        RECT 31.760 40.440 32.000 40.940 ;
        RECT 35.160 40.440 35.400 40.940 ;
        RECT 38.560 40.440 38.800 40.940 ;
        RECT 28.360 26.140 28.600 26.640 ;
        RECT 31.760 26.140 32.000 26.640 ;
        RECT 35.160 26.140 35.400 26.640 ;
        RECT 38.560 26.140 38.800 26.640 ;
        RECT 30.060 41.740 30.300 42.240 ;
        RECT 33.460 41.740 33.700 42.240 ;
        RECT 36.860 41.740 37.100 42.240 ;
        RECT 40.260 41.740 40.500 42.240 ;
        RECT 30.060 32.640 30.300 33.140 ;
        RECT 33.460 32.640 33.700 33.140 ;
        RECT 36.860 32.640 37.100 33.140 ;
        RECT 40.260 32.640 40.500 33.140 ;
        RECT 28.360 43.040 28.600 43.540 ;
        RECT 31.760 43.040 32.000 43.540 ;
        RECT 35.160 43.040 35.400 43.540 ;
        RECT 38.560 43.040 38.800 43.540 ;
        RECT 28.360 28.740 28.600 29.240 ;
        RECT 31.760 28.740 32.000 29.240 ;
        RECT 35.160 28.740 35.400 29.240 ;
        RECT 38.560 28.740 38.800 29.240 ;
        RECT 30.060 44.340 30.300 44.840 ;
        RECT 33.460 44.340 33.700 44.840 ;
        RECT 36.860 44.340 37.100 44.840 ;
        RECT 40.260 44.340 40.500 44.840 ;
        RECT 28.360 35.240 28.600 35.740 ;
        RECT 31.760 35.240 32.000 35.740 ;
        RECT 35.160 35.240 35.400 35.740 ;
        RECT 38.560 35.240 38.800 35.740 ;
        RECT 28.360 46.940 28.600 47.440 ;
        RECT 31.760 46.940 32.000 47.440 ;
        RECT 35.160 46.940 35.400 47.440 ;
        RECT 38.560 46.940 38.800 47.440 ;
        RECT 30.060 24.840 30.300 25.340 ;
        RECT 33.460 24.840 33.700 25.340 ;
        RECT 36.860 24.840 37.100 25.340 ;
        RECT 40.260 24.840 40.500 25.340 ;
        RECT 30.060 1.440 30.300 1.940 ;
        RECT 33.460 1.440 33.700 1.940 ;
        RECT 36.860 1.440 37.100 1.940 ;
        RECT 40.260 1.440 40.500 1.940 ;
        RECT 30.060 4.040 30.300 4.540 ;
        RECT 33.460 4.040 33.700 4.540 ;
        RECT 36.860 4.040 37.100 4.540 ;
        RECT 40.260 4.040 40.500 4.540 ;
        RECT 28.360 2.740 28.600 3.240 ;
        RECT 31.760 2.740 32.000 3.240 ;
        RECT 35.160 2.740 35.400 3.240 ;
        RECT 38.560 2.740 38.800 3.240 ;
        RECT 30.060 6.640 30.300 7.140 ;
        RECT 33.460 6.640 33.700 7.140 ;
        RECT 36.860 6.640 37.100 7.140 ;
        RECT 40.260 6.640 40.500 7.140 ;
        RECT 28.360 19.640 28.600 20.140 ;
        RECT 31.760 19.640 32.000 20.140 ;
        RECT 35.160 19.640 35.400 20.140 ;
        RECT 38.560 19.640 38.800 20.140 ;
        RECT 28.360 17.040 28.600 17.540 ;
        RECT 31.760 17.040 32.000 17.540 ;
        RECT 35.160 17.040 35.400 17.540 ;
        RECT 38.560 17.040 38.800 17.540 ;
        RECT 30.060 13.140 30.300 13.640 ;
        RECT 33.460 13.140 33.700 13.640 ;
        RECT 36.860 13.140 37.100 13.640 ;
        RECT 40.260 13.140 40.500 13.640 ;
        RECT 30.060 9.240 30.300 9.740 ;
        RECT 33.460 9.240 33.700 9.740 ;
        RECT 36.860 9.240 37.100 9.740 ;
        RECT 40.260 9.240 40.500 9.740 ;
        RECT 28.360 11.840 28.600 12.340 ;
        RECT 31.760 11.840 32.000 12.340 ;
        RECT 35.160 11.840 35.400 12.340 ;
        RECT 38.560 11.840 38.800 12.340 ;
        RECT 28.360 7.940 28.600 8.440 ;
        RECT 31.760 7.940 32.000 8.440 ;
        RECT 35.160 7.940 35.400 8.440 ;
        RECT 38.560 7.940 38.800 8.440 ;
        RECT 30.060 20.940 30.300 21.440 ;
        RECT 33.460 20.940 33.700 21.440 ;
        RECT 36.860 20.940 37.100 21.440 ;
        RECT 40.260 20.940 40.500 21.440 ;
        RECT 30.060 15.740 30.300 16.240 ;
        RECT 33.460 15.740 33.700 16.240 ;
        RECT 36.860 15.740 37.100 16.240 ;
        RECT 40.260 15.740 40.500 16.240 ;
        RECT 28.360 14.440 28.600 14.940 ;
        RECT 31.760 14.440 32.000 14.940 ;
        RECT 35.160 14.440 35.400 14.940 ;
        RECT 38.560 14.440 38.800 14.940 ;
        RECT 28.360 0.140 28.600 0.640 ;
        RECT 31.760 0.140 32.000 0.640 ;
        RECT 35.160 0.140 35.400 0.640 ;
        RECT 38.560 0.140 38.800 0.640 ;
        RECT 30.060 18.340 30.300 18.840 ;
        RECT 33.460 18.340 33.700 18.840 ;
        RECT 36.860 18.340 37.100 18.840 ;
        RECT 40.260 18.340 40.500 18.840 ;
        RECT 28.360 5.340 28.600 5.840 ;
        RECT 31.760 5.340 32.000 5.840 ;
        RECT 35.160 5.340 35.400 5.840 ;
        RECT 38.560 5.340 38.800 5.840 ;
        RECT 41.960 11.840 42.200 12.340 ;
        RECT 45.360 11.840 45.600 12.340 ;
        RECT 48.760 11.840 49.000 12.340 ;
        RECT 52.160 11.840 52.400 12.340 ;
        RECT 41.960 19.640 42.200 20.140 ;
        RECT 45.360 19.640 45.600 20.140 ;
        RECT 48.760 19.640 49.000 20.140 ;
        RECT 52.160 19.640 52.400 20.140 ;
        RECT 41.960 7.940 42.200 8.440 ;
        RECT 45.360 7.940 45.600 8.440 ;
        RECT 48.760 7.940 49.000 8.440 ;
        RECT 52.160 7.940 52.400 8.440 ;
        RECT 43.660 6.640 43.900 7.140 ;
        RECT 47.060 6.640 47.300 7.140 ;
        RECT 50.460 6.640 50.700 7.140 ;
        RECT 53.860 6.640 54.100 7.140 ;
        RECT 43.660 1.440 43.900 1.940 ;
        RECT 47.060 1.440 47.300 1.940 ;
        RECT 50.460 1.440 50.700 1.940 ;
        RECT 53.860 1.440 54.100 1.940 ;
        RECT 43.660 9.240 43.900 9.740 ;
        RECT 47.060 9.240 47.300 9.740 ;
        RECT 50.460 9.240 50.700 9.740 ;
        RECT 53.860 9.240 54.100 9.740 ;
        RECT 43.660 13.140 43.900 13.640 ;
        RECT 47.060 13.140 47.300 13.640 ;
        RECT 50.460 13.140 50.700 13.640 ;
        RECT 53.860 13.140 54.100 13.640 ;
        RECT 43.660 18.340 43.900 18.840 ;
        RECT 47.060 18.340 47.300 18.840 ;
        RECT 50.460 18.340 50.700 18.840 ;
        RECT 53.860 18.340 54.100 18.840 ;
        RECT 41.960 14.440 42.200 14.940 ;
        RECT 45.360 14.440 45.600 14.940 ;
        RECT 48.760 14.440 49.000 14.940 ;
        RECT 52.160 14.440 52.400 14.940 ;
        RECT 43.660 20.940 43.900 21.440 ;
        RECT 47.060 20.940 47.300 21.440 ;
        RECT 50.460 20.940 50.700 21.440 ;
        RECT 53.860 20.940 54.100 21.440 ;
        RECT 41.960 2.740 42.200 3.240 ;
        RECT 45.360 2.740 45.600 3.240 ;
        RECT 48.760 2.740 49.000 3.240 ;
        RECT 52.160 2.740 52.400 3.240 ;
        RECT 41.960 17.040 42.200 17.540 ;
        RECT 45.360 17.040 45.600 17.540 ;
        RECT 48.760 17.040 49.000 17.540 ;
        RECT 52.160 17.040 52.400 17.540 ;
        RECT 43.660 4.040 43.900 4.540 ;
        RECT 47.060 4.040 47.300 4.540 ;
        RECT 50.460 4.040 50.700 4.540 ;
        RECT 53.860 4.040 54.100 4.540 ;
        RECT 41.960 0.140 42.200 0.640 ;
        RECT 45.360 0.140 45.600 0.640 ;
        RECT 48.760 0.140 49.000 0.640 ;
        RECT 52.160 0.140 52.400 0.640 ;
        RECT 43.660 15.740 43.900 16.240 ;
        RECT 47.060 15.740 47.300 16.240 ;
        RECT 50.460 15.740 50.700 16.240 ;
        RECT 53.860 15.740 54.100 16.240 ;
        RECT 41.960 5.340 42.200 5.840 ;
        RECT 45.360 5.340 45.600 5.840 ;
        RECT 48.760 5.340 49.000 5.840 ;
        RECT 52.160 5.340 52.400 5.840 ;
  END
END macro_array_pc_64x32_checker
END LIBRARY

